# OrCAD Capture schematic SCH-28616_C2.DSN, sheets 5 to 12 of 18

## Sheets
5 M-06 Audio: size C
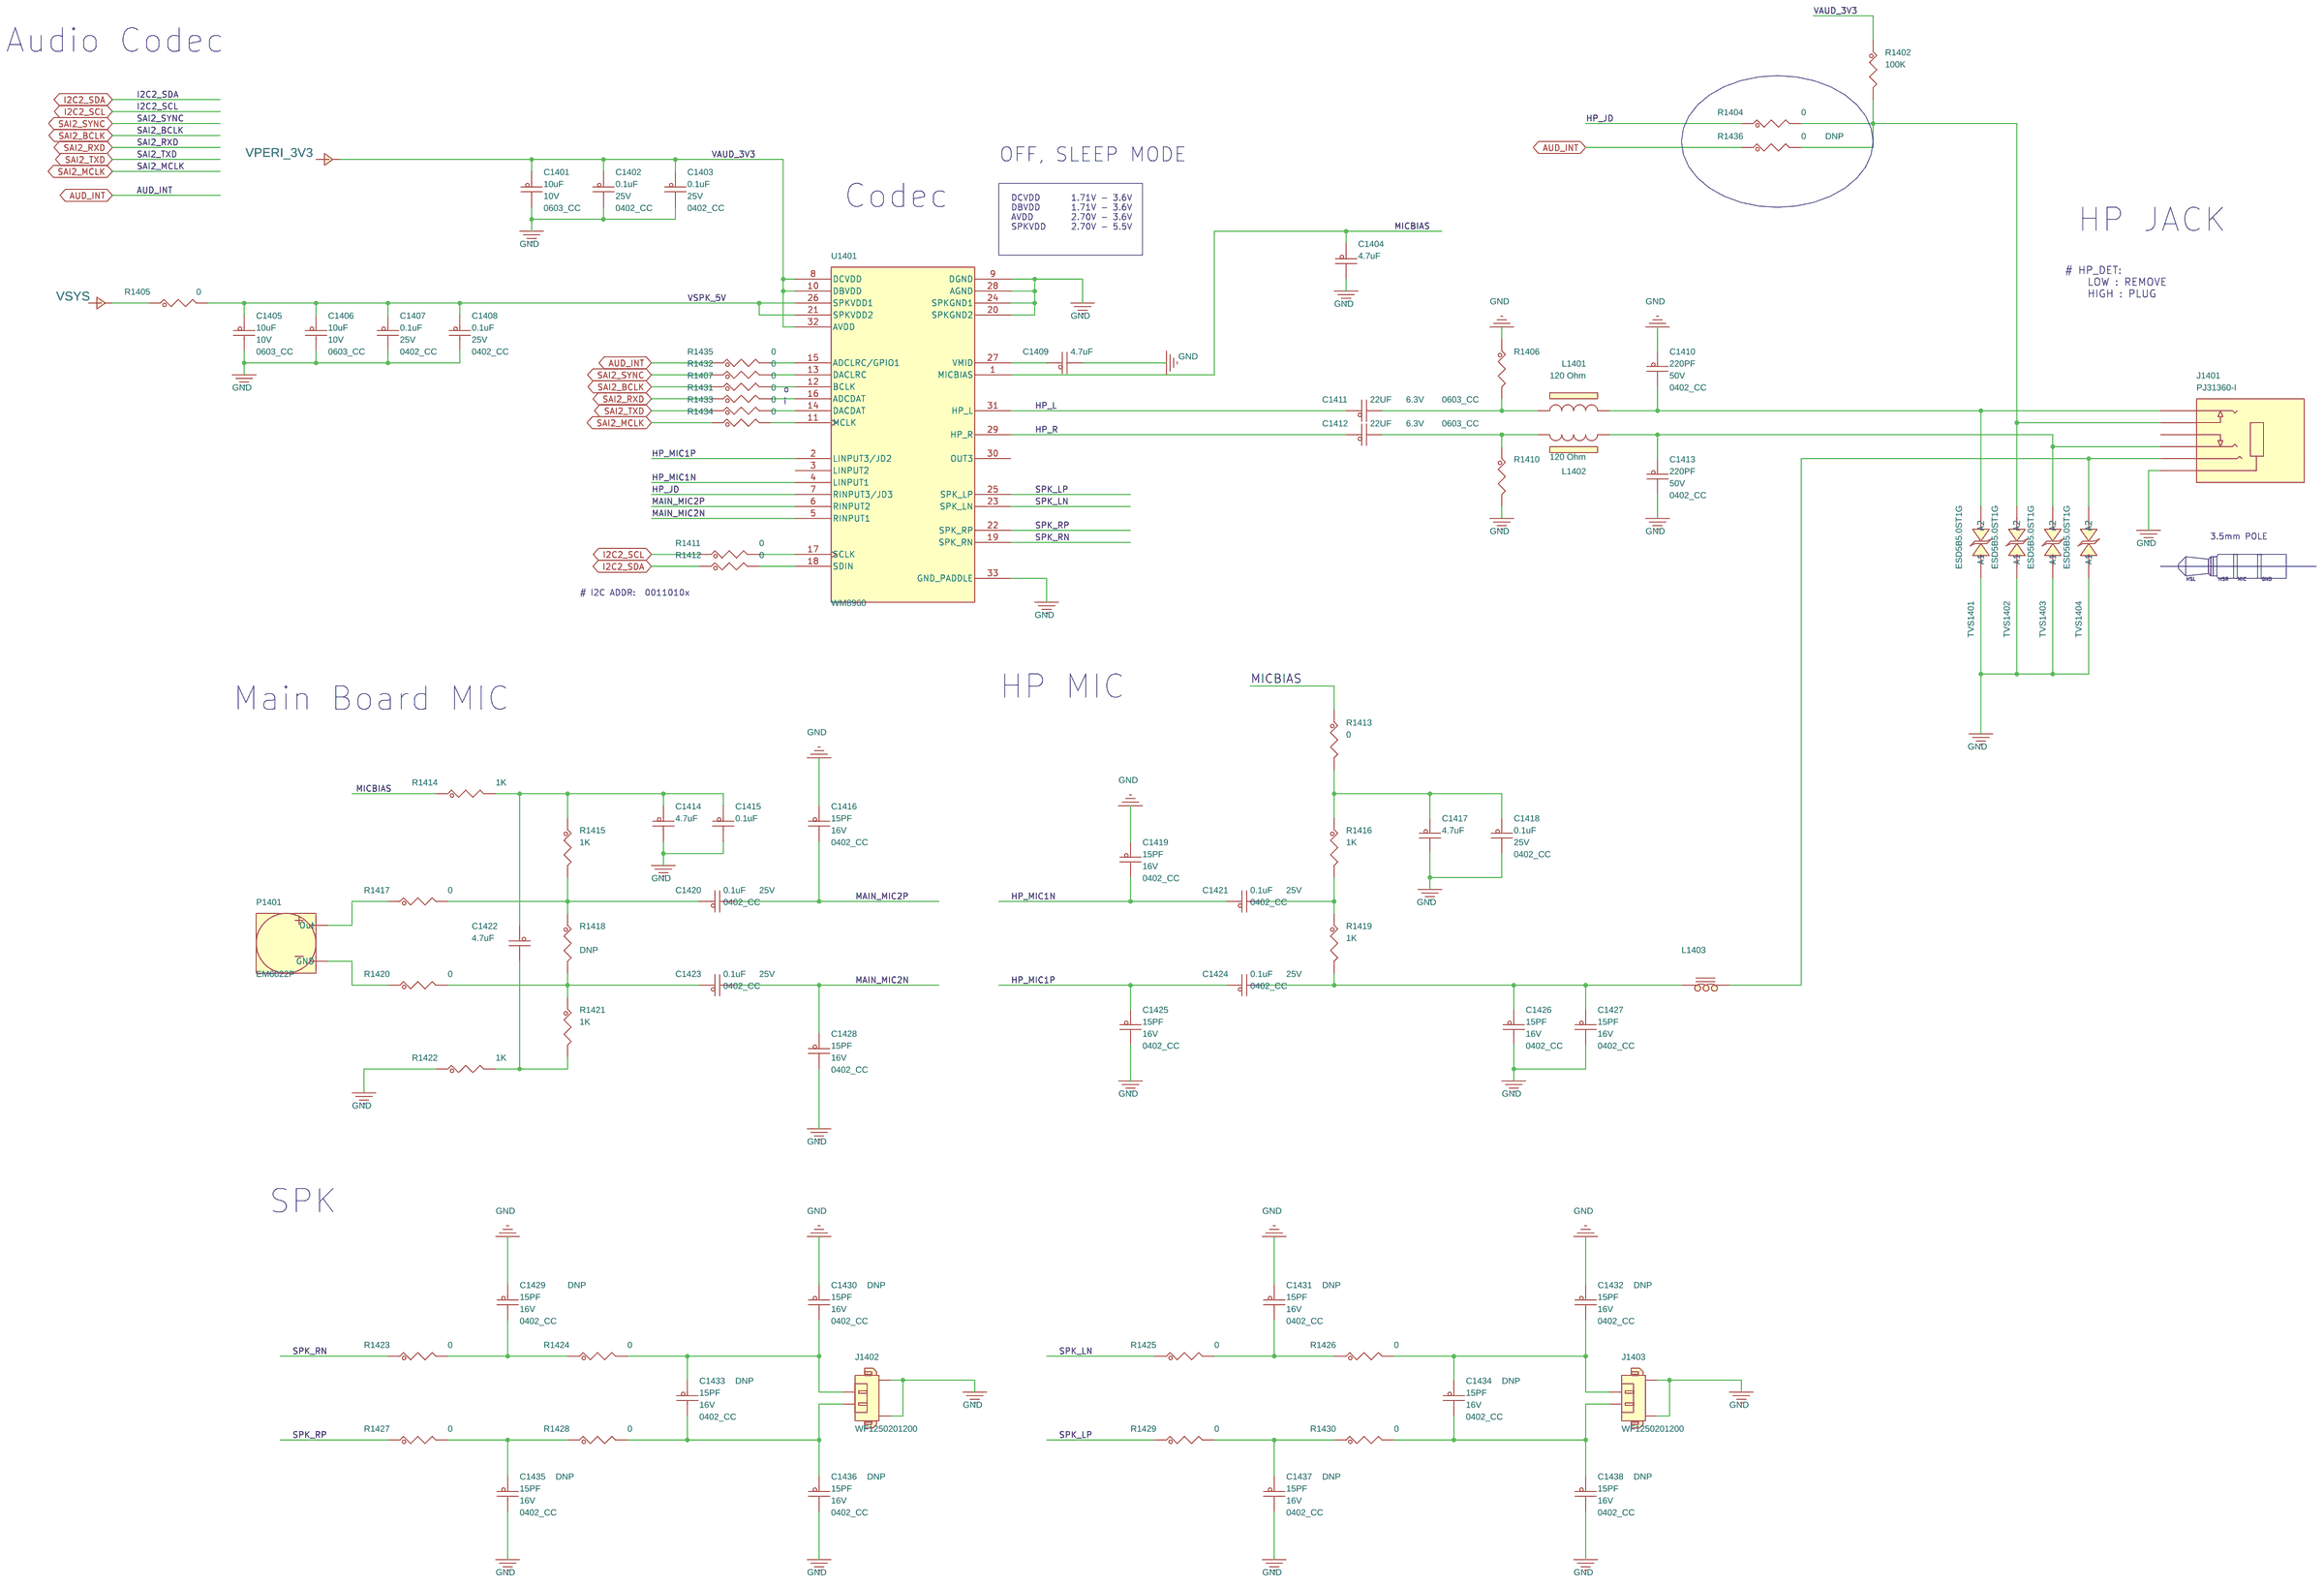
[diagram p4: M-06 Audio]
6 M-05 Sensor: size C
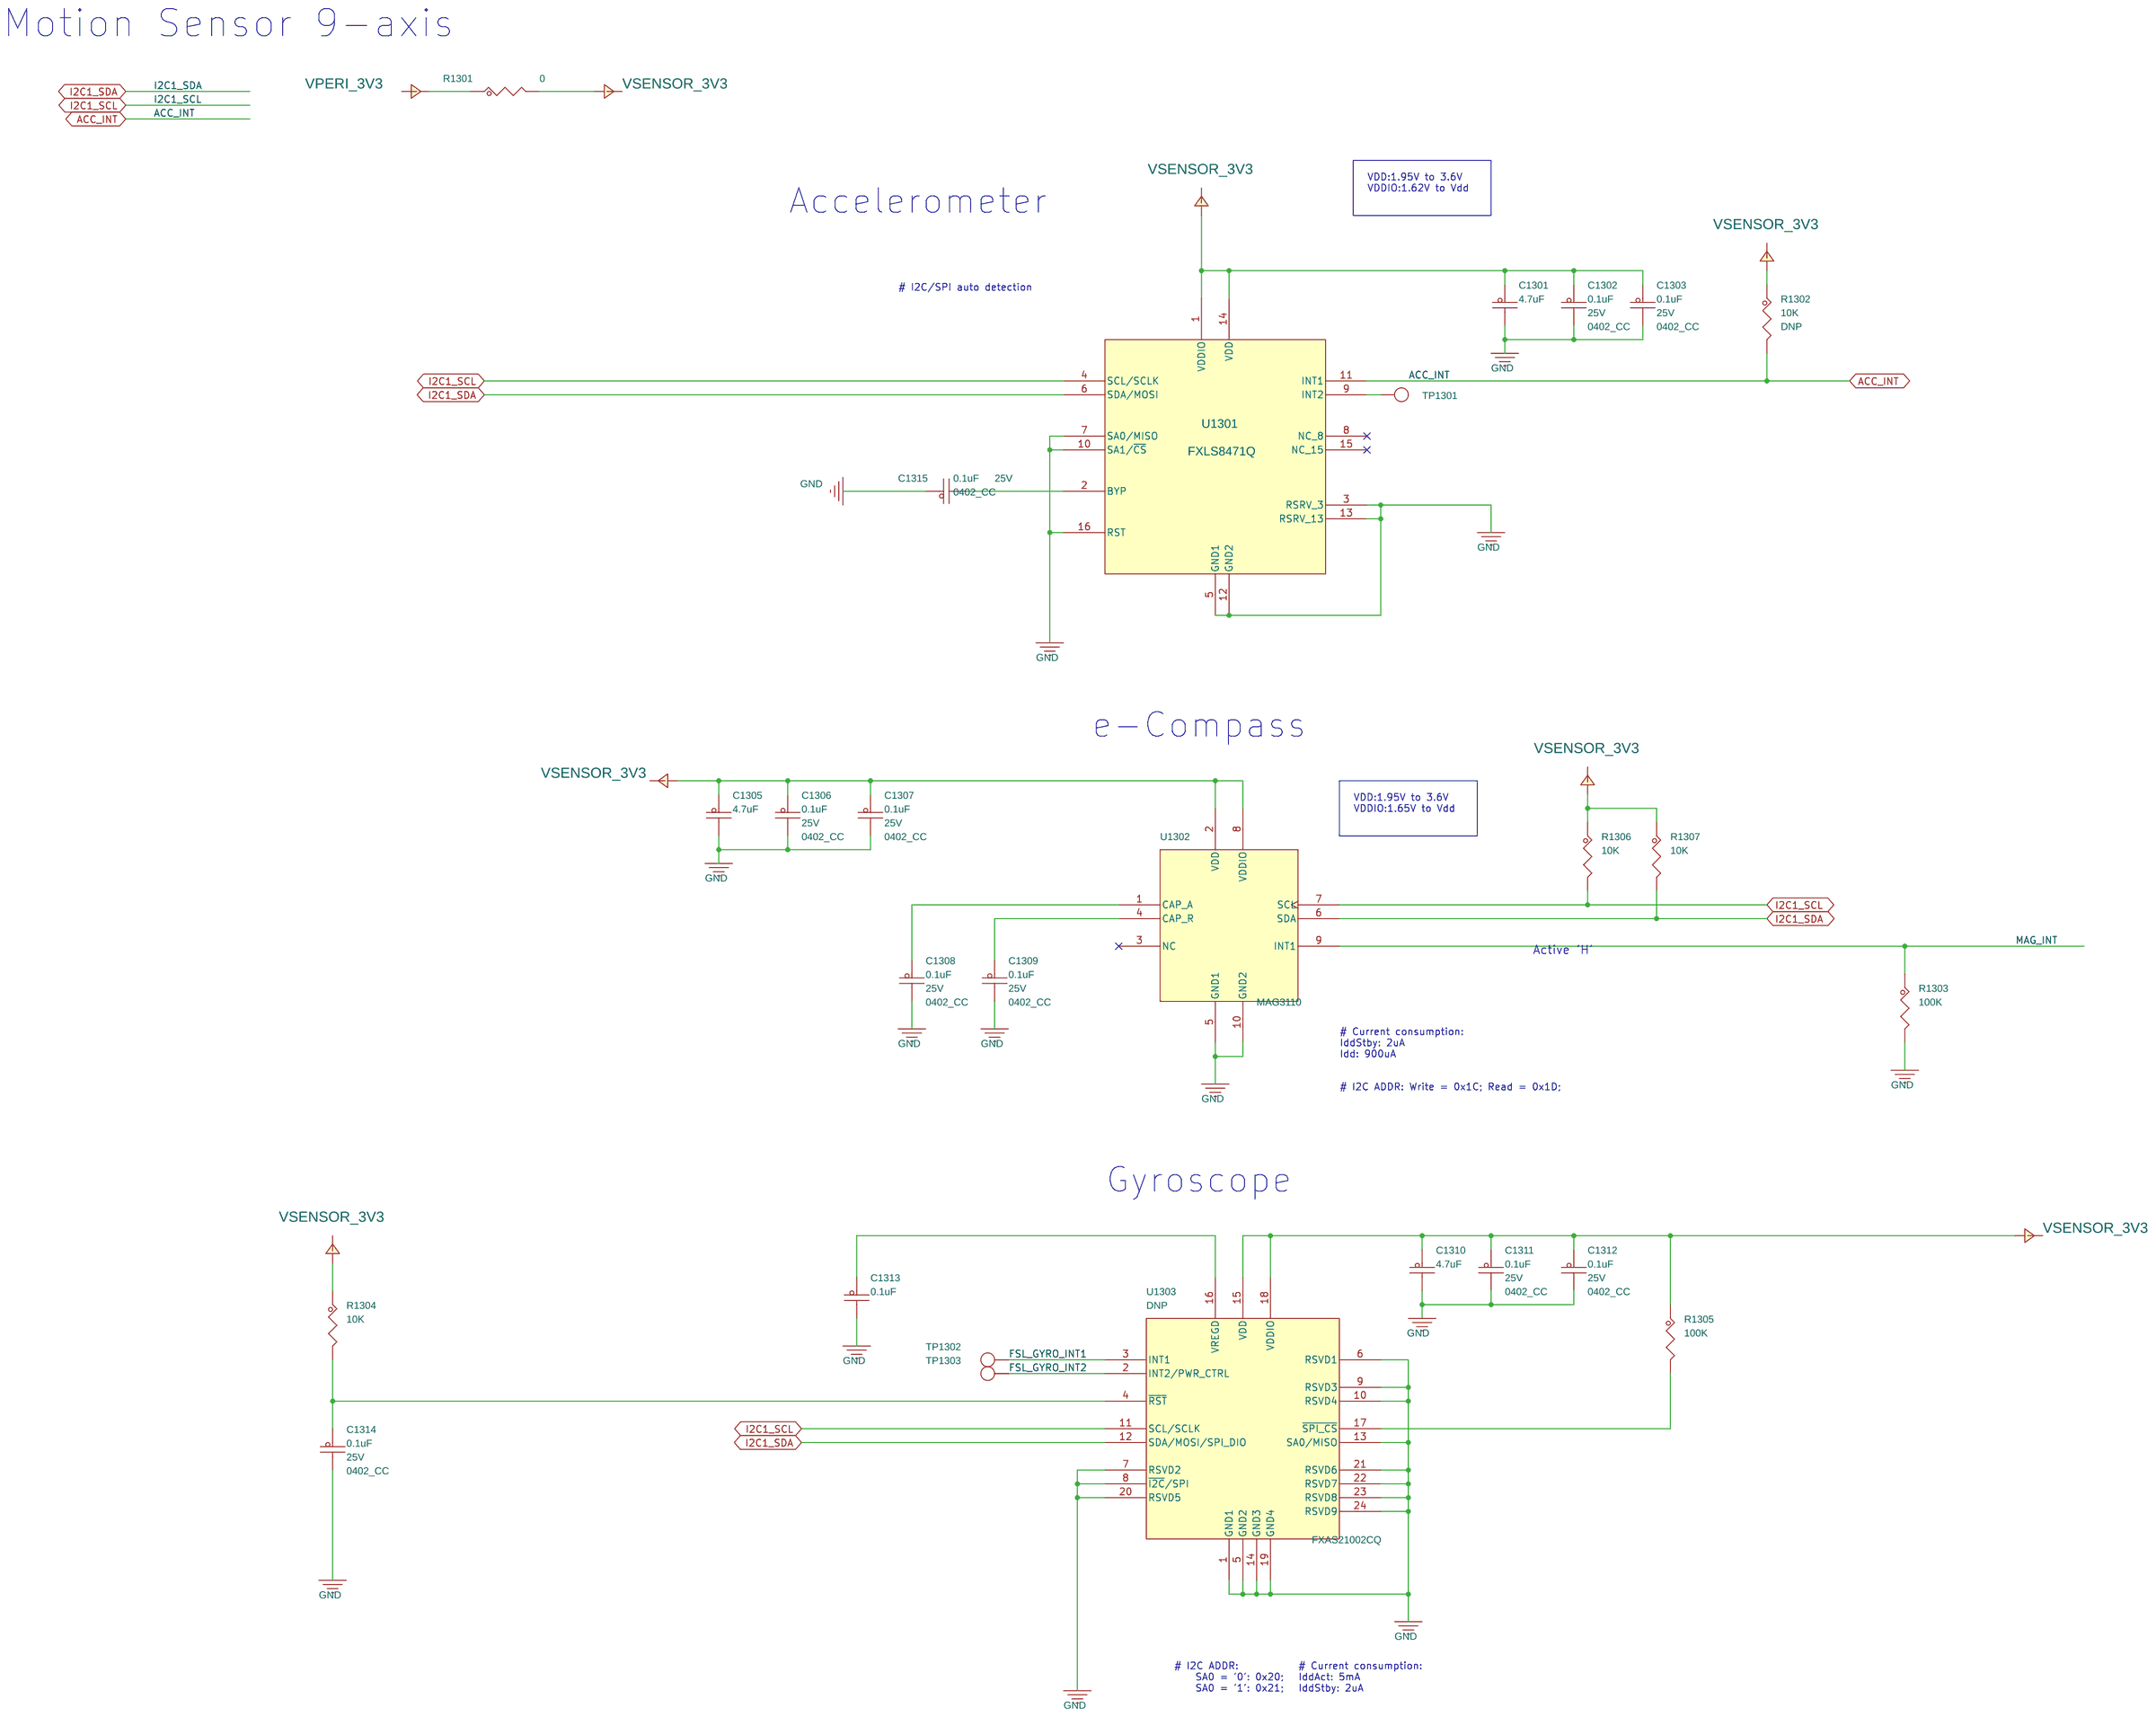
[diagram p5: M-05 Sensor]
7 M-04 CAN BUS: size C
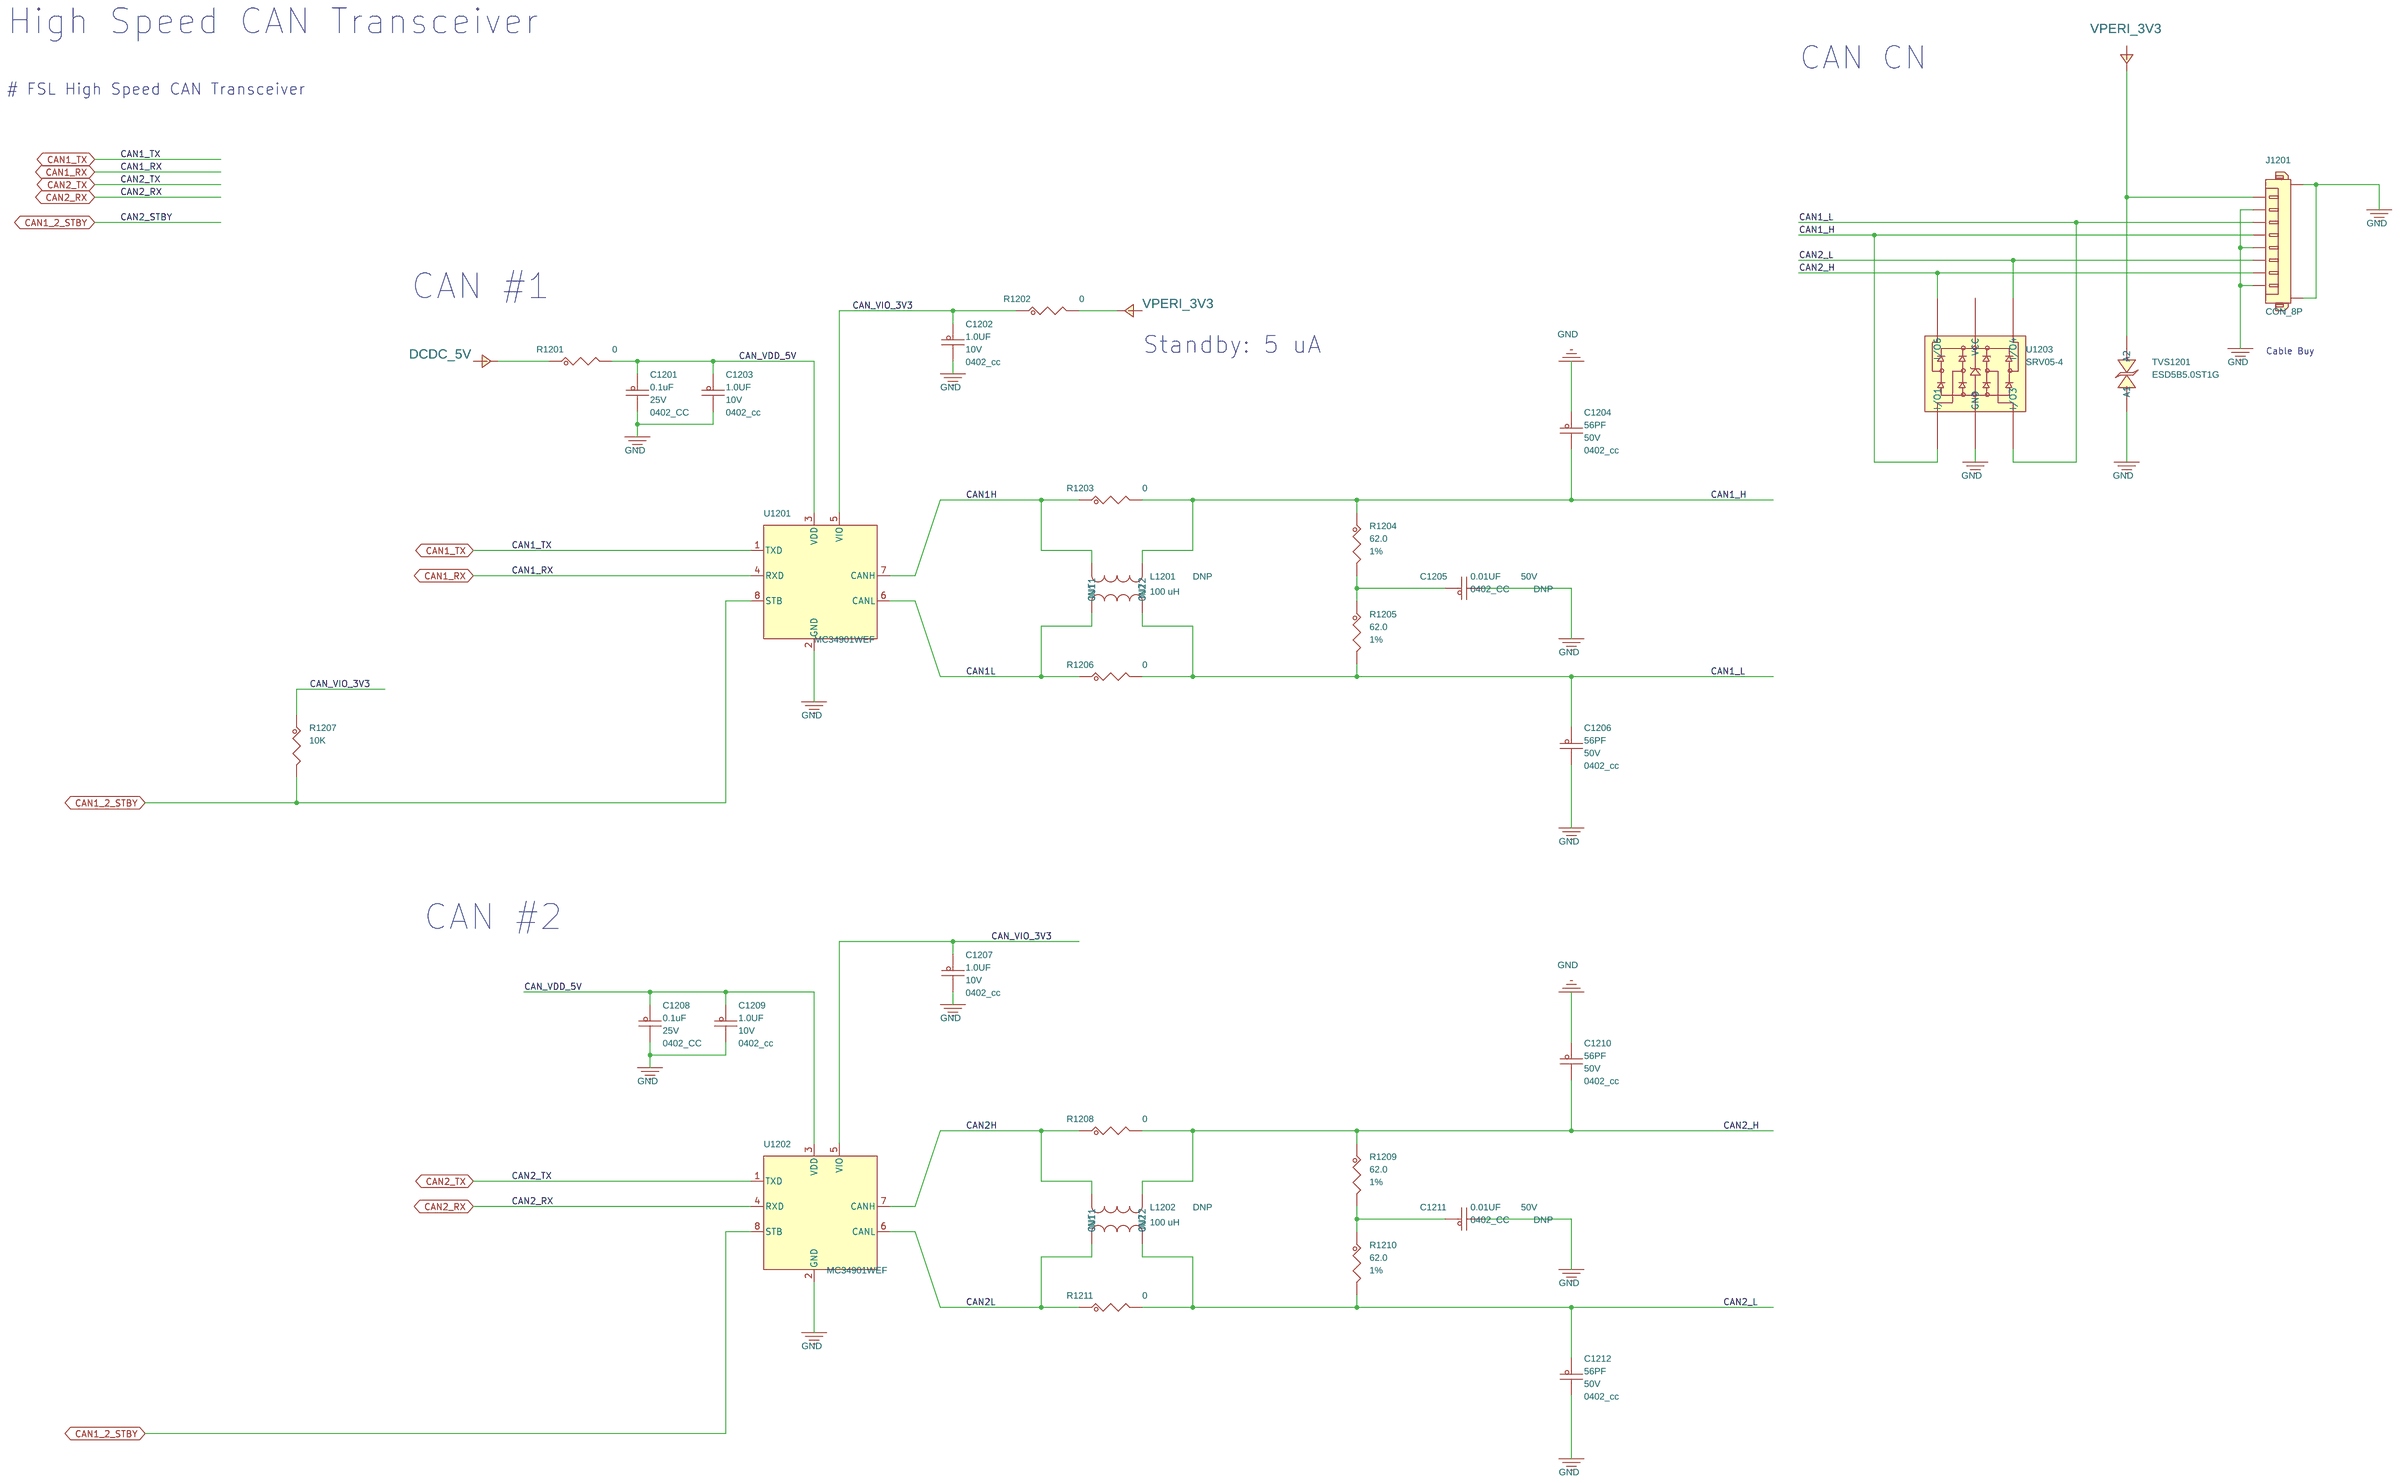
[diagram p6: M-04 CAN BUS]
8 M-01 LCD: size C
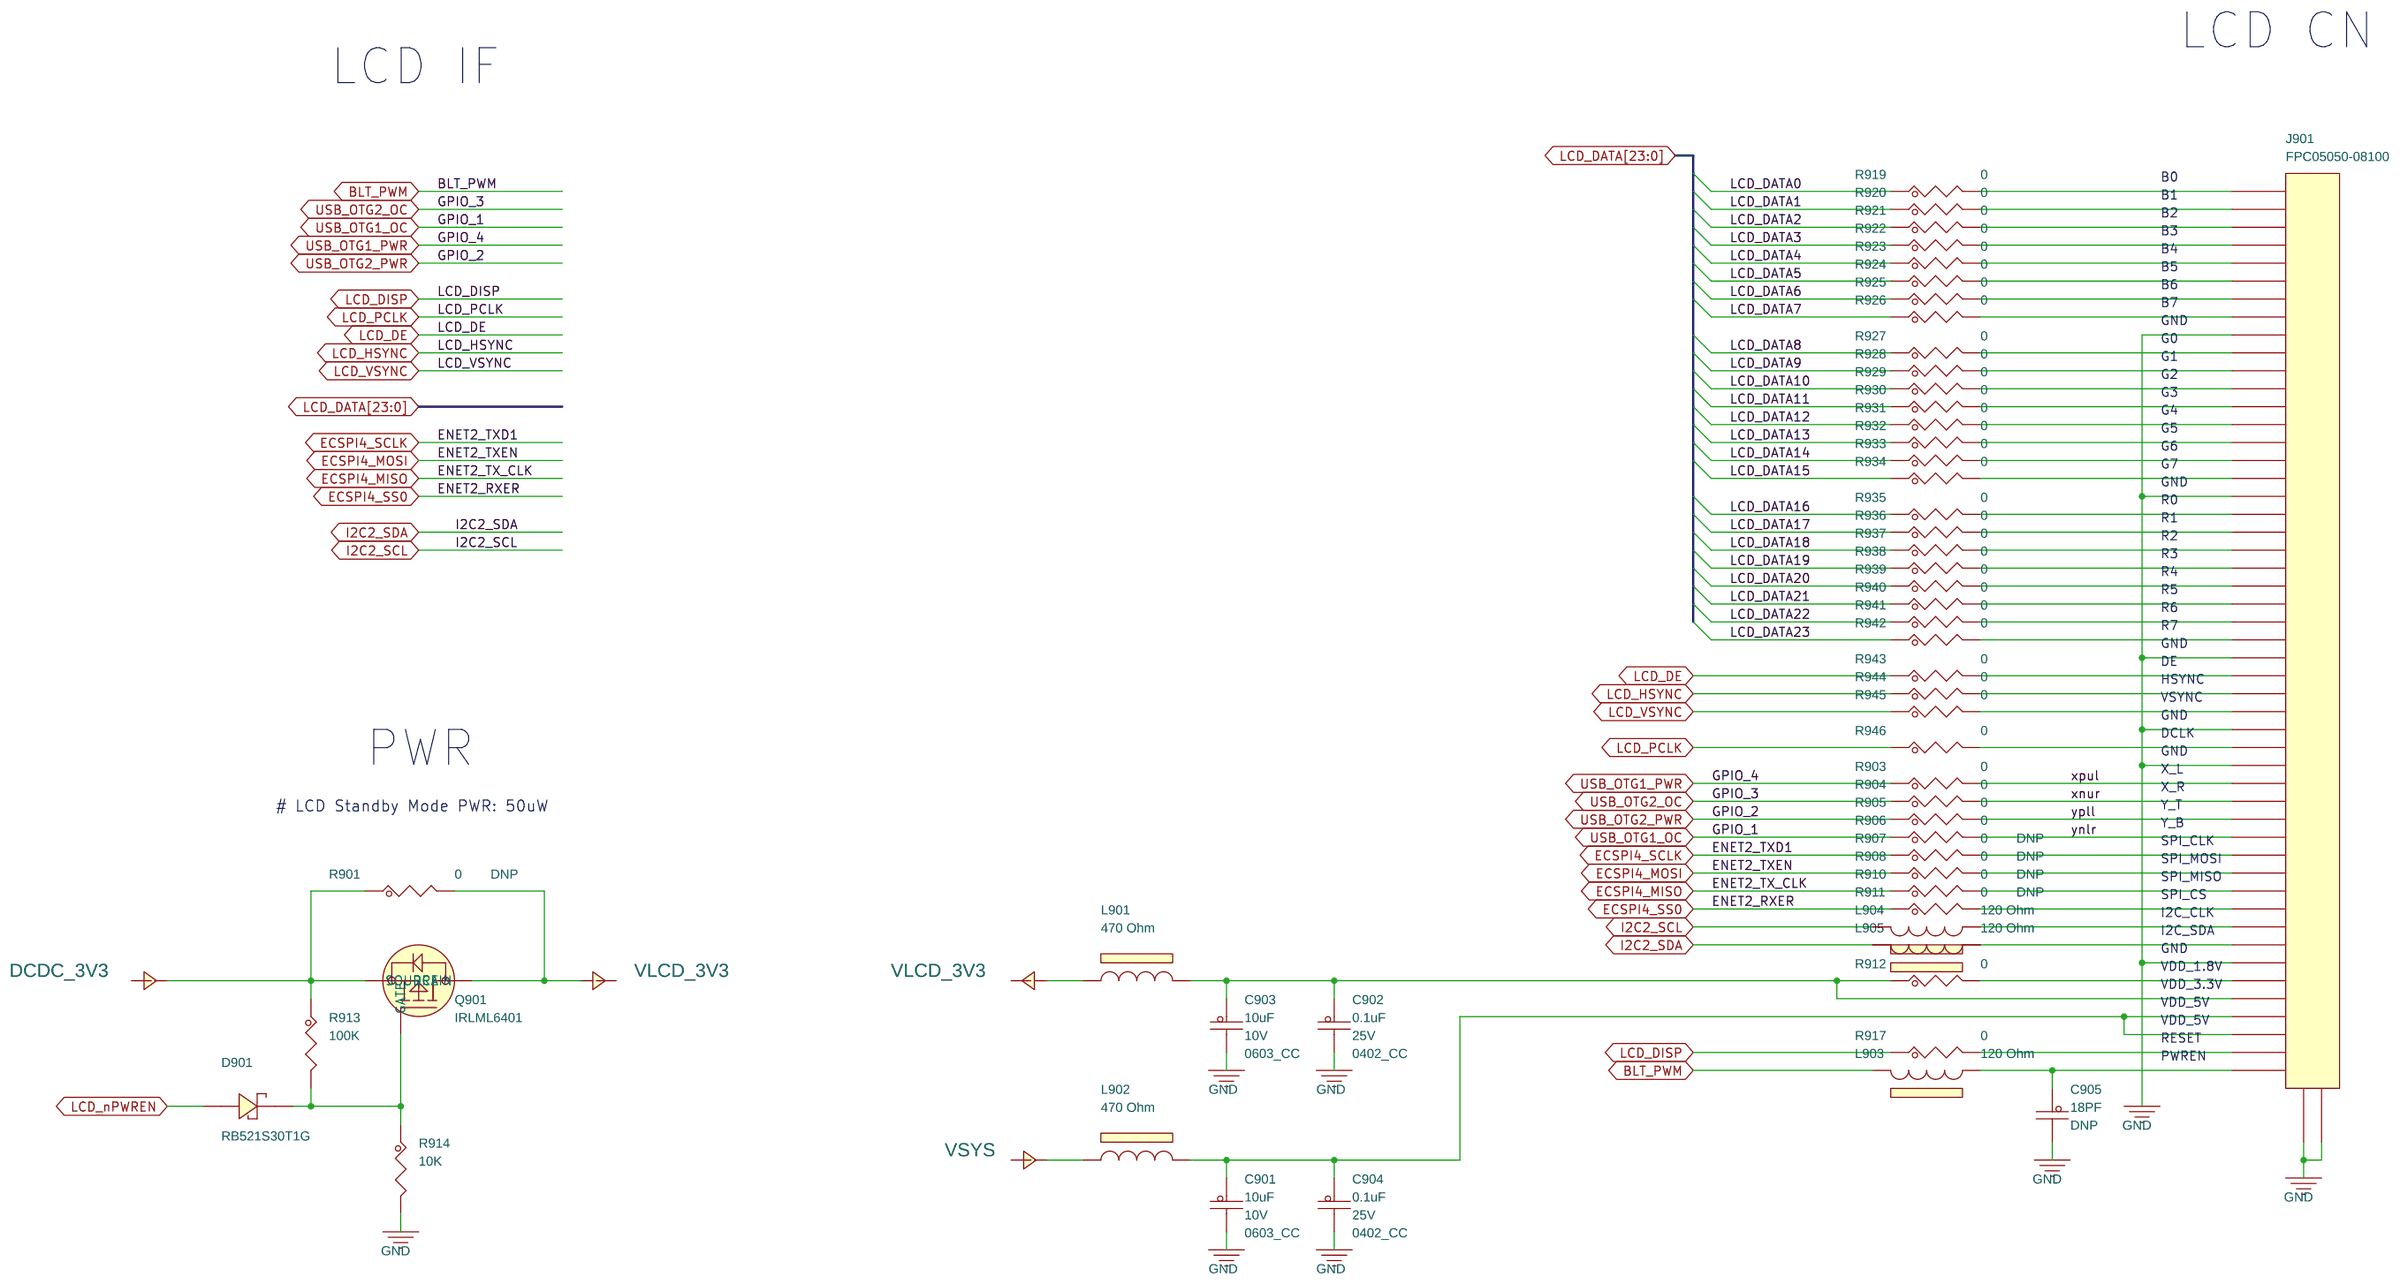
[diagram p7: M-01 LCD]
9 A-02 PWR TREE
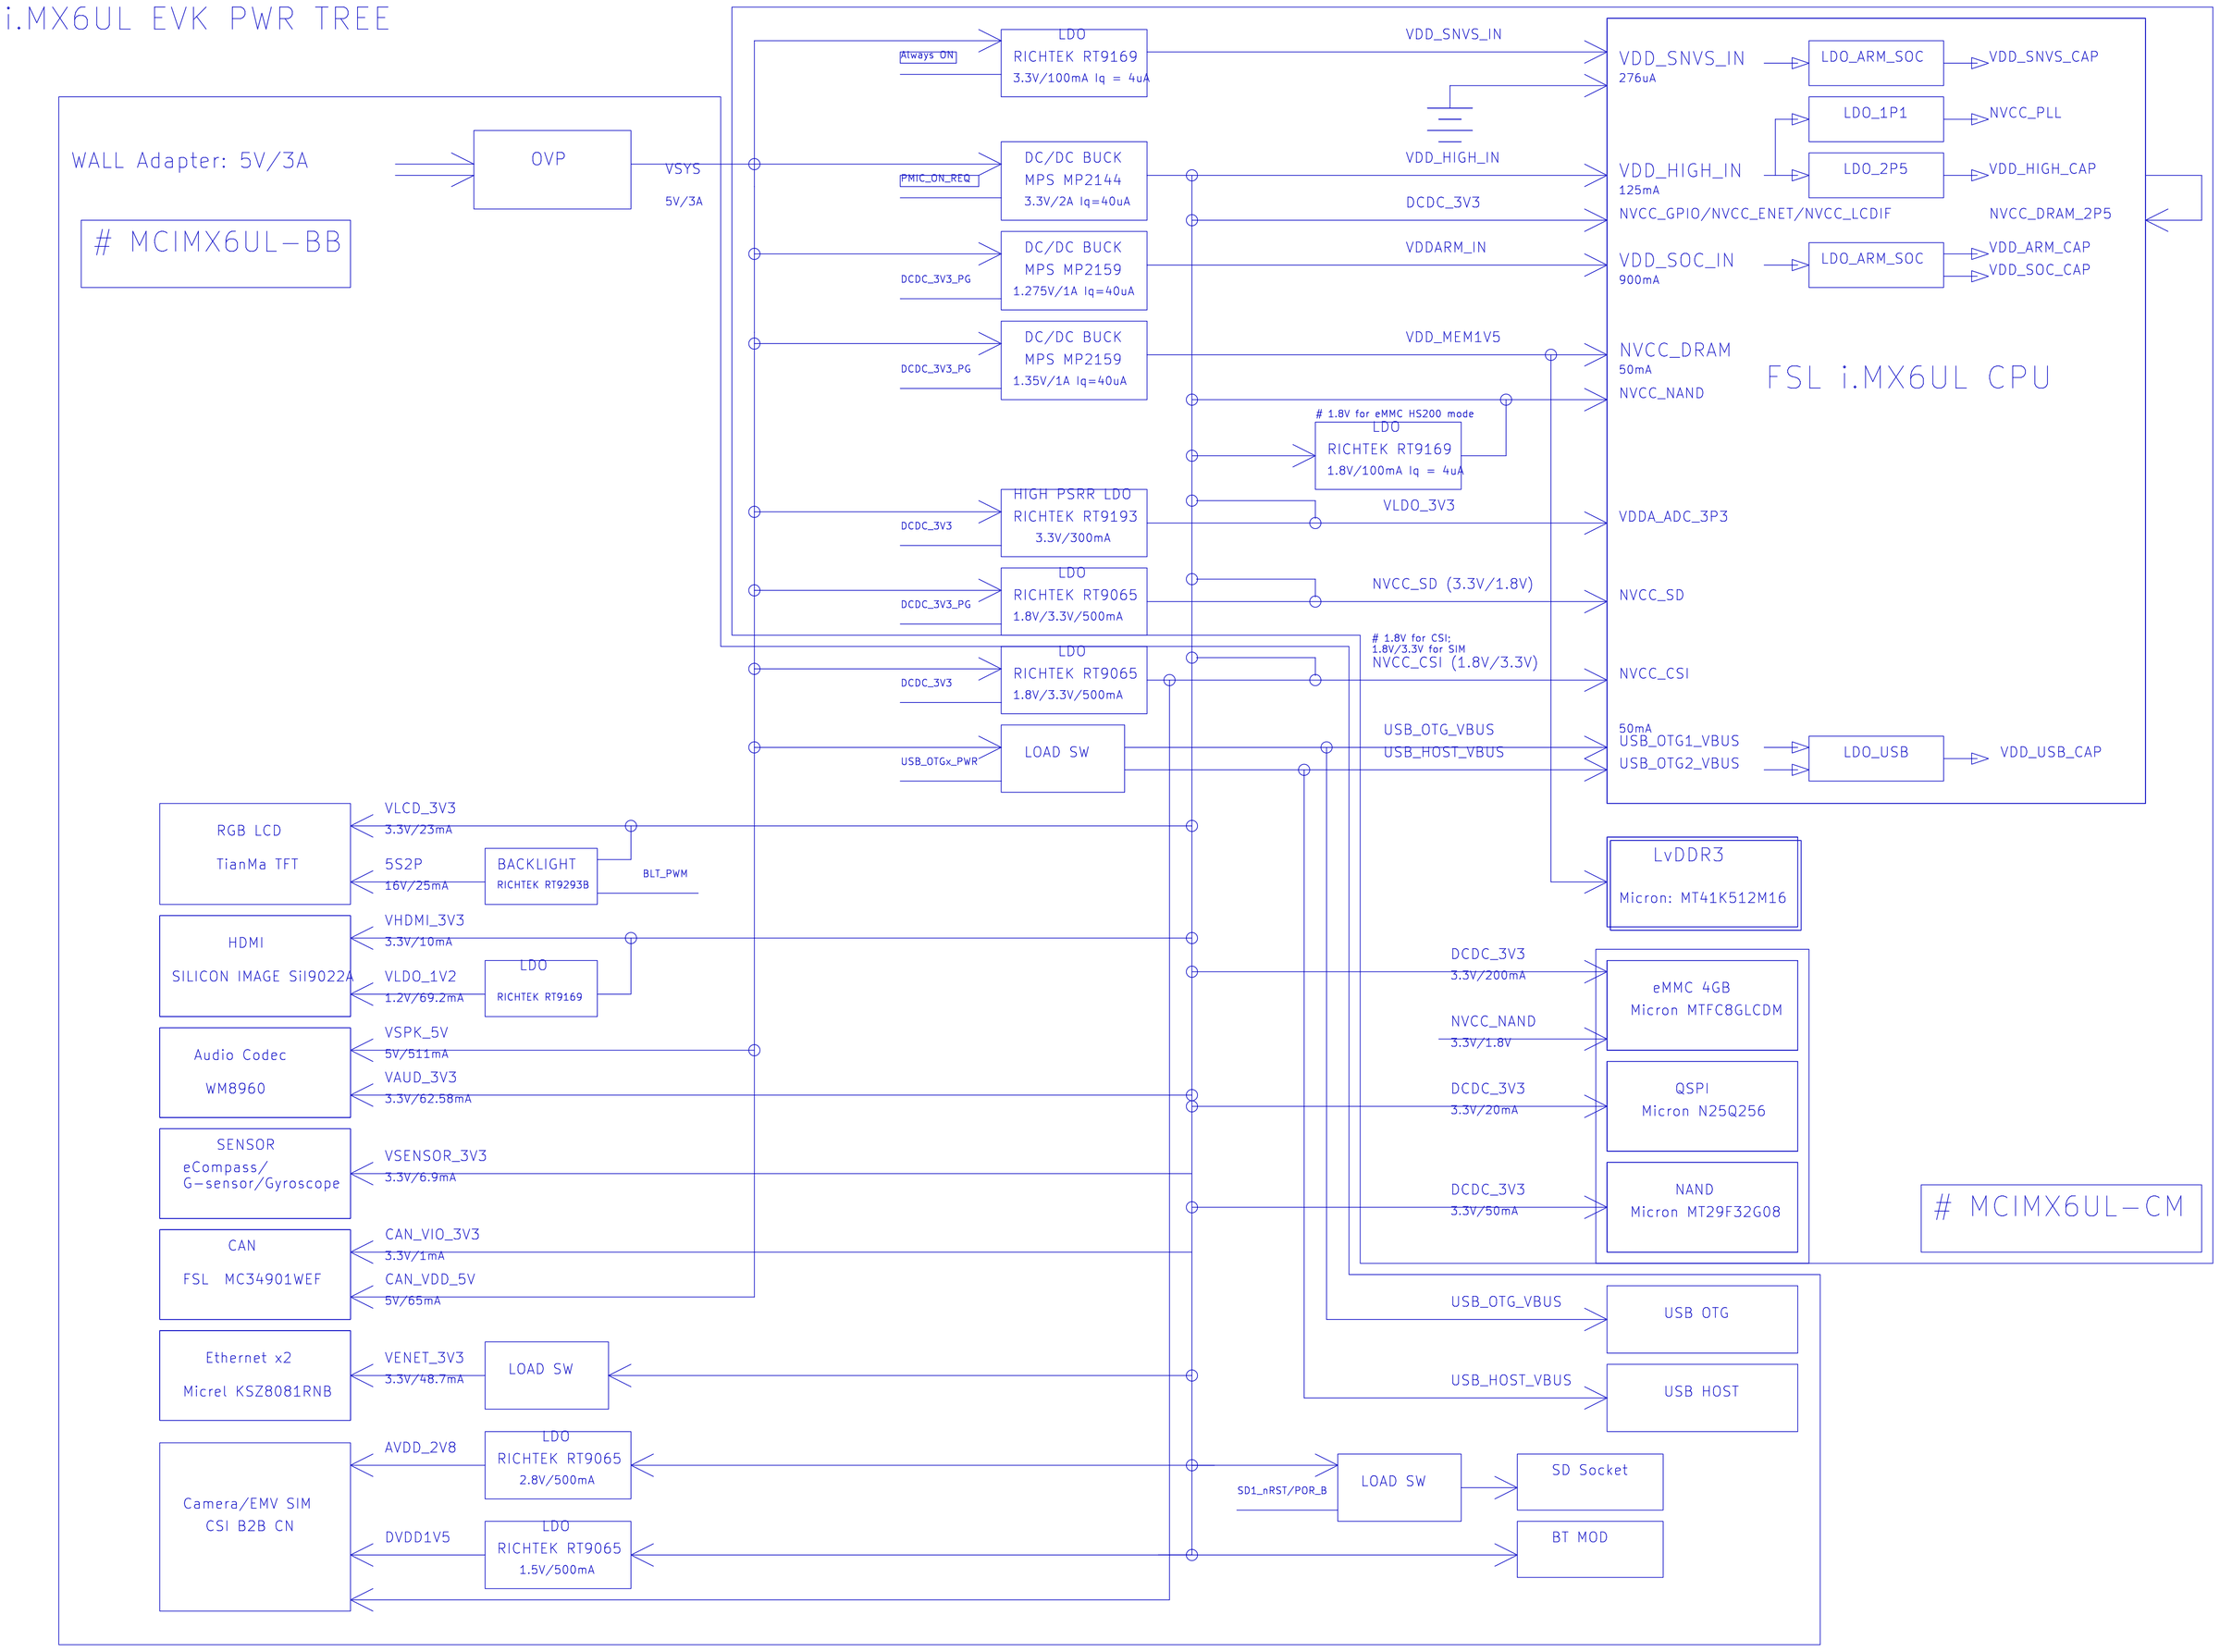
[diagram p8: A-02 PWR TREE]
10 A-01 BLOCK DIAGRAM
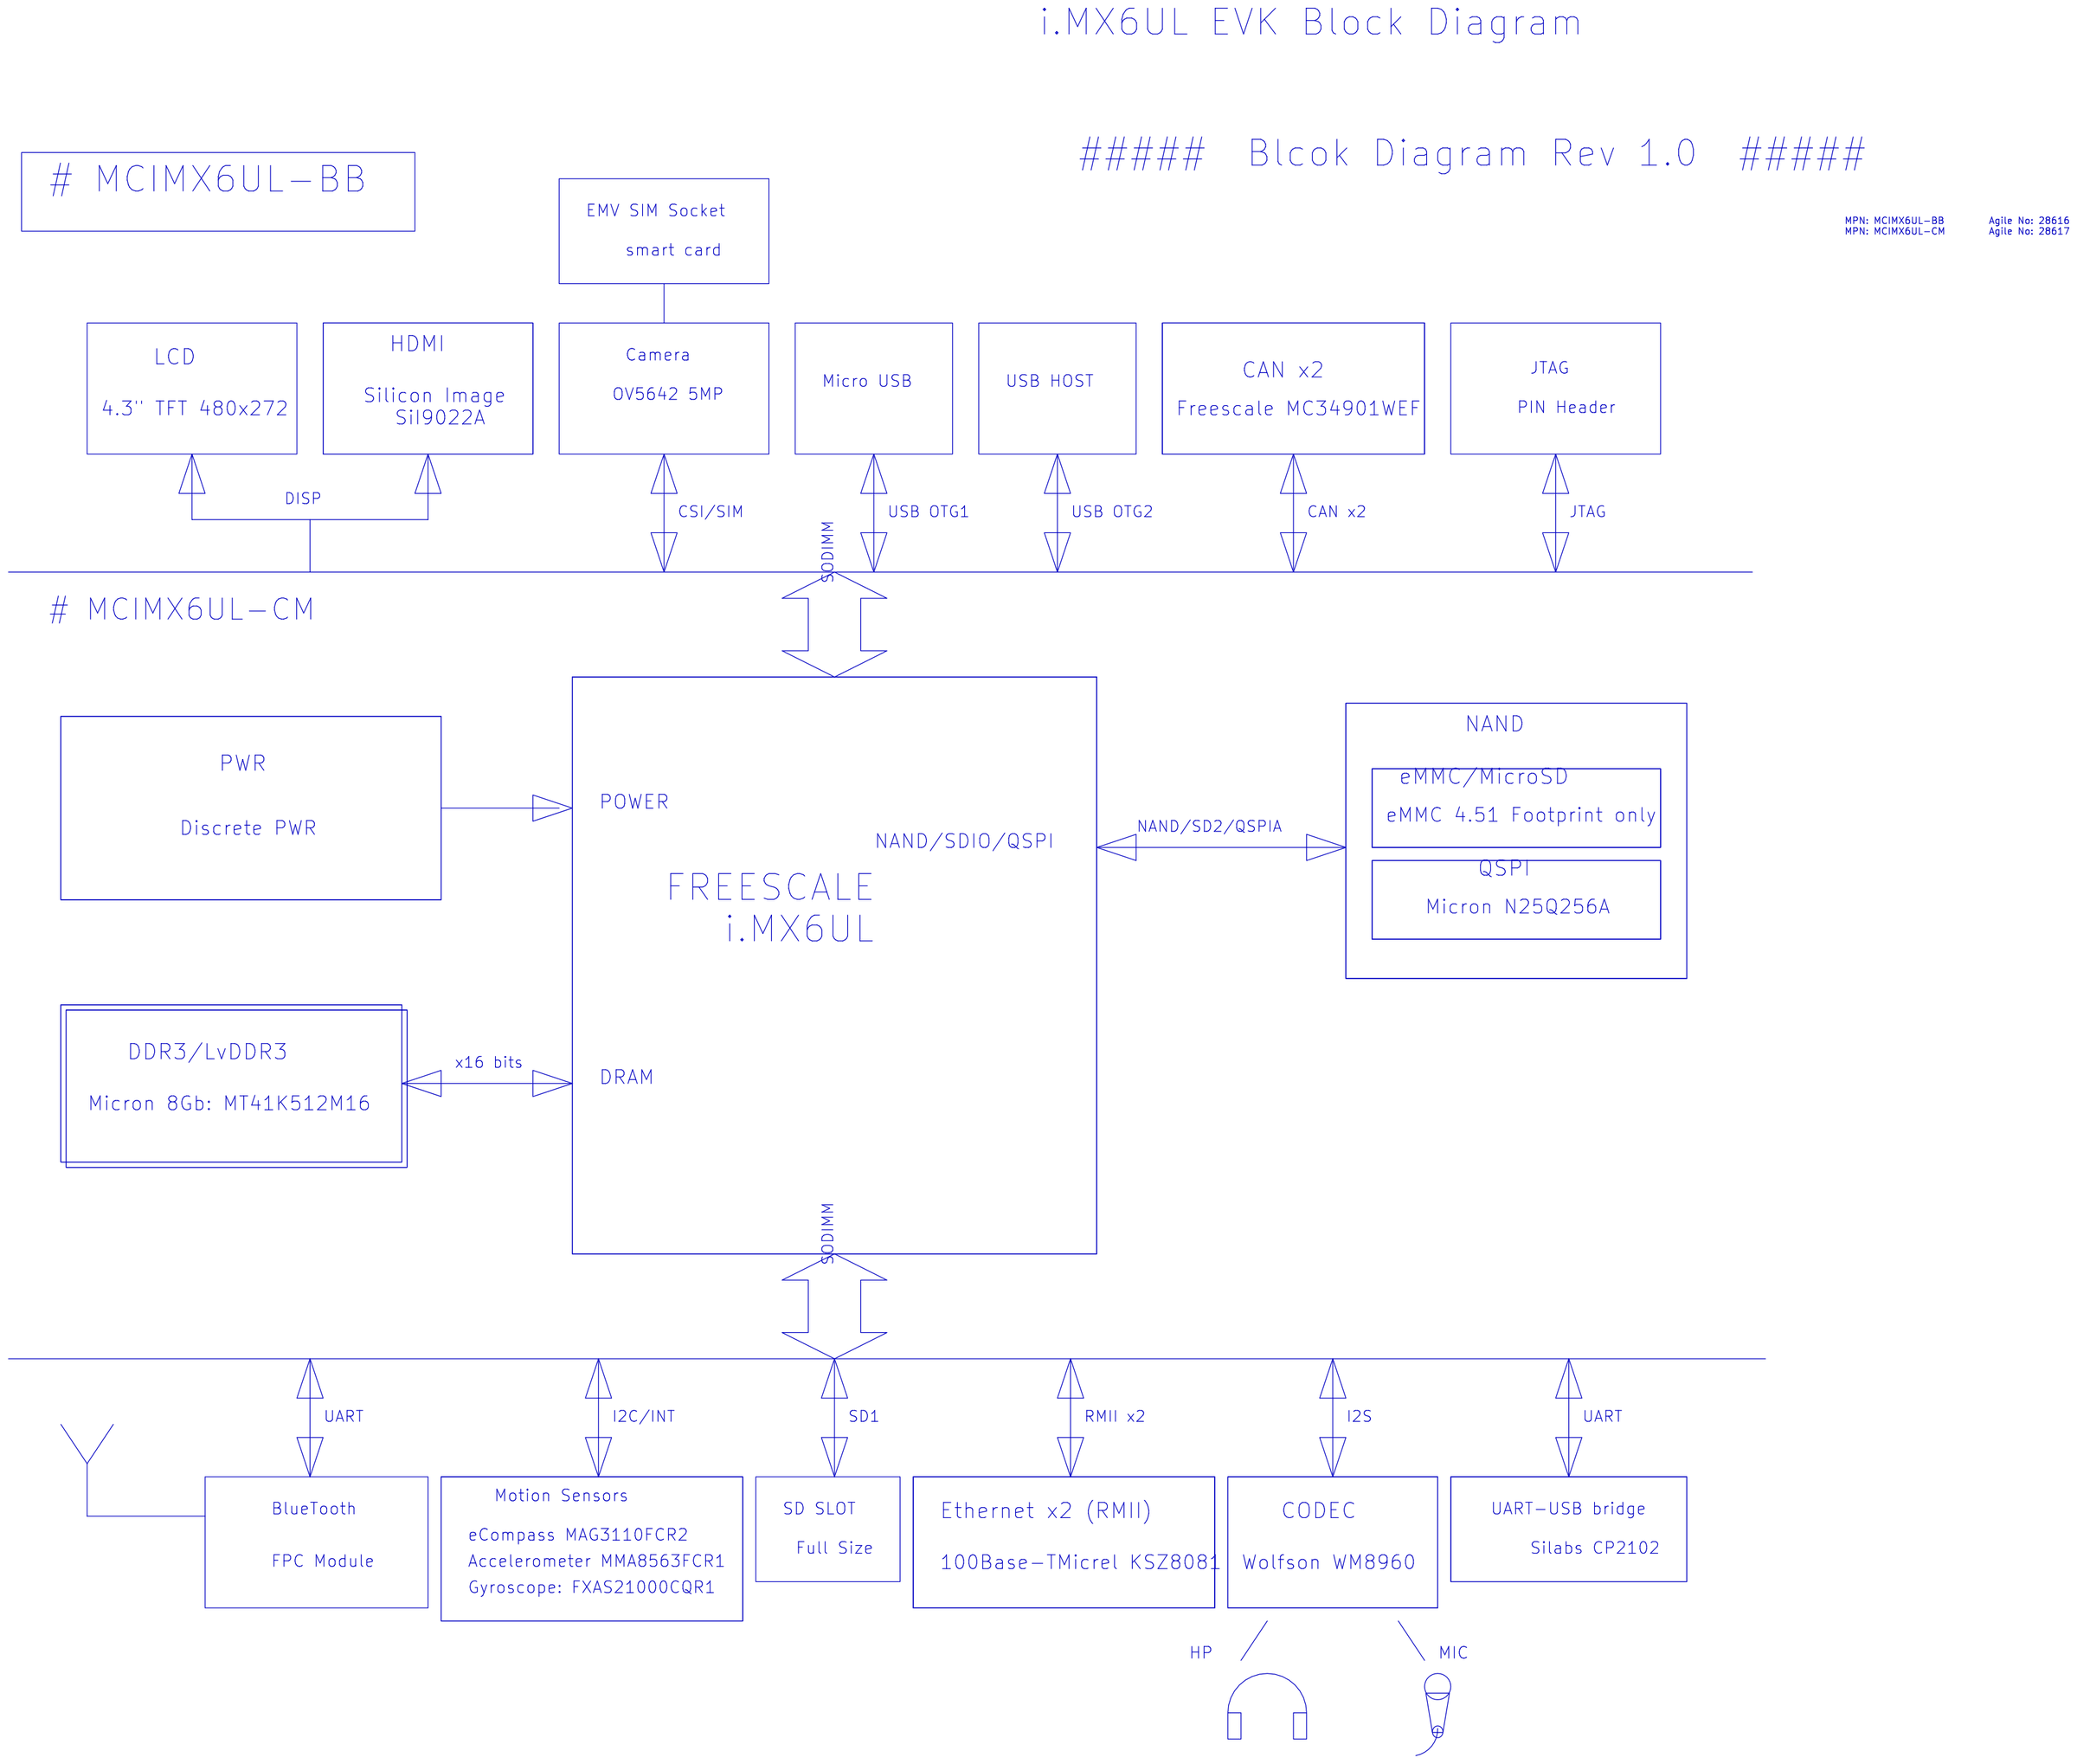
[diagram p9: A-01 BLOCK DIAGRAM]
11 A-00 COVER
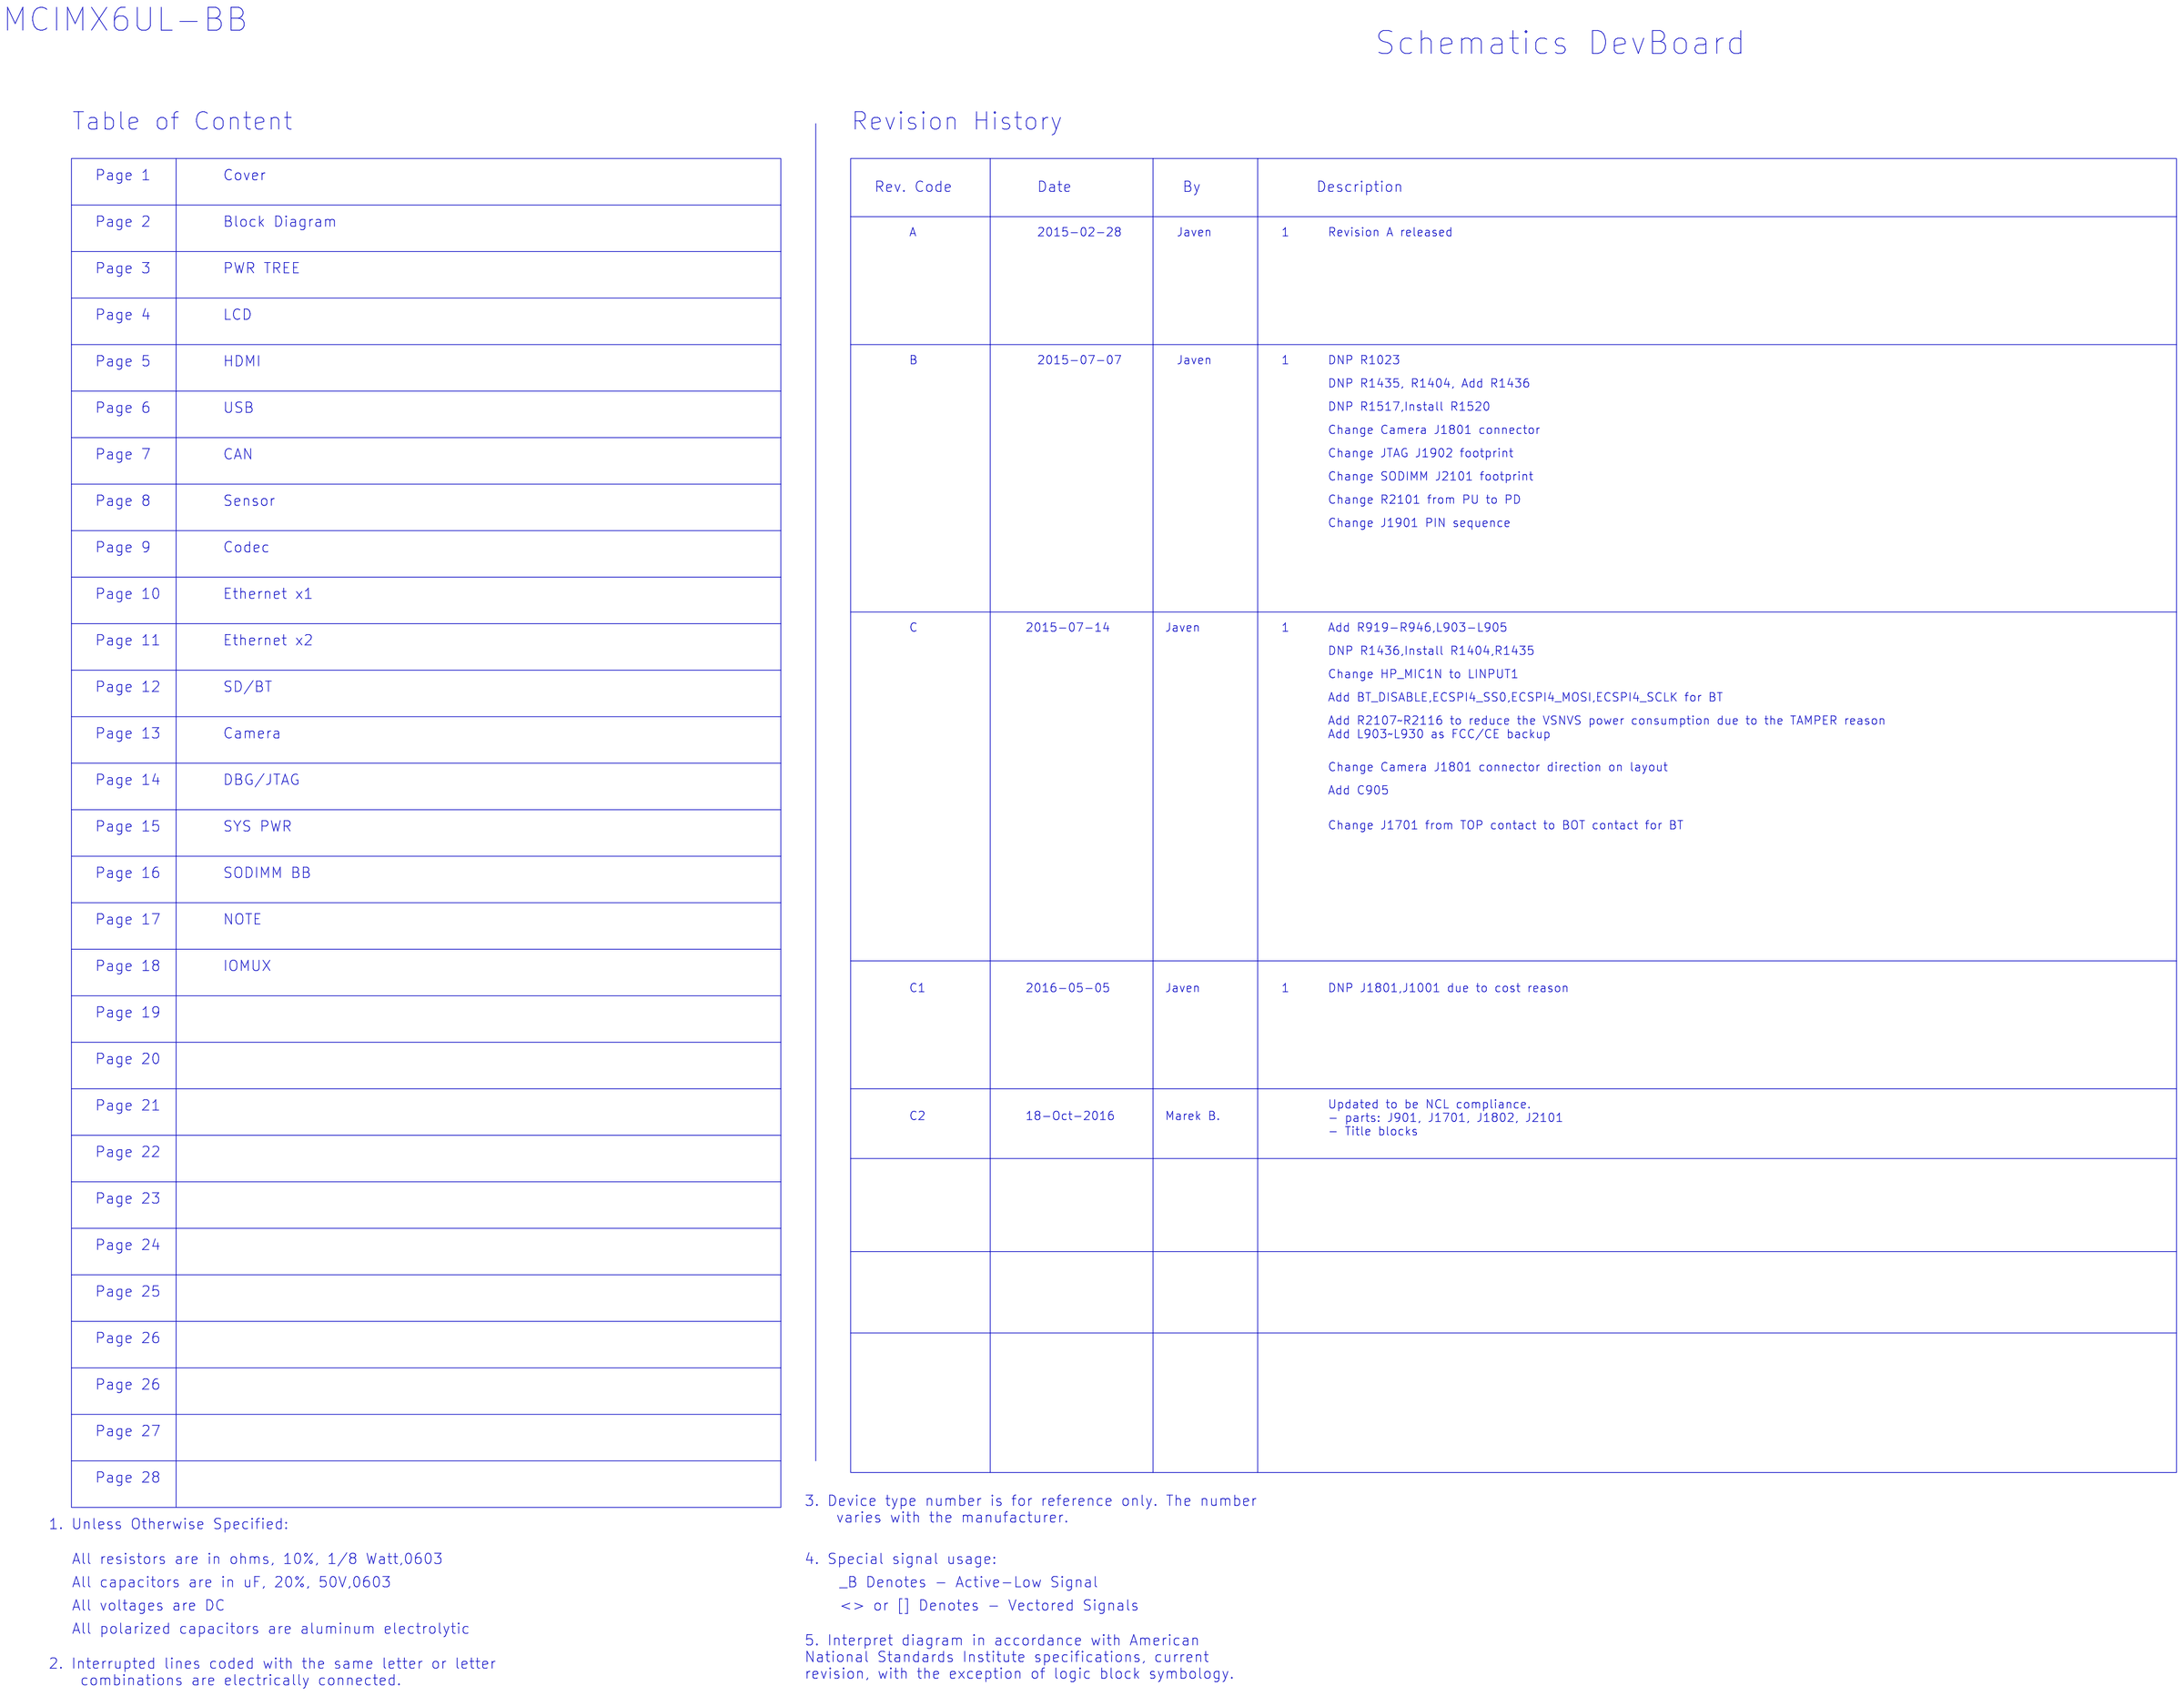
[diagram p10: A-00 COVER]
12 M-02 HDMI: size C

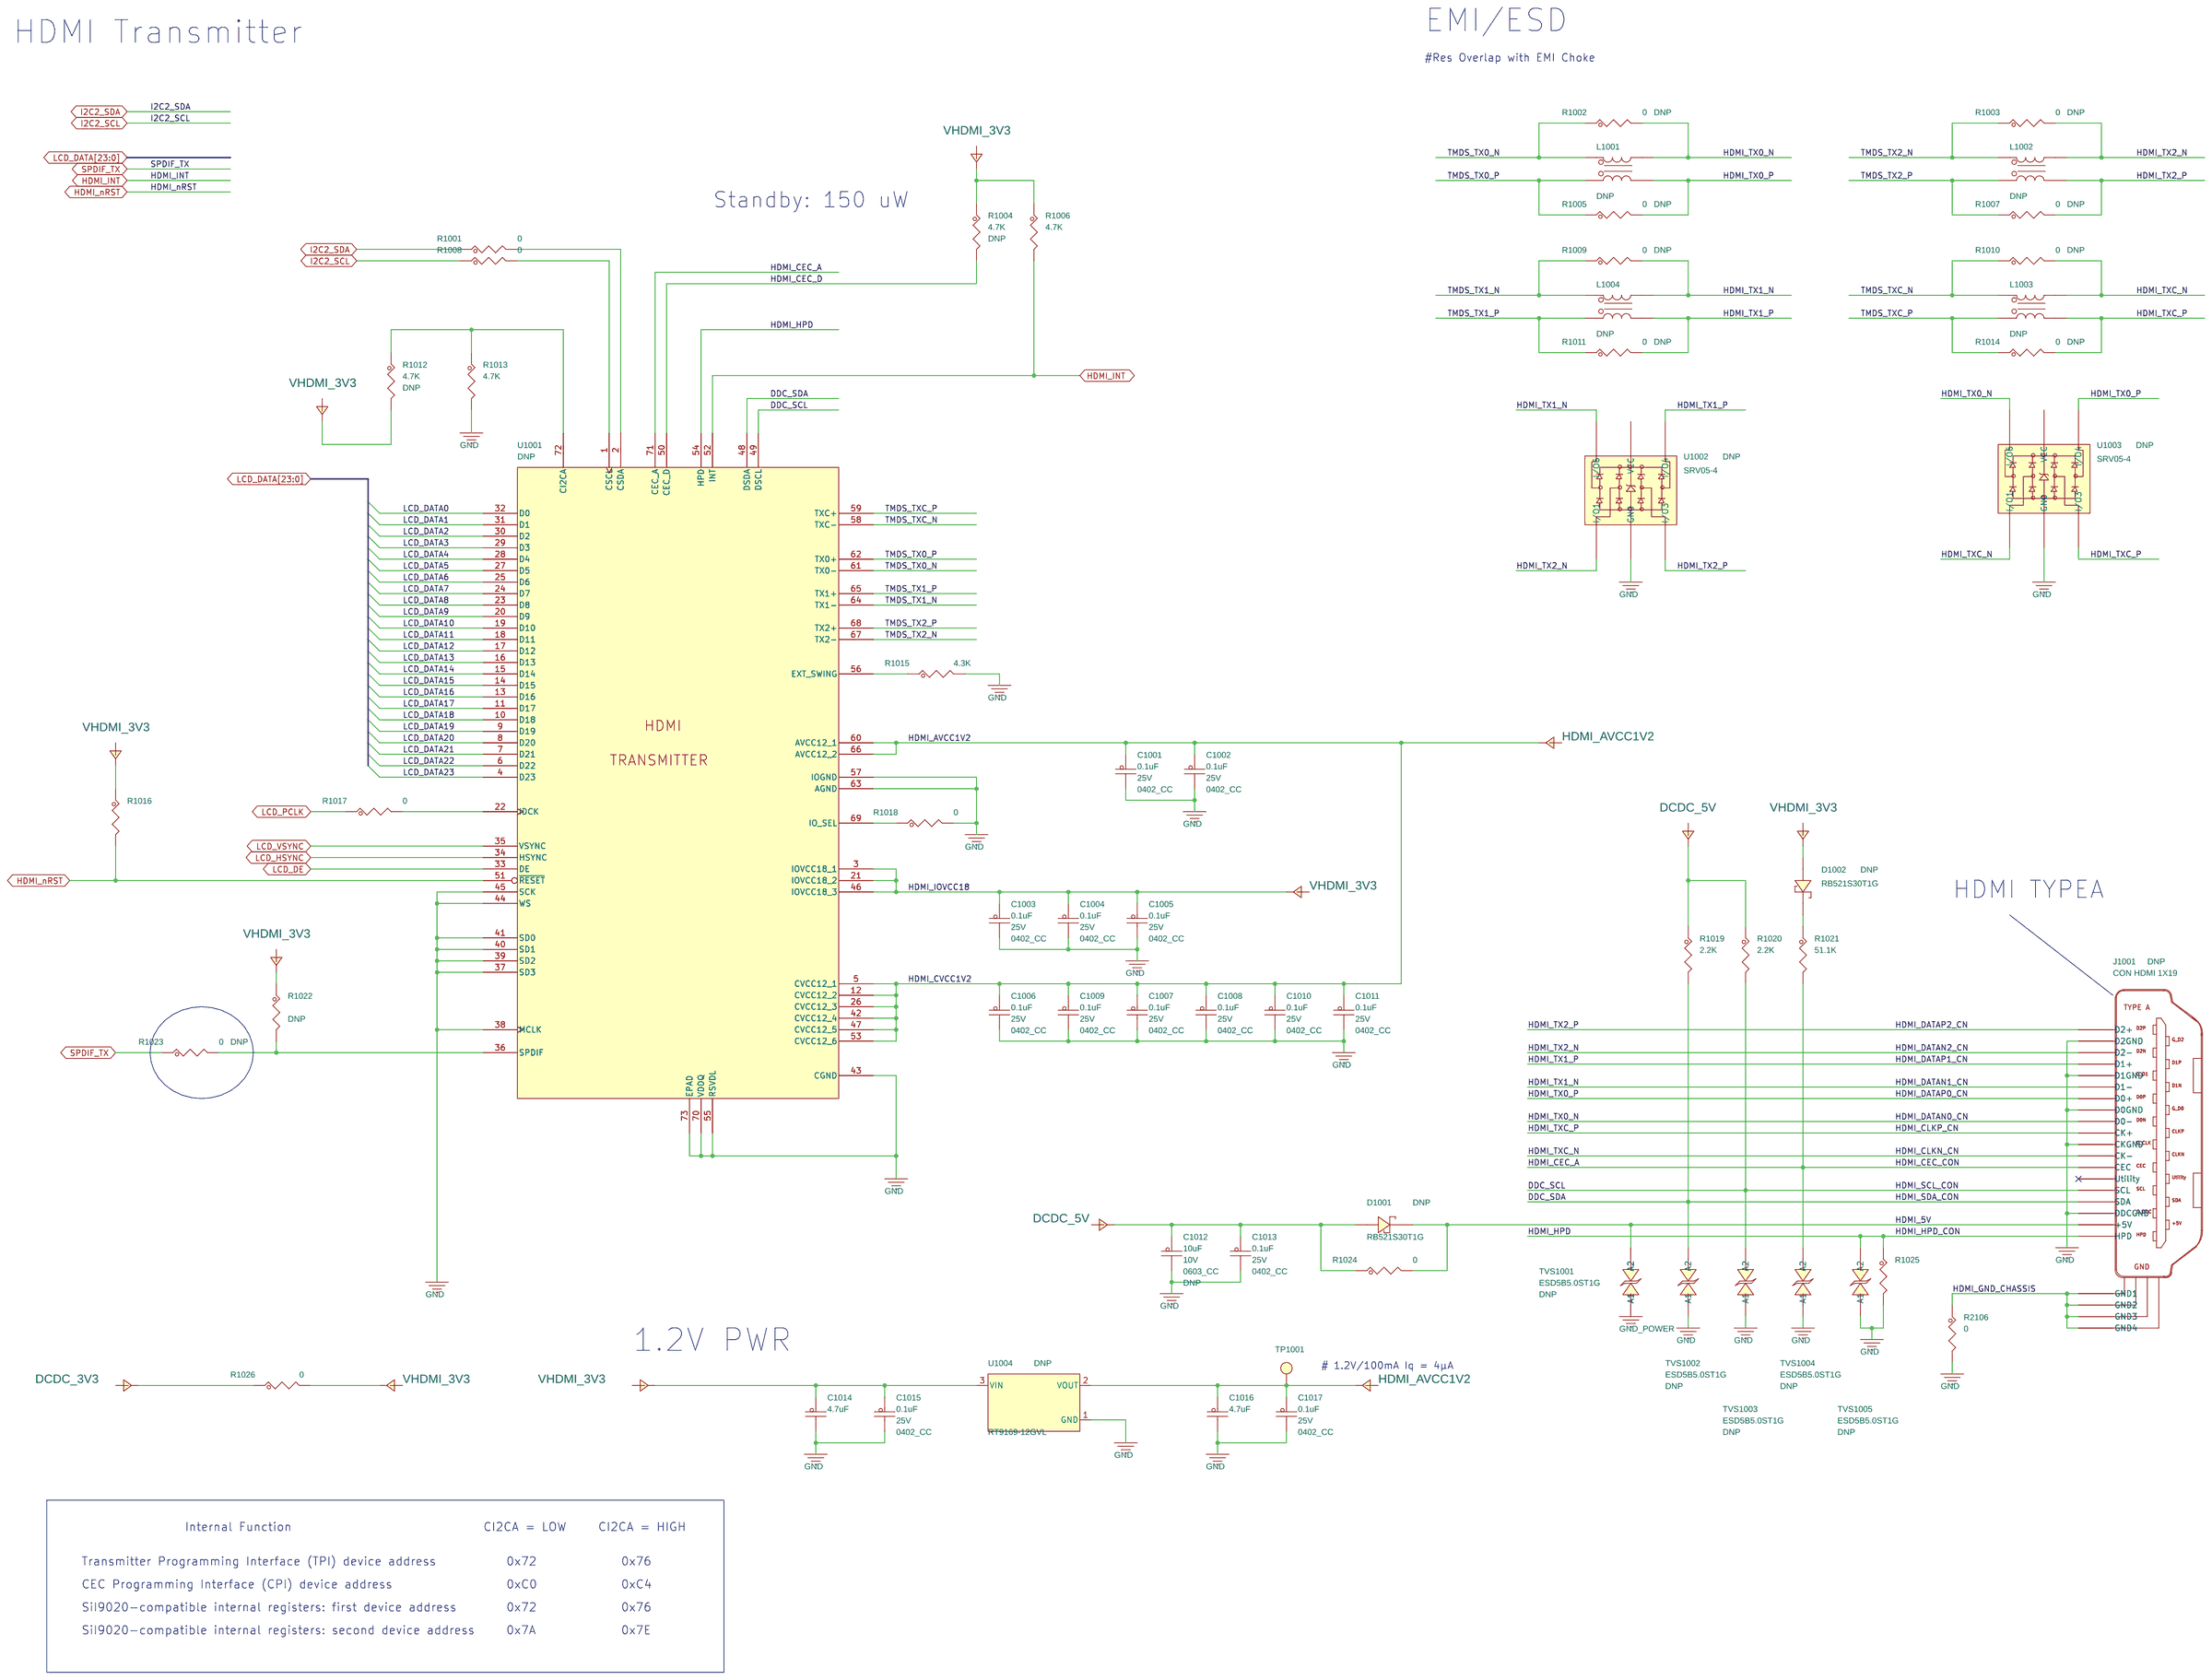
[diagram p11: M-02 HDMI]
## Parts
sheet M-01 LCD
C901  10uF  [0603_CC]
C902  0.1uF  [0402_CC]
C903  10uF  [0603_CC]
C904  0.1uF  [0402_CC]
C905  18PF  [0402_CC]
D901  RB521S30T1G  [sod_523]
J901  FPC05050-08100  [con50_fpc_0p5_ra_smt_2sh]
L901  470 Ohm  [IND0603_CC]
L902  470 Ohm  [IND0603_CC]
L903  120 Ohm  [0402_CC]
L904  120 Ohm  [0402_CC]
L905  120 Ohm  [0402_CC]
Q901  IRLML6401  [sot-23]
R901  0  [0603_CC]
R903  0  [0402_CC]
R904  0  [0402_CC]
R905  0  [0402_CC]
R906  0  [0402_CC]
R907  0  [0402_CC]
R908  0  [0402_CC]
R910  0  [0402_CC]
R911  0  [0402_CC]
R912  0  [0402_CC]
R913  100K  [0402_CC]
R914  10K  [0402_CC]
R917  0  [0402_CC]
R919  0  [0402_CC]
R920  0  [0402_CC]
R921  0  [0402_CC]
R922  0  [0402_CC]
R923  0  [0402_CC]
R924  0  [0402_CC]
R925  0  [0402_CC]
R926  0  [0402_CC]
R927  0  [0402_CC]
R928  0  [0402_CC]
R929  0  [0402_CC]
R930  0  [0402_CC]
R931  0  [0402_CC]
R932  0  [0402_CC]
R933  0  [0402_CC]
R934  0  [0402_CC]
R935  0  [0402_CC]
R936  0  [0402_CC]
R937  0  [0402_CC]
R938  0  [0402_CC]
R939  0  [0402_CC]
R940  0  [0402_CC]
R941  0  [0402_CC]
R942  0  [0402_CC]
R943  0  [0402_CC]
R944  0  [0402_CC]
R945  0  [0402_CC]
R946  0  [0402_CC]
sheet M-02 HDMI
C1001  0.1uF  [0402_CC]
C1002  0.1uF  [0402_CC]
C1003  0.1uF  [0402_CC]
C1004  0.1uF  [0402_CC]
C1005  0.1uF  [0402_CC]
C1006  0.1uF  [0402_CC]
C1007  0.1uF  [0402_CC]
C1008  0.1uF  [0402_CC]
C1009  0.1uF  [0402_CC]
C1010  0.1uF  [0402_CC]
C1011  0.1uF  [0402_CC]
C1012  10uF  [0603_CC]
C1013  0.1uF  [0402_CC]
C1014  4.7uF  [0402_CC]
C1015  0.1uF  [0402_CC]
C1016  4.7uF  [0402_CC]
C1017  0.1uF  [0402_CC]
D1001  RB521S30T1G  [sod_523]
D1002  RB521S30T1G  [sod_523]
J1001  CON HDMI 1X19  [con_ra_hdmi_19p_0p5_sm]
L1001  90OHM  [ind4_choke_0805]
L1002  90OHM  [ind4_choke_0805]
L1003  90OHM  [ind4_choke_0805]
L1004  90OHM  [ind4_choke_0805]
R1001  0  [0402_CC]
R1002  0  [0402_CC]
R1003  0  [0402_CC]
R1004  4.7K  [0402_CC]
R1005  0  [0402_CC]
R1006  4.7K  [0402_CC]
R1007  0  [0402_CC]
R1008  0  [0402_CC]
R1009  0  [0402_CC]
R1010  0  [0402_CC]
R1011  0  [0402_CC]
R1012  4.7K  [0402_CC]
R1013  4.7K  [0402_CC]
R1014  0  [0402_CC]
R1015  4.3K  [0402_CC]
R1016  10K  [0402_CC]
R1017  0  [0402_CC]
R1018  0  [0402_CC]
R1019  2.2K  [0402_CC]
R1020  2.2K  [0402_CC]
R1021  51.1K  [0402_CC]
R1022  10K  [0402_CC]
R1023  0  [0402_CC]
R1024  0  [0402_CC]
R1025  10K  [0402_CC]
R1026  0  [0603_CC]
R2106  0  [0805_CC]
TP1001  TP_35MIL  [testpoint_35mil]
TVS1001  ESD5B5.0ST1G  [diode2_sod523]
TVS1002  ESD5B5.0ST1G  [diode2_sod523]
TVS1003  ESD5B5.0ST1G  [diode2_sod523]
TVS1004  ESD5B5.0ST1G  [diode2_sod523]
TVS1005  ESD5B5.0ST1G  [diode2_sod523]
U1001  SiI9022A  [qfn72_0p5_10x10_4p85sq]
U1002  SRV05-4  [SOT23_S6]
U1003  SRV05-4  [SOT23_S6]
U1004  RT9169-12GVL  [sot23-3-1p95]
sheet M-04 CAN BUS
C1201  0.1uF  [0402_CC]
C1202  1.0UF  [0402_cc]
C1203  1.0UF  [0402_cc]
C1204  56PF  [0402_cc]
C1205  0.01UF  [0402_CC]
C1206  56PF  [0402_cc]
C1207  1.0UF  [0402_cc]
C1208  0.1uF  [0402_CC]
C1209  1.0UF  [0402_cc]
C1210  56PF  [0402_cc]
C1211  0.01UF  [0402_CC]
C1212  56PF  [0402_cc]
J1201  CON_8P  [con_w2b_8m_1p25_sm_ra]
L1201  100 uH  [ind_1812_4p]
L1202  100 uH  [ind_1812_4p]
R1201  0  [0402_CC]
R1202  0  [0402_CC]
R1203  0  [0402_CC]
R1204  62.0  [0805_CC]
R1205  62.0  [0805_CC]
R1206  0  [0402_CC]
R1207  10K  [0402_CC]
R1208  0  [0402_CC]
R1209  62.0  [0805_CC]
R1210  62.0  [0805_CC]
R1211  0  [0402_CC]
TVS1201  ESD5B5.0ST1G  [diode2_sod523]
U1201  MC34901WEF  [SO8_1P27_4X5]
U1202  MC34901WEF  [SO8_1P27_4X5]
U1203  SRV05-4  [SOT23_S6]
sheet M-05 Sensor
C1301  4.7uF  [0402_CC]
C1302  0.1uF  [0402_CC]
C1303  0.1uF  [0402_CC]
C1305  4.7uF  [0402_CC]
C1306  0.1uF  [0402_CC]
C1307  0.1uF  [0402_CC]
C1308  0.1uF  [0402_CC]
C1309  0.1uF  [0402_CC]
C1310  4.7uF  [0402_CC]
C1311  0.1uF  [0402_CC]
C1312  0.1uF  [0402_CC]
C1313  0.1uF  [0402_CC]
C1314  0.1uF  [0402_CC]
C1315  0.1uF  [0402_CC]
R1301  0  [0402_CC]
R1302  10K  [0402_CC]
R1303  100K  [0402_CC]
R1304  10K  [0402_CC]
R1305  100K  [0402_CC]
R1306  10K  [0402_CC]
R1307  10K  [0402_CC]
TP1301  TPAD_020  [tpad_020]
TP1302  TPAD_020  [tpad_020]
TP1303  TPAD_020  [tpad_020]
U1301  FXLS8471Q  [QFN5X3_0P5_3X3]
U1302  MAG3110  [DFN_10_0P4_2X2_B]
U1303  FXAS21002CQ  [QFN24_0P5_4X4_ASYM_EXP]
sheet M-06 Audio
C1401  10uF  [0603_CC]
C1402  0.1uF  [0402_CC]
C1403  0.1uF  [0402_CC]
C1404  4.7uF  [0402_CC]
C1405  10uF  [0603_CC]
C1406  10uF  [0603_CC]
C1407  0.1uF  [0402_CC]
C1408  0.1uF  [0402_CC]
C1409  4.7uF  [0402_CC]
C1410  220PF  [0402_CC]
C1411  22UF  [0603_CC]
C1412  22UF  [0603_CC]
C1413  220PF  [0402_CC]
C1414  4.7uF  [0402_CC]
C1415  0.1uF  [0402_CC]
C1416  15PF  [0402_CC]
C1417  4.7uF  [0402_CC]
C1418  0.1uF  [0402_CC]
C1419  15PF  [0402_CC]
C1420  0.1uF  [0402_CC]
C1421  0.1uF  [0402_CC]
C1422  4.7uF  [0402_CC]
C1423  0.1uF  [0402_CC]
C1424  0.1uF  [0402_CC]
C1425  15PF  [0402_CC]
C1426  15PF  [0402_CC]
C1427  15PF  [0402_CC]
C1428  15PF  [0402_CC]
C1429  15PF  [0402_CC]
C1430  15PF  [0402_CC]
C1431  15PF  [0402_CC]
C1432  15PF  [0402_CC]
C1433  15PF  [0402_CC]
C1434  15PF  [0402_CC]
C1435  15PF  [0402_CC]
C1436  15PF  [0402_CC]
C1437  15PF  [0402_CC]
C1438  15PF  [0402_CC]
J1401  PJ31360-I  [con6_audjack_ra_th]
J1402  WF1250201200  [con1x2_1p25_sm]
J1403  WF1250201200  [con1x2_1p25_sm]
L1401  120 Ohm  [0402_CC]
L1402  120 Ohm  [0402_CC]
L1403  120OHM  [0603_CC]
P1401  EM6022P  [mic_WM-63PR]
R1402  100K  [0402_CC]
R1404  0  [0402_CC]
R1405  0  [0603_CC]
R1406  10K  [0402_CC]
R1407  0  [0402_CC]
R1410  10K  [0402_CC]
R1411  0  [0402_CC]
R1412  0  [0402_CC]
R1413  0  [0402_CC]
R1414  1K  [0402_CC]
R1415  1K  [0402_CC]
R1416  1K  [0402_CC]
R1417  0  [0402_CC]
R1418  10K  [0402_CC]
R1419  1K  [0402_CC]
R1420  0  [0402_CC]
R1421  1K  [0402_CC]
R1422  1K  [0402_CC]
R1423  0  [0402_CC]
R1424  0  [0402_CC]
R1425  0  [0402_CC]
R1426  0  [0402_CC]
R1427  0  [0402_CC]
R1428  0  [0402_CC]
R1429  0  [0402_CC]
R1430  0  [0402_CC]
R1431  0  [0402_CC]
R1432  0  [0402_CC]
R1433  0  [0402_CC]
R1434  0  [0402_CC]
R1435  0  [0402_CC]
R1436  0  [0402_CC]
TVS1401  ESD5B5.0ST1G  [diode2_sod523]
TVS1402  ESD5B5.0ST1G  [diode2_sod523]
TVS1403  ESD5B5.0ST1G  [diode2_sod523]
TVS1404  ESD5B5.0ST1G  [diode2_sod523]
U1401  WM8960  [qfn32_s142ep]

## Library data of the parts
C901 C903 C1401 C1405 C1406 = CAP_NP: CAP CER 10UF 10V 20% X5R 0603; AGILE_PN: 150-78609; CAD_APPROVED: Yes; FPLIST: CC0603_OV,CC0603,0603_CC; HEIGHT: 1.016MM; MFG_NAME01: TAIYO YUDEN; MFG_PN01: LMK107BJ106MALTD; ROHS: Yes; VOLTAGE: 10V
C902 C904 C1001-C1011 C1013 C1015 C1017 C1201 C1208 C1302 C1303 C1306-C1309 C1311-C1315 C1402 C1403 C1407 C1408 C1415 C1418 C1420 C1421 C1423 C1424 = CAP_NP: CAP CER 0.1UF 25V 10% X5R 0402; AGILE_PN: 150-78633; CAD_APPROVED: Yes; FPLIST: CC0402_25,CC0402_HD,0402_CC; HEIGHT: 0.55MM; MFG_NAME01: YAGEO AMERICA; MFG_PN01: CC0402KRX5R8BB104; ROHS: Yes; Tolerance: 10%; VOLTAGE: 25V
C905 = CAP_NP: CAP CER 18PF 50V 1% C0G 0402; AGILE_PN: 150-76630; ASSY_OPT: DNP; CAD_APPROVED: Yes; FPLIST: CC0402_25,CC0402_HD,0402_CC; HEIGHT: 0.59MM; MFG_NAME01: YAGEO; MFG_PN01: CC0402FRNPO9BN180; PRIORITY_PN: 021-00248; ROHS: Yes; ROOM: ATLAS-AP; Tolerance: 1%; VOLTAGE: 50V
D901 = DIODE_SCHTKY: DIODE SCH 200MA 30V AEC-Q101 SOD-523; AGILE_PN: 480-78501; CAD_APPROVED: Yes; HEIGHT: 0.7MM; MFG_NAME01: On Semiconductor; ROHS: Yes
J901 = CONN_1X50_2SH: CON 1X50 FPC/FFC RA SKT SMT 0.5MM SP 87H SN/AU; AGILE_PN: 211-79710; CAD_APPROVED: Yes; FPLIST: con50_fpc_0p5_ra_smt,con50_fpc_0p5_ra_smt_2sh; HEIGHT: 2.2MM; MFG_NAME01: SHENZHEN ATOM TECHNOLOGY CO.,LTD; ROHS: Yes
L901 L902 = INDUCTOR_FERRITE: IND FER BEAD 470 OHM@100MHZ 1A 25% 0603; AGILE_PN: 180-77776; CAD_APPROVED: Yes; FPLIST: IND_0603,IND0603_CC; HEIGHT: 0.95MM; MFG_NAME01: murata; MFG_PN01: BLM18PG471SN1D; PART_TYPE: FERRITE\BEAD; ROHS: Yes; Tolerance: 25%
L903-L905 L1401 L1402 = INDUCTOR_FERRITE: IND FER BEAD 120 OHM@100MHZ 0.5A 25% 0402; AGILE_PN: 180-77771; CAD_APPROVED: Yes; FPLIST: IND_0402,0402_CC; HEIGHT: 0.55MM; MFG_NAME01: Murata; MFG_PN01: BLM15AG121SN1D; PART_TYPE: FERRITE\BEAD; ROHS: Yes; Tolerance: 25%
Q901 = MOSFET_P: TRAN PMOS PWR 12V 4.3A SOT23; AGILE_PN: 480-77718; CAD_APPROVED: Yes; HEIGHT: 1.12MM; MFG_NAME01: INTERNATIONAL RECTIFIER; MFG_PN01: IRLML6401TRPBF; ROHS: Yes
R901 = RES: RES MF ZERO OHM 1/10W -- 0603; AGILE_PN: 470-80866; ASSY_OPT: DNP; CAD_APPROVED: Yes; FPLIST: RC0603_OV,RC0603,R603-X2,0603_CC; HEIGHT: 0.6MM; MFG_NAME01: BOURNS; MFG_PN01: CR0603J/000ELF; ROHS: Yes
R903-R906 R912 R917 R919-R946 R1001 R1008 R1017 R1018 R1024 R1201-R1203 R1206 R1208 R1211 R1301 R1404 R1407 R1411-R1413 R1417 R1420 R1423-R1435 = RES: RES MF ZERO OHM 1/16W 5% 0402; AGILE_PN: 470-75394; CAD_APPROVED: Yes; FPLIST: RC0402_25,RC0402_HD,RC0402_X2,0402_CC; HEIGHT: 0.45 MM; MFG_NAME01: ROHM; MFG_PN01: MCR01MZPJ000; ROHS: Yes; Tolerance: 5%
R907 R908 R910 R911 R1002 R1003 R1005 R1007 R1009-R1011 R1014 R1023 R1436 = RES: RES MF ZERO OHM 1/16W 5% 0402; AGILE_PN: 470-75394; ASSY_OPT: DNP; CAD_APPROVED: Yes; FPLIST: RC0402_25,RC0402_HD,RC0402_X2,0402_CC; HEIGHT: 0.45 MM; MFG_NAME01: ROHM; MFG_PN01: MCR01MZPJ000; ROHS: Yes; Tolerance: 5%
R913 R1303 R1305 R1402 = RES: RES MF 100K 1/16W 5% 0402; AGILE_PN: 470-75597; CAD_APPROVED: Yes; FPLIST: RC0402_25,RC0402_HD,0402_CC; HEIGHT: 0.40 MM; MFG_NAME01: KOA SPEER; MFG_PN01: RK73B1ETTP104J; ROHS: Yes; Tolerance: 5%
R914 R1016 R1025 R1207 R1304 R1306 R1307 R1406 R1410 = RES: RES MF 10K 1/16W 5% 0402; AGILE_PN: 470-75557; CAD_APPROVED: Yes; FPLIST: RC0402_25,RC0402_HD,0402_CC; HEIGHT: 0.4 MM; MFG_NAME01: VISHAY INTERTECHNOLOGY; MFG_PN01: CRCW040210K0JNED; ROHS: Yes; Tolerance: 5%
C1012 = CAP_NP: CAP CER 10UF 10V 20% X5R 0603; AGILE_PN: 150-78609; ASSY_OPT: DNP; CAD_APPROVED: Yes; FPLIST: CC0603_OV,CC0603,0603_CC; HEIGHT: 1.016MM; MFG_NAME01: TAIYO YUDEN; MFG_PN01: LMK107BJ106MALTD; ROHS: Yes; VOLTAGE: 10V
C1014 C1016 C1301 C1305 C1310 C1404 C1409 C1414 C1417 C1422 = CAP_NP: CAP CER 4.7UF 6.3V 20% X5R 0402; AGILE_PN: 150-78463; CAD_APPROVED: Yes; FPLIST: CC0402_25,CC0402_HD,0402_CC; HEIGHT: 0.65MM; MFG_NAME01: TDK; MFG_PN01: C1005X5R0J475M050BC; ROHS: Yes; Tolerance: 20%; VOLTAGE: 6.3V; voltage rating: 6.3V
D1001 D1002 = DIODE_SCHTKY: DIODE SCH 200MA 30V AEC-Q101 SOD-523; AGILE_PN: 480-78501; ASSY_OPT: DNP; CAD_APPROVED: Yes; HEIGHT: 0.7MM; MFG_NAME01: On Semiconductor; ROHS: Yes
J1001 = ATOM010130010052_HDMI_19P: CON 1X19 HDMI SMT 0.5MM 249H AU --; AGILE_PN: 211-79674; ASSY_OPT: DNP; CAD_APPROVED: Yes; HEIGHT: 6.33MM; MFG_NAME01: SHENZHEN ATOM TECHNOLOGY CO.,LTD; MFG_PN01: HD119F-3A04202; ROHS: Yes
L1001-L1004 = DLW43: IND CHK 90 OHM@100MHZ 330MA 25% 0805; AGILE_PN: 180-76336; ASSY_OPT: DNP; CAD_APPROVED: Yes; HEIGHT: 1MM; MFG_NAME01: MURATA; MFG_PN01: DLW21HN900SQ2L; PART_TYPE: CHOKE; ROHS: Yes; Tolerance: 25%
R1004 R1012 = RES: RES MF 4.7K 1/16W 5% 0402; AGILE_PN: 470-75626; ASSY_OPT: DNP; CAD_APPROVED: Yes; FPLIST: RC0402_25,RC0402_HD,0402_CC; HEIGHT: 0.41mm; MFG_NAME01: KOA SPEER; MFG_PN01: RK73B1ETTP472J; ROHS: Yes; Tolerance: 5%
R1006 R1013 = RES: RES MF 4.7K 1/16W 5% 0402; AGILE_PN: 470-75626; CAD_APPROVED: Yes; FPLIST: RC0402_25,RC0402_HD,0402_CC; HEIGHT: 0.41mm; MFG_NAME01: KOA SPEER; MFG_PN01: RK73B1ETTP472J; ROHS: Yes; Tolerance: 5%
R1015 = RES: RES MF 4.3K  1/16W 1% 0402; AGILE_PN: 470-30905; CAD_APPROVED: Yes; FPLIST: RC0402_25,RC0402_HD,0402_CC; HEIGHT: 0.40 MM; MFG_NAME01: KOA SPEER; MFG_PN01: RK73H1ETTP4301F; ROHS: Yes; Tolerance: 1%
R1019 R1020 = RES: RES MF 2.2K 1/16W 5% 0402; AGILE_PN: 470-75636; CAD_APPROVED: Yes; FPLIST: RC0402_25,RC0402_HD,0402_CC; HEIGHT: 0.4 MM; MFG_NAME01: VENKEL COMPANY; MFG_PN01: CR0402-16W-222JT; ROHS: Yes; Tolerance: 5%
R1021 = RES: RES MF 51.1K  1/16W 1% 0402; AGILE_PN: 470-31028; CAD_APPROVED: Yes; FPLIST: RC0402_25,RC0402_HD,0402_CC; HEIGHT: 0.40 MM; MFG_NAME01: KOA SPEER; MFG_PN01: RK73H1ETTP5112F; ROHS: Yes; Tolerance: 1%
R1022 R1302 = RES: RES MF 10K 1/16W 5% 0402; AGILE_PN: 470-75557; ASSY_OPT: DNP; CAD_APPROVED: Yes; FPLIST: RC0402_25,RC0402_HD,0402_CC; HEIGHT: 0.4 MM; MFG_NAME01: VISHAY INTERTECHNOLOGY; MFG_PN01: CRCW040210K0JNED; ROHS: Yes; Tolerance: 5%
R1026 R1405 = RES: RES MF ZERO OHM 1/10W -- 0603; AGILE_PN: 470-80866; CAD_APPROVED: Yes; FPLIST: RC0603_OV,RC0603,R603-X2,0603_CC; HEIGHT: 0.6MM; MFG_NAME01: BOURNS; MFG_PN01: CR0603J/000ELF; ROHS: Yes
R2106 = RES: RES MF ZERO OHM 1/8W -- 0805; AGILE_PN: 470-75442; CAD_APPROVED: Yes; FPLIST: RC0805_OV,RC0805,RC0805_OV_3P,0805_CC; HEIGHT: 0.7 MM; MFG_NAME01: YAGEO AMERICA; MFG_PN01: RC0805JR-070RL; ROHS: Yes; Tolerance: 5%
TP1001 = T_POINT_R: TEST POINT PAD .035 SMT, no part to order; AGILE_PN: 510-75618; CAD_APPROVED: Yes; HEIGHT: 0.1MM; ROHS: Yes
TVS1001-TVS1005 = DIODE_TVS_BIDIR: DIODE SUPPRESSOR 16A@30NS 5V@1UA SOD-523; AGILE_PN: 480-76937; ASSY_OPT: DNP; CAD_APPROVED: Yes; HEIGHT: 0.7MM; MFG_NAME01: on semiconductor; ROHS: Yes
U1001 = SiI9022A: IC XMTR HDMI 165MHZ 1.8/3.3V QFN72; AGILE_PN: 312-79886; ASSY_OPT: DNP; CAD_APPROVED: Yes; HEIGHT: 0.9MM; MFG_NAME01: SILICON IMAGE; MFG_PN01: SiI9022ACNU; ROHS: Yes
U1002 U1003 = SRV05-4: DIODE TVS ARRAY 12A 5V 300W SOT23_S6; AGILE_PN: 480-75205; ASSY_OPT: DNP; CAD_APPROVED: Yes; HEIGHT: 1.45mm; MFG_NAME01: SEMTECH CORP; MFG_PN01: SRV05-4.TCT; ROHS: Yes
U1004 = RT9169_3P: IC VREG LDO 1.2V 100mA 2-6V SOT23-3; AGILE_PN: 315-80512; ASSY_OPT: DNP; CAD_APPROVED: Yes; HEIGHT: 1.295 MM; MFG_NAME01: Richtek; ROHS: Yes
C1202 C1203 C1207 C1209 = CAP_NP: CAP CER 1.0UF 10V 10% X5R 0402; AGILE_PN: 150-75772; CAD_APPROVED: Yes; FPLIST: CC0402_25,CC0402_HD,0402_CC; HEIGHT: 0.6MM; MFG_NAME01: YAGEO AMERICA; MFG_PN01: CC0402KRX5R6BB105; ROHS: Yes; VOLTAGE: 10V
C1204 C1206 C1210 C1212 = CAP_NP: CAP CER 56PF 50V 5% C0G 0402; AGILE_PN: 150-30269; CAD_APPROVED: Yes; FPLIST: CC0402_25,CC0402_HD,0402_CC; HEIGHT: 0.55 MM; MFG_NAME01: VENKEL COMPANY; MFG_PN01: C0402C0G500-560JNE; ROHS: Yes; Tolerance: 5%; VOLTAGE: 50V
C1205 C1211 = CAP_NP: CAP CER 0.01UF 50V 10% X7R 0402; AGILE_PN: 150-30114; ASSY_OPT: DNP; CAD_APPROVED: Yes; FPLIST: CC0402_25,CC0402_HD,0402_CC; HEIGHT: 0.74 MM; MFG_NAME01: WALSIN TECHNOLOGY CORP.; MFG_PN01: 0402B103K500CT; ROHS: Yes; Tolerance: 10%; VOLTAGE: 50V
J1201 = CON_W2B_8P: CON 8 PLUG RA SHRD SMT 1.25MM SP 142H AU; AGILE_PN: 211-79668; CAD_APPROVED: Yes; HEIGHT: 3.45MM; MFG_NAME01: SHENZHEN ATOM TECHNOLOGY CO.,LTD; MFG_PN01: WF1250801200; ROHS: Yes
L1201 L1202 = DATA_CHOKE: IND CHK 100uH 150mA -30/+50% AEC-Q200 1812; AGILE_PN: 180-78098; ASSY_OPT: DNP; CAD_APPROVED: Yes; HEIGHT: 3MM; MFG_NAME01: Epcos; MFG_PN01: B82789C0104N002; PART_TYPE: CHOKE; ROHS: Yes; Tolerance: -30/+50%
R1204 R1205 R1209 R1210 = RES: RES MF 62.0 OHM 1/8W 1% 0805; AGILE_PN: 470-78674; CAD_APPROVED: Yes; FPLIST: RC0805_OV,RC0805,0805_CC; HEIGHT: 0.6 MM; MFG_NAME01: KOA SPEER; MFG_PN01: RK73H2ATTD62R0F; ROHS: Yes; Tolerance: 1%
TVS1201 TVS1401-TVS1404 = DIODE_TVS_BIDIR: DIODE SUPPRESSOR 16A@30NS 5V@1UA SOD-523; AGILE_PN: 480-76937; CAD_APPROVED: Yes; HEIGHT: 0.7MM; MFG_NAME01: on semiconductor; ROHS: Yes
U1201 U1202 = MC33901WEF-8P: IC XCVR CAN HS 60KB/S-1MB/S WKUP 4.5-5.5V SOIC8; AGILE_PN: 312-80948; CAD_APPROVED: Yes; HEIGHT: 1.75MM; MFG_NAME01: FREESCALE SEMICONDUCTOR; ROHS: Yes
U1203 = SRV05-4: DIODE TVS ARRAY 12A 5V 300W SOT23_S6; AGILE_PN: 480-75205; CAD_APPROVED: Yes; HEIGHT: 1.45mm; MFG_NAME01: SEMTECH CORP; MFG_PN01: SRV05-4.TCT; ROHS: Yes
TP1301-TP1303 = TestLoop: TEST POINT PAD 0.5MM DIA SMT, NO PART TO ORDER; AGILE_PN: 211-77484; CAD_APPROVED: Yes; HEIGHT: 0.1MM; ROHS: Yes
U1301 = FXLS8471Q_16P: IC 3-AXIS LIN ACCELEROMETER 14BIT 1.95-3.6V QFN16; AGILE_PN: 315-79718; CAD_APPROVED: Yes; HEIGHT: 1 MM; MFG_NAME01: FREESCALE SEMICONDUCTOR; MFG_PN01: FXLS8471QR1; ROHS: Yes
U1302 = MAG3112_DFN_10P: IC 3-AXIS DIGITAL MAGNETOMETER 1.95-3.6V DFN10; AGILE_PN: 312-79970; CAD_APPROVED: Yes; FPLIST: DFN_10_0P4_2X2_B,DFN_10_0P4_2X2_A,dfn_10_0p4_2x2_a_nsp; HEIGHT: 0.9MM; MFG_NAME01: FREESCALE SEMICONDUCTOR; MFG_PN01: MAG3110FC; ROHS: Yes
U1303 = FXAS21002CQ_QFN_24P: IC XTRINSIC 3-AXIS DIGITAL GYROSCOPE 1.95-3.6V QFN24; AGILE_PN: 312-81029; ASSY_OPT: DNP; CAD_APPROVED: Yes; HEIGHT: 1.1 MM; MFG_NAME01: FREESCALE SEMICONDUCTOR; ROHS: Yes
C1410 C1413 = CAP_NP: CAP CER 220PF 50V 5% C0G 0402; AGILE_PN: 150-30297; CAD_APPROVED: Yes; FPLIST: CC0402_25,CC0402_HD,0402_CC; HEIGHT: 0.55MM; MFG_NAME01: KEMET; MFG_PN01: C0402C221J5GAC; ROHS: Yes; Tolerance: 5%; VOLTAGE: 50V
C1411 C1412 = CAP_NP: CAP CER 22UF 6.3V 20% X5R 0603; AGILE_PN: 150-78467; CAD_APPROVED: Yes; FPLIST: CC0603_OV,CC0603,0603_CC; HEIGHT: 1MM; MFG_NAME01: Samsung; MFG_PN01: CL10A226MQ8NRNE; ROHS: Yes; Tolerance: 20%; VOLTAGE: 6.3V; voltage rating: 6.3V
C1416 C1419 C1425-C1428 = CAP_NP: CAP CER 15PF 16V 5% C0G 0402; AGILE_PN: 150-75720; CAD_APPROVED: Yes; FPLIST: CC0402_25,CC0402_HD,0402_CC; HEIGHT: 0.55MM; MFG_NAME01: KEMET; MFG_PN01: C0402C150J4GAC; ROHS: Yes; Tolerance: 5%; VOLTAGE: 16V
C1429-C1438 = CAP_NP: CAP CER 15PF 16V 5% C0G 0402; AGILE_PN: 150-75720; ASSY_OPT: DNP; CAD_APPROVED: Yes; FPLIST: CC0402_25,CC0402_HD,0402_CC; HEIGHT: 0.55MM; MFG_NAME01: KEMET; MFG_PN01: C0402C150J4GAC; ROHS: Yes; Tolerance: 5%; VOLTAGE: 16V
J1401 = CONN_AUDIOJACK_6P: CON 6 AUD JACK RA SMT -- 191H AU; AGILE_PN: 211-79704; CAD_APPROVED: Yes; HEIGHT: 4.85 MM; MFG_NAME01: SHENZHEN ATOM TECHNOLOGY CO.,LTD; ROHS: Yes
J1402 J1403 = CON1X2_TAB: CON 2 PLUG RA SHRD SMT 1.25MM SP 142H --; AGILE_PN: 211-79678; CAD_APPROVED: Yes; HEIGHT: 3.6MM; MFG_NAME01: SHENZHEN ATOM TECHNOLOGY CO.,LTD; ROHS: Yes
L1403 = BEAD_0: IND FER BEAD 120OHM@100MHZ 2A 25% 0603; AGILE_PN: 180-30008; CAD_APPROVED: Yes; FPLIST: IND_0603,0603_CC; HEIGHT: 0.95MM; MFG_NAME01: MURATA; MFG_PN01: BLM18PG121SH1; PART_TYPE: FERRITE; ROHS: Yes; Tolerance: 25%
P1401 = MIC_POM: AUDIO DEVICE MIC 0.5MA 2V 38-48+/-3dB 2.2KOHM 6MM TH; AGILE_PN: 510-77987; CAD_APPROVED: Yes; HEIGHT: 2.4MM; MFG_NAME01: Soberton Inc; ROHS: Yes
R1414-R1416 R1419 R1421 R1422 = RES: RES MF 1.0K 1/16W 5% 0402; AGILE_PN: 470-75555; CAD_APPROVED: Yes; FPLIST: RC0402_25,RC0402_HD,RC0402_X2,0402_CC; HEIGHT: 0.41mm; MFG_NAME01: VISHAY INTERTECHNOLOGY; MFG_PN01: CRCW04021K00JNED; ROHS: Yes; Tolerance: 5%
R1418 = RES: RES MF 10K 1/16W 5% 0402; AGILE_PN: 470-75557; ASSY_OPT: DNP; CAD_APPROVED: Yes; FPLIST: RC0402_25,RC0402_HD,0402_CC; HEIGHT: 0.4 MM; MFG_NAME01: VISHAY INTERTECHNOLOGY; MFG_PN01: CRCW040210K0JNED; ROHS: Yes; TOL: 5%; Tolerance: 5%
U1401 = WM8960_QFN_33P: IC CODEC STEREO WITH CLASS D SPEAKER DRIVER 1.71-3.6V QFN32; AGILE_PN: 315-79450; CAD_APPROVED: Yes; HEIGHT: 1MM; MFG_NAME01: WOLFSON MICROELECTRONICS; MFG_PN01: WM8960CGEFL/RV; ROHS: Yes

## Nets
GND: C901.2 C902.2 C903.2 C904.2 C905.2 C1001.2 C1002.2 C1003.2 C1004.2 C1005.2 C1006.2 C1007.2 C1008.2 C1009.2 C1010.2 C1011.2 C1012.2 C1013.2 C1014.2 C1015.2 C1016.2 C1017.2 C1201.2 C1202.2 C1203.2 C1204.1 C1205.2 C1206.2 C1207.2 C1208.2 C1209.2 C1210.1 C1211.2 C1212.2 C1301.2 C1302.2 C1303.2 C1305.2 C1306.2 C1307.2 C1308.2 C1309.2 C1310.2 C1311.2 C1312.2 C1313.2 C1314.2 C1315.1 C1401.2 C1402.2 C1403.2 C1404.2 C1405.2 C1406.2 C1407.2 C1408.2 C1409.2 C1410.1 C1413.2 C1414.2 C1415.2 C1416.1 C1417.2 C1418.2 C1419.1 C1425.2 C1426.2 C1427.2 C1428.2 C1429.1 C1430.1 C1431.1 C1432.1 C1435.2 C1436.2 C1437.2 C1438.2 J901.9 J901.18 J901.27 J901.31 J901.33 J901.44 J901.S1 J901.S2 J1001.2(D2GND) J1001.5(D1GND) J1001.8(D0GND) J1001.11(CKGND) J1001.17(DDCGND) J1201.2 J1201.5 J1201.8 J1201.9 J1201.10 J1401.1 J1402.3 J1402.4 J1403.3 J1403.4 R914.2 R1013.2 R1015.2 R1018.2 R1025.2 R1303.2 R1406.1 R1410.2 R1422.1 R2106.2 TVS1001.1(A1) TVS1002.1(A1) TVS1003.1(A1) TVS1004.1(A1) TVS1005.1(A1) TVS1201.1(A1) TVS1401.1(A1) TVS1402.1(A1) TVS1403.1(A1) TVS1404.1(A1) U1001.37(SD3) U1001.38(MCLK) U1001.39(SD2) U1001.40(SD1) U1001.41(SD0) U1001.43(CGND) U1001.44(WS) U1001.45(SCK) U1001.55(RSVDL) U1001.57(IOGND) U1001.63(AGND) U1001.70(VDDQ) U1001.73(EPAD) U1002.2(GND) U1003.2(GND) U1004.1(GND) U1201.2(GND) U1202.2(GND) U1203.2(GND) U1301.3(RSRV) U1301.5(GND1) U1301.7(SA0/MISO) U1301.10(SA1/~{CS}) U1301.12(GND2) U1301.13(RSRV) U1301.16(RST) U1302.5(GND1) U1302.10(GND2) U1303.1(GND1) U1303.5(GND2) U1303.6(RSVD1) U1303.7(RSVD2) U1303.8(~{I2C}/SPI) U1303.9(RSVD3) U1303.10(RSVD4) U1303.13(SA0/MISO) U1303.14(GND3) U1303.19(GND4) U1303.20(RSVD5) U1303.21(RSVD6) U1303.22(RSVD7) U1303.23(RSVD8) U1303.24(RSVD9) U1401.9(DGND) U1401.20(SPKGND2) U1401.24(SPKGND1) U1401.28(AGND) U1401.33(GND_PADDLE) ; also on sheet 3 4 13 14 15 16 17 18
ACC_INT: R1302.2 U1301.11(INT1) ; also on sheet 3
AUD_INT: R1435.1 R1436.1 ; also on sheet 3
BLT_PWM: L903.1 ; also on sheet 3
CAN1_2_STBY: R1207.2 U1201.8(STB) U1202.8(STB) ; also on sheet 3
CAN1_H: C1204.2 J1201.4 L1201.4(OUT2) R1203.2 R1204.1 U1203.1(I/O1)
CAN1_L: C1206.1 J1201.3 L1201.2(IN2) R1205.2 R1206.2 U1203.3(I/O3)
CAN1_RX: U1201.4(RXD) ; also on sheet 3
CAN1_TX: U1201.1(TXD) ; also on sheet 3
CAN1H: L1201.3(OUT1) R1203.1 U1201.7(CANH)
CAN1L: L1201.1(IN1) R1206.1 U1201.6(CANL)
CAN2_H: C1210.2 J1201.7 L1202.4(OUT2) R1208.2 R1209.1 U1203.6(I/O6)
CAN2_L: C1212.1 J1201.6 L1202.2(IN2) R1210.2 R1211.2 U1203.4(I/O4)
CAN2_RX: U1202.4(RXD) ; also on sheet 3
CAN2_TX: U1202.1(TXD) ; also on sheet 3
CAN2H: L1202.3(OUT1) R1208.1 U1202.7(CANH)
CAN2L: L1202.1(IN1) R1211.1 U1202.6(CANL)
CAN_VDD_5V: C1201.1 C1203.1 C1208.1 C1209.1 R1201.2 U1201.3(VDD) U1202.3(VDD)
CAN_VIO_3V3: C1202.1 C1207.1 R1202.1 R1207.1 U1201.5(VIO) U1202.5(VIO)
DCDC_3V3: Q901.2(SOURCE) R901.1 R913.1 R1026.1 ; also on sheet 3 4 16 17 18
DCDC_5V: C1012.1 C1013.1 D1001.A R1019.1 R1020.1 R1024.1 R1201.1 ; also on sheet 15 17 18
DDC_SCL: J1001.15(SCL) R1020.2 TVS1003.2(A2) U1001.49(DSCL)
DDC_SDA: J1001.16(SDA) R1019.2 TVS1002.2(A2) U1001.48(DSDA)
ECSPI4_MISO: R910.1 ; also on sheet 3 14 18
ECSPI4_MOSI: R908.1 ; also on sheet 3 14 18
ECSPI4_SCLK: R907.1 ; also on sheet 3 14 18
ECSPI4_SS0: R911.1 ; also on sheet 3 14 18
FSL_GYRO_INT1: TP1302.1(Pin1) U1303.3(INT1)
FSL_GYRO_INT2: TP1303.1(Pin1) U1303.2(INT2/PWR_CTRL)
HDMI_5V: D1001.C J1001.18(+5V) R1024.2 TVS1001.2(A2)
HDMI_CEC_A: J1001.13(CEC) R1021.2 TVS1004.2(A2) U1001.71(CEC_A)
HDMI_CEC_D: R1004.2 U1001.50(CEC_D)
HDMI_CLKN_CN: J1001.12(CK-) L1003.2 R1010.2 U1003.1(I/O1)
HDMI_CLKP_CN: J1001.10(CK+) L1003.3 R1014.2 U1003.3(I/O3)
HDMI_DATAN0_CN: J1001.9(D0-) L1001.2 R1002.2 U1003.6(I/O6)
HDMI_DATAN1_CN: J1001.6(D1-) L1004.2 R1009.2 U1002.6(I/O6)
HDMI_DATAN2_CN: J1001.3(D2-) L1002.2 R1003.2 U1002.1(I/O1)
HDMI_DATAP0_CN: J1001.7(D0+) L1001.3 R1005.2 U1003.4(I/O4)
HDMI_DATAP1_CN: J1001.4(D1+) L1004.3 R1011.2 U1002.4(I/O4)
HDMI_DATAP2_CN: J1001.1(D2+) L1002.3 R1007.2 U1002.3(I/O3)
HDMI_GND_CHASSIS: J1001.G1(GND1) J1001.G2(GND2) J1001.G3(GND3) J1001.G4(GND4) R2106.1
HDMI_HPD: J1001.19(HPD) R1025.1 TVS1005.2(A2) U1001.54(HPD)
HDMI_INT: R1006.2 U1001.52(INT) ; also on sheet 3
HDMI_nRST: R1016.2 U1001.51(~{RESET}) ; also on sheet 3
HP_JD: R1404.1 U1401.7(RINPUT3/JD3)
HP_L: C1411.1 U1401.31(HP_L)
HP_MIC1N: C1419.2 C1421.1 U1401.4(LINPUT1)
HP_MIC1P: C1424.1 C1425.1 U1401.2(LINPUT3/JD2)
HP_R: C1412.1 U1401.29(HP_R)
I2C1_SCL: R1306.2 U1301.4(SCL/SCLK) U1302.7(SCL) U1303.11(SCL/SCLK) ; also on sheet 3
I2C1_SDA: R1307.2 U1301.6(SDA/MOSI) U1302.6(SDA) U1303.12(SDA/MOSI/SPI_DIO) ; also on sheet 3
I2C2_SCL: L904.1 R1008.1 R1411.1 ; also on sheet 3 4 18
I2C2_SDA: L905.1 R1001.1 R1412.1 ; also on sheet 3 4 18
JTAG_nTRST: R1433.1 ; also on sheet 3 16
JTAG_TCK: R1431.1 ; also on sheet 3 16
JTAG_TDI: R1407.1 ; also on sheet 3 16
JTAG_TDO: R1432.1 ; also on sheet 3 16
JTAG_TMS: R1434.1 ; also on sheet 3 16
LCD_DATA0: R919.1 U1001.32(D0) ; also on sheet 3
LCD_DATA1: R920.1 U1001.31(D1) ; also on sheet 3
LCD_DATA2: R921.1 U1001.30(D2) ; also on sheet 3
LCD_DATA3: R922.1 U1001.29(D3) ; also on sheet 3
LCD_DATA4: R923.1 U1001.28(D4) ; also on sheet 3
LCD_DATA5: R924.1 U1001.27(D5) ; also on sheet 3
LCD_DATA6: R925.1 U1001.25(D6) ; also on sheet 3
LCD_DATA7: R926.1 U1001.24(D7) ; also on sheet 3
LCD_DATA8: R927.1 U1001.23(D8) ; also on sheet 3
LCD_DATA9: R928.1 U1001.20(D9) ; also on sheet 3
LCD_DATA10: R929.1 U1001.19(D10) ; also on sheet 3
LCD_DATA11: R930.1 U1001.18(D11) ; also on sheet 3
LCD_DATA12: R931.1 U1001.17(D12) ; also on sheet 3
LCD_DATA13: R932.1 U1001.16(D13) ; also on sheet 3
LCD_DATA14: R933.1 U1001.15(D14) ; also on sheet 3
LCD_DATA15: R934.1 U1001.14(D15) ; also on sheet 3
LCD_DATA16: R935.1 U1001.13(D16) ; also on sheet 3
LCD_DATA17: R936.1 U1001.11(D17) ; also on sheet 3
LCD_DATA18: R937.1 U1001.10(D18) ; also on sheet 3
LCD_DATA19: R938.1 U1001.9(D19) ; also on sheet 3
LCD_DATA20: R939.1 U1001.8(D20) ; also on sheet 3
LCD_DATA21: R940.1 U1001.7(D21) ; also on sheet 3
LCD_DATA22: R941.1 U1001.6(D22) ; also on sheet 3
LCD_DATA23: R942.1 U1001.4(D23) ; also on sheet 3
LCD_DE: R943.1 U1001.33(DE) ; also on sheet 3
LCD_DISP: R917.1 ; also on sheet 3
LCD_HSYNC: R944.1 U1001.34(HSYNC) ; also on sheet 3
LCD_nPWREN: D901.A ; also on sheet 3
LCD_PCLK: R946.1 R1017.1 ; also on sheet 3
LCD_VSYNC: R945.1 U1001.35(VSYNC) ; also on sheet 3
MAG_INT: R1303.1 U1302.9(INT1)
MAIN_MIC2N: C1423.2 C1428.1 U1401.5(RINPUT1)
MAIN_MIC2P: C1416.2 C1420.2 U1401.6(RINPUT2)
MICBIAS: C1404.1 R1413.1 R1414.1 U1401.1(MICBIAS)
SPDIF_TX: R1023.1 ; also on sheet 3
SPK_LN: R1425.1 U1401.23(SPK_LN)
SPK_LP: R1429.1 U1401.25(SPK_LP)
SPK_RN: R1423.1 U1401.19(SPK_RN)
SPK_RP: R1427.1 U1401.22(SPK_RP)
TMDS_TX0_N: L1001.1 R1002.1 U1001.61(TX0-)
TMDS_TX0_P: L1001.4 R1005.1 U1001.62(TX0+)
TMDS_TX1_N: L1004.1 R1009.1 U1001.64(TX1-)
TMDS_TX1_P: L1004.4 R1011.1 U1001.65(TX1+)
TMDS_TX2_N: L1002.1 R1003.1 U1001.67(TX2-)
TMDS_TX2_P: L1002.4 R1007.1 U1001.68(TX2+)
TMDS_TXC_N: L1003.1 R1010.1 U1001.58(TXC-)
TMDS_TXC_P: L1003.4 R1014.1 U1001.59(TXC+)
USB_OTG1_OC: R906.1 ; also on sheet 3 17 18
USB_OTG1_PWR: R903.1 ; also on sheet 3 15 17 18
USB_OTG2_OC: R904.1 ; also on sheet 3 17 18
USB_OTG2_PWR: R905.1 ; also on sheet 3 17 18
VENET_3V3: C1401.1 C1402.1 C1403.1 J1201.1 R1202.2 R1301.1 R1402.1 TVS1201.2(A2) U1401.8(DCVDD) U1401.10(DBVDD) U1401.32(AVDD) ; also on sheet 3 4 13 14 18
VHDMI_3V3: C1003.1 C1004.1 C1005.1 C1014.1 C1015.1 D1002.A R1004.1 R1006.1 R1012.2 R1016.1 R1022.1 R1026.2 U1001.3(IOVCC18_1) U1001.21(IOVCC18_2) U1001.46(IOVCC18_3) U1004.3(VIN)
VLCD_3V3: L901.1 Q901.3(DRAIN) R901.2
VLDO_1V2: C1001.1 C1002.1 C1006.1 C1007.1 C1008.1 C1009.1 C1010.1 C1011.1 C1016.1 C1017.1 TP1001.1(TP) U1001.5(CVCC12_1) U1001.12(CVCC12_2) U1001.26(CVCC12_3) U1001.42(CVCC12_4) U1001.47(CVCC12_5) U1001.53(CVCC12_6) U1001.60(AVCC12_1) U1001.66(AVCC12_2) U1004.2(VOUT)
VSENSOR_3V3: C1301.1 C1302.1 C1303.1 C1305.1 C1306.1 C1307.1 C1310.1 C1311.1 C1312.1 R1301.2 R1302.1 R1304.1 R1305.1 R1306.1 R1307.1 U1301.1(VDDIO) U1301.14(VDD) U1302.2(VDD) U1302.8(VDDIO) U1303.15(VDD) U1303.18(VDDIO)
VSPK_5V: C1405.1 C1406.1 C1407.1 C1408.1 R1405.2 U1401.21(SPKVDD2) U1401.26(SPKVDD1)
VSYS: L902.1 R1405.1 ; also on sheet 3 4 15
xnur: J901.35 R904.2
xpul: J901.34 R903.2
ynlr: J901.37 R906.2
ypll: J901.36 R905.2
N97015722: J1401.4 L1403.2 TVS1404.2(A2)
N97015748: J1401.5 R1402.2 R1404.2 R1436.2 TVS1402.2(A2)
N97015788: C1410.2 J1401.2 L1401.2 TVS1401.2(A2)
N97015810: C1413.1 J1401.3 L1402.2 TVS1403.2(A2)
N97015879: C1411.2 L1401.1 R1406.2
N97015895: C1422.2 R1421.2 R1422.2
N97016058: C1409.1 U1401.27(VMID)
N97016158: C1423.1 R1418.2 R1420.2 R1421.1
N97016160: C1420.1 R1415.2 R1417.2 R1418.1
N97016178: C1414.1 C1415.1 C1422.1 R1414.2 R1415.1
N97016453: C1412.2 L1402.1 R1410.1
N97016636: C1421.2 R1416.2 R1419.1
N97016638: C1424.2 C1426.1 C1427.1 L1403.1 R1419.2
N97016683: C1417.1 C1418.1 R1413.2 R1416.1
N97026671: R1015.1 U1001.56(EXT_SWING)
N97026935: R1008.2 U1001.1(CSCL)
N97026974: R1001.2 U1001.2(CSDA)
N97027063: R1012.1 R1013.1 U1001.72(CI2CA)
N97033876: C1313.1 U1303.16(VREGD)
N97034198: C1314.1 R1304.2 U1303.4(~{RST})
N97034207: R1305.2 U1303.17(~{SPI_CS})
N97034229: C1309.1 U1302.4(CAP_R)
N97034320: C1308.1 U1302.1(CAP_A)
N97122742: C1205.1 R1204.2 R1205.1
N97124588: C1211.1 R1209.2 R1210.1
N97149824: R1022.2 R1023.2 U1001.36(SPDIF)
N97157415: R1018.1 U1001.69(IO_SEL)
N97419423: R1407.2 U1401.12(BCLK)
N97419698: R1412.2 U1401.18(SDIN)
N97419704: R1411.2 U1401.17(SCLK)
N97614525: C1429.2 R1423.2 R1424.1
N97614556: C1435.1 R1427.2 R1428.1
N97614560: C1430.2 C1433.1 J1402.1 R1424.2
N97614565: C1433.2 C1436.1 J1402.2 R1428.2
N97617364: P1401.1(Out) R1417.1
N97617373: P1401.2(GND) R1420.1
N97656955: R1017.2 U1001.22(IDCK)
N97662147: D1002.C R1021.1
N97687801: C1431.2 R1425.2 R1426.1
N97687808: C1437.1 R1429.2 R1430.1
N97687812: C1432.2 C1434.1 J1403.1 R1426.2
N97687814: C1434.2 C1438.1 J1403.2 R1430.2
N98672077: R1431.2 U1401.16(ADCDAT)
N98806492: C901.1 C904.1 J901.47 J901.48 L902.2
N98806494: C902.1 C903.1 J901.46 L901.2 R912.1
N98806512: J901.40 R910.2
N98806513: J901.41 R911.2
N98806514: J901.45 R912.2
N98806535: J901.38 R907.2
N98806536: J901.39 R908.2
N98966209: TP1301.1(Pin1) U1301.9(INT2)
N98988302: C1315.2 U1301.2(BYP)
N98998296: D901.C Q901.1(GATE) R913.2 R914.1
N99177484: R1432.2 U1401.13(DACLRC)
N99177512: R1433.2 U1401.14(DACDAT)
N99177533: R1434.2 U1401.11(MCLK)
N99195829: R1435.2 U1401.15(ADCLRC/GPIO1)
N99261871: J901.4 R922.2
N99261874: J901.3 R921.2
N99261877: J901.1 R919.2
N99261880: J901.2 R920.2
N99261883: J901.5 R923.2
N99261886: J901.6 R924.2
N99261889: J901.7 R925.2
N99261892: J901.8 R926.2
N99262106: J901.16 R933.2
N99262109: J901.10 R927.2
N99262112: J901.17 R934.2
N99262115: J901.15 R932.2
N99262118: J901.14 R931.2
N99262121: J901.13 R930.2
N99262124: J901.12 R929.2
N99262127: J901.11 R928.2
N99262341: J901.20 R936.2
N99262344: J901.21 R937.2
N99262347: J901.22 R938.2
N99262350: J901.26 R942.2
N99262353: J901.19 R935.2
N99262356: J901.23 R939.2
N99262359: J901.24 R940.2
N99262362: J901.25 R941.2
N99265725: J901.28 R943.2
N99265746: J901.29 R944.2
N99265767: J901.30 R945.2
N99265792: J901.32 R946.2
N99336104: J901.49 R917.2
N99363439: C905.1 J901.50 L903.2
N99370076: J901.43 L905.2
N99370078: J901.42 L904.2

Not connected (* = marked no-connect by the designer): J1001 14(Utility)*; J1401 6; U1002 5(VCC); U1003 5(VCC); U1203 5(VCC); U1301 8(NC)* 15(NC)*; U1302 3(NC)*; U1401 3(LINPUT2) 30(OUT3)

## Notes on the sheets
sheet 5
- Audio Codec
- OFF, SLEEP MODE
- Codec
- DCVDD
  DBVDD
  AVDD
  SPKVDD
- 1.71V - 3.6V
  1.71V - 3.6V
  2.70V - 3.6V
  2.70V - 5.5V
- HP JACK
- # HP_DET:
      LOW : REMOVE
      HIGH : PLUG
- o
- i
- 3.5mm POLE
- HSL
- HSR
- MIC
- GND
- # I2C ADDR:  0011010x
- Main Board MIC
- HP MIC
- SPK
sheet 6
- Motion Sensor 9-axis
- VDD:1.95V to 3.6V
  VDDIO:1.62V to Vdd
- Accelerometer
- # I2C/SPI auto detection
- e-Compass
- VDD:1.95V to 3.6V
  VDDIO:1.65V to Vdd
- Active 'H'
- # Current consumption:
  IddStby: 2uA
  Idd: 900uA
- # I2C ADDR: Write = 0x1C; Read = 0x1D;
- Gyroscope
- # I2C ADDR:
      SA0 = '0': 0x20;
      SA0 = '1': 0x21;
- # Current consumption:
  IddAct: 5mA
  IddStby: 2uA
sheet 7
- High Speed CAN Transceiver
- CAN CN
- # FSL High Speed CAN Transceiver
- CAN #1
- Standby: 5 uA
- Cable Buy
- CAN #2
sheet 8
- LCD CN
- LCD IF
- B0
- B1
- B2
- B3
- B4
- B5
- B6
- B7
- GND
- G0
- G1
- G2
- G3
- G4
- G5
- G6
- G7
- GND
- R0
- R1
- R2
- R3
- R4
- R5
- R6
- R7
- GND
- DE
- HSYNC
- GND
- VSYNC
- PWR
- DCLK
- GND
- X_L
- X_R
- # LCD Standby Mode PWR: 50uW
- Y_B
- Y_T
- SPI_CLK
- SPI_MOSI
- SPI_MISO
- SPI_CS
- I2C_CLK
- GND
- I2C_SDA
- VDD_1.8V
- VDD_3.3V
- VDD_5V
- VDD_5V
- PWREN
- RESET
sheet 9
- i.MX6UL EVK PWR TREE
- LDO
- VDD_SNVS_IN
- Always ON
- RICHTEK RT9169
- VDD_SNVS_IN
- LDO_ARM_SOC
- VDD_SNVS_CAP
- 3.3V/100mA Iq = 4uA
- 276uA
- LDO_1P1
- NVCC_PLL
- WALL Adapter: 5V/3A
- OVP
- DC/DC BUCK
- VDD_HIGH_IN
- VSYS
- VDD_HIGH_IN
- LDO_2P5
- VDD_HIGH_CAP
- PMIC_ON_REQ
- MPS MP2144
- 5V/3A
- 3.3V/2A Iq=40uA
- DCDC_3V3
- 125mA
- NVCC_GPIO/NVCC_ENET/NVCC_LCDIF
- NVCC_DRAM_2P5
- # MCIMX6UL-BB
- DC/DC BUCK
- VDDARM_IN
- VDD_ARM_CAP
- VDD_SOC_IN
- LDO_ARM_SOC
- DCDC_3V3_PG
- MPS MP2159
- 900mA
- VDD_SOC_CAP
- 1.275V/1A Iq=40uA
- DC/DC BUCK
- VDD_MEM1V5
- NVCC_DRAM
- MPS MP2159
- DCDC_3V3_PG
- 50mA
- FSL i.MX6UL CPU
- 1.35V/1A Iq=40uA
- NVCC_NAND
- # 1.8V for eMMC HS200 mode
- LDO
- RICHTEK RT9169
- 1.8V/100mA Iq = 4uA
- HIGH PSRR LDO
- VLDO_3V3
- RICHTEK RT9193
- VDDA_ADC_3P3
- DCDC_3V3
- 3.3V/300mA
- LDO
- NVCC_SD (3.3V/1.8V)
- RICHTEK RT9065
- NVCC_SD
- DCDC_3V3_PG
- 1.8V/3.3V/500mA
- # 1.8V for CSI;
  1.8V/3.3V for SIM
- LDO
- NVCC_CSI (1.8V/3.3V)
- RICHTEK RT9065
- NVCC_CSI
- DCDC_3V3
- 1.8V/3.3V/500mA
- USB_OTG_VBUS
- 50mA
- USB_OTG1_VBUS
- LOAD SW
- USB_HOST_VBUS
- LDO_USB
- VDD_USB_CAP
- USB_OTGx_PWR
- USB_OTG2_VBUS
- VLCD_3V3
- RGB LCD
- 3.3V/23mA
- TianMa TFT
- 5S2P
- BACKLIGHT
- LvDDR3
- BLT_PWM
- 16V/25mA
- RICHTEK RT9293B
- Micron: MT41K512M16
- VHDMI_3V3
- HDMI
- 3.3V/10mA
- DCDC_3V3
- LDO
- SILICON IMAGE SiI9022A
- VLDO_1V2
- 3.3V/200mA
- eMMC 4GB
- 1.2V/69.2mA
- RICHTEK RT9169
- Micron MTFC8GLCDM
- NVCC_NAND
- VSPK_5V
- 3.3V/1.8V
- Audio Codec
- 5V/511mA
- WM8960
- VAUD_3V3
- DCDC_3V3
- QSPI
- 3.3V/62.58mA
- 3.3V/20mA
- Micron N25Q256
- SENSOR
- VSENSOR_3V3
- eCompass/
  G-sensor/Gyroscope
- 3.3V/6.9mA
- DCDC_3V3
- NAND
- # MCIMX6UL-CM
- 3.3V/50mA
- Micron MT29F32G08
- CAN_VIO_3V3
- CAN
- 3.3V/1mA
- FSL  MC34901WEF
- CAN_VDD_5V
- 5V/65mA
- USB_OTG_VBUS
- USB OTG
- Ethernet x2
- VENET_3V3
- 3.3V/48.7mA
- LOAD SW
- USB_HOST_VBUS
- Micrel KSZ8081RNB
- USB HOST
- AVDD_2V8
- LDO
- RICHTEK RT9065
- SD Socket
- 2.8V/500mA
- LOAD SW
- SD1_nRST/POR_B
- Camera/EMV SIM
- CSI B2B CN
- LDO
- DVDD1V5
- BT MOD
- RICHTEK RT9065
- 1.5V/500mA
sheet 10
- i.MX6UL EVK Block Diagram
- #####  Blcok Diagram Rev 1.0  #####
- # MCIMX6UL-BB
- EMV SIM Socket
- MPN: MCIMX6UL-BB
  MPN: MCIMX6UL-CM
- Agile No: 28616
  Agile No: 28617
- smart card
- HDMI
- LCD
- Camera
- CAN x2
- JTAG
- Micro USB
- USB HOST
- 4.3" TFT 480x272
- Silicon Image
     SiI9022A
- OV5642 5MP
- Freescale MC34901WEF
- PIN Header
- DISP
- CSI/SIM
- USB OTG1
- USB OTG2
- CAN x2
- JTAG
- SODIMM
- # MCIMX6UL-CM
- NAND
- PWR
- eMMC/MicroSD
- POWER
- eMMC 4.51 Footprint only
- Discrete PWR
- NAND/SDIO/QSPI
- NAND/SD2/QSPIA
- QSPI
- FREESCALE
     i.MX6UL
- Micron N25Q256A
- DDR3/LvDDR3
- x16 bits
- DRAM
- Micron 8Gb: MT41K512M16
- SODIMM
- UART
- I2C/INT
- SD1
- RMII x2
- I2S
- UART
- Motion Sensors
- BlueTooth
- SD SLOT
- Ethernet x2 (RMII)
- CODEC
- UART-USB bridge
- eCompass MAG3110FCR2
- Full Size
- Silabs CP2102
- FPC Module
- Accelerometer MMA8563FCR1
- 100Base-TMicrel KSZ8081
- Wolfson WM8960
- Gyroscope: FXAS21000CQR1
- HP
- MIC
sheet 11
- MCIMX6UL-BB
- Schematics DevBoard
- Table of Content
- Revision History
- Page 1
- Cover
- Rev. Code
- Date
- By
- Description
- Page 2
- Block Diagram
- A
- 2015-02-28
- Javen
- 1
- Revision A released
- Page 3
- PWR TREE
- Page 4
- LCD
- Page 5
- HDMI
- B
- 2015-07-07
- Javen
- 1
- DNP R1023
- DNP R1435, R1404, Add R1436
- Page 6
- USB
- DNP R1517,Install R1520
- Change Camera J1801 connector
- Page 7
- CAN
- Change JTAG J1902 footprint
- Change SODIMM J2101 footprint
- Page 8
- Sensor
- Change R2101 from PU to PD
- Change J1901 PIN sequence
- Page 9
- Codec
- Page 10
- Ethernet x1
- C
- 2015-07-14
- Javen
- 1
- Add R919-R946,L903-L905
- Page 11
- Ethernet x2
- DNP R1436,Install R1404,R1435
- Change HP_MIC1N to LINPUT1
- Page 12
- SD/BT
- Add BT_DISABLE,ECSPI4_SS0,ECSPI4_MOSI,ECSPI4_SCLK for BT
- Add R2107~R2116 to reduce the VSNVS power consumption due to the TAMPER reason
  Add L903~L930 as FCC/CE backup
- Page 13
- Camera
- Change Camera J1801 connector direction on layout
- Page 14
- DBG/JTAG
- Add C905
- Page 15
- SYS PWR
- Change J1701 from TOP contact to BOT contact for BT
- Page 16
- SODIMM BB
- Page 17
- NOTE
- Page 18
- IOMUX
- C1
- 2016-05-05
- Javen
- 1
- DNP J1801,J1001 due to cost reason
- Page 19
- Page 20
- Page 21
- Updated to be NCL compliance.
  - parts: J901, J1701, J1802, J2101
  - Title blocks
- C2
- 18-Oct-2016
- Marek B.
- Page 22
- Page 23
- Page 24
- Page 25
- Page 26
- Page 26
- Page 27
- Page 28
- 3. Device type number is for reference only. The number
      varies with the manufacturer.
- 1. Unless Otherwise Specified:
- All resistors are in ohms, 10%, 1/8 Watt,0603
- 4. Special signal usage:
- All capacitors are in uF, 20%, 50V,0603
- _B Denotes - Active-Low Signal
- All voltages are DC
- <> or [] Denotes - Vectored Signals
- All polarized capacitors are aluminum electrolytic
- 5. Interpret diagram in accordance with American
  National Standards Institute specifications, current
  revision, with the exception of logic block symbology.
- 2. Interrupted lines coded with the same letter or letter
      combinations are electrically connected.
sheet 12
- HDMI Transmitter
- EMI/ESD
- #Res Overlap with EMI Choke
- Standby: 150 uW
- HDMI TYPEA
- 1.2V PWR
- # 1.2V/100mA Iq = 4μA
- Internal Function
- CI2CA = LOW
- CI2CA = HIGH
- Transmitter Programming Interface (TPI) device address
- 0x72
- 0x76
- CEC Programming Interface (CPI) device address
- 0xC0
- 0xC4
- SiI9020-compatible internal registers: first device address
- 0x72
- 0x76
- SiI9020-compatible internal registers: second device address
- 0x7A
- 0x7E
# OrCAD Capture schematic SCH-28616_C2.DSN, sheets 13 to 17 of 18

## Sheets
13 M-07 Ethernet RMII x1: size C
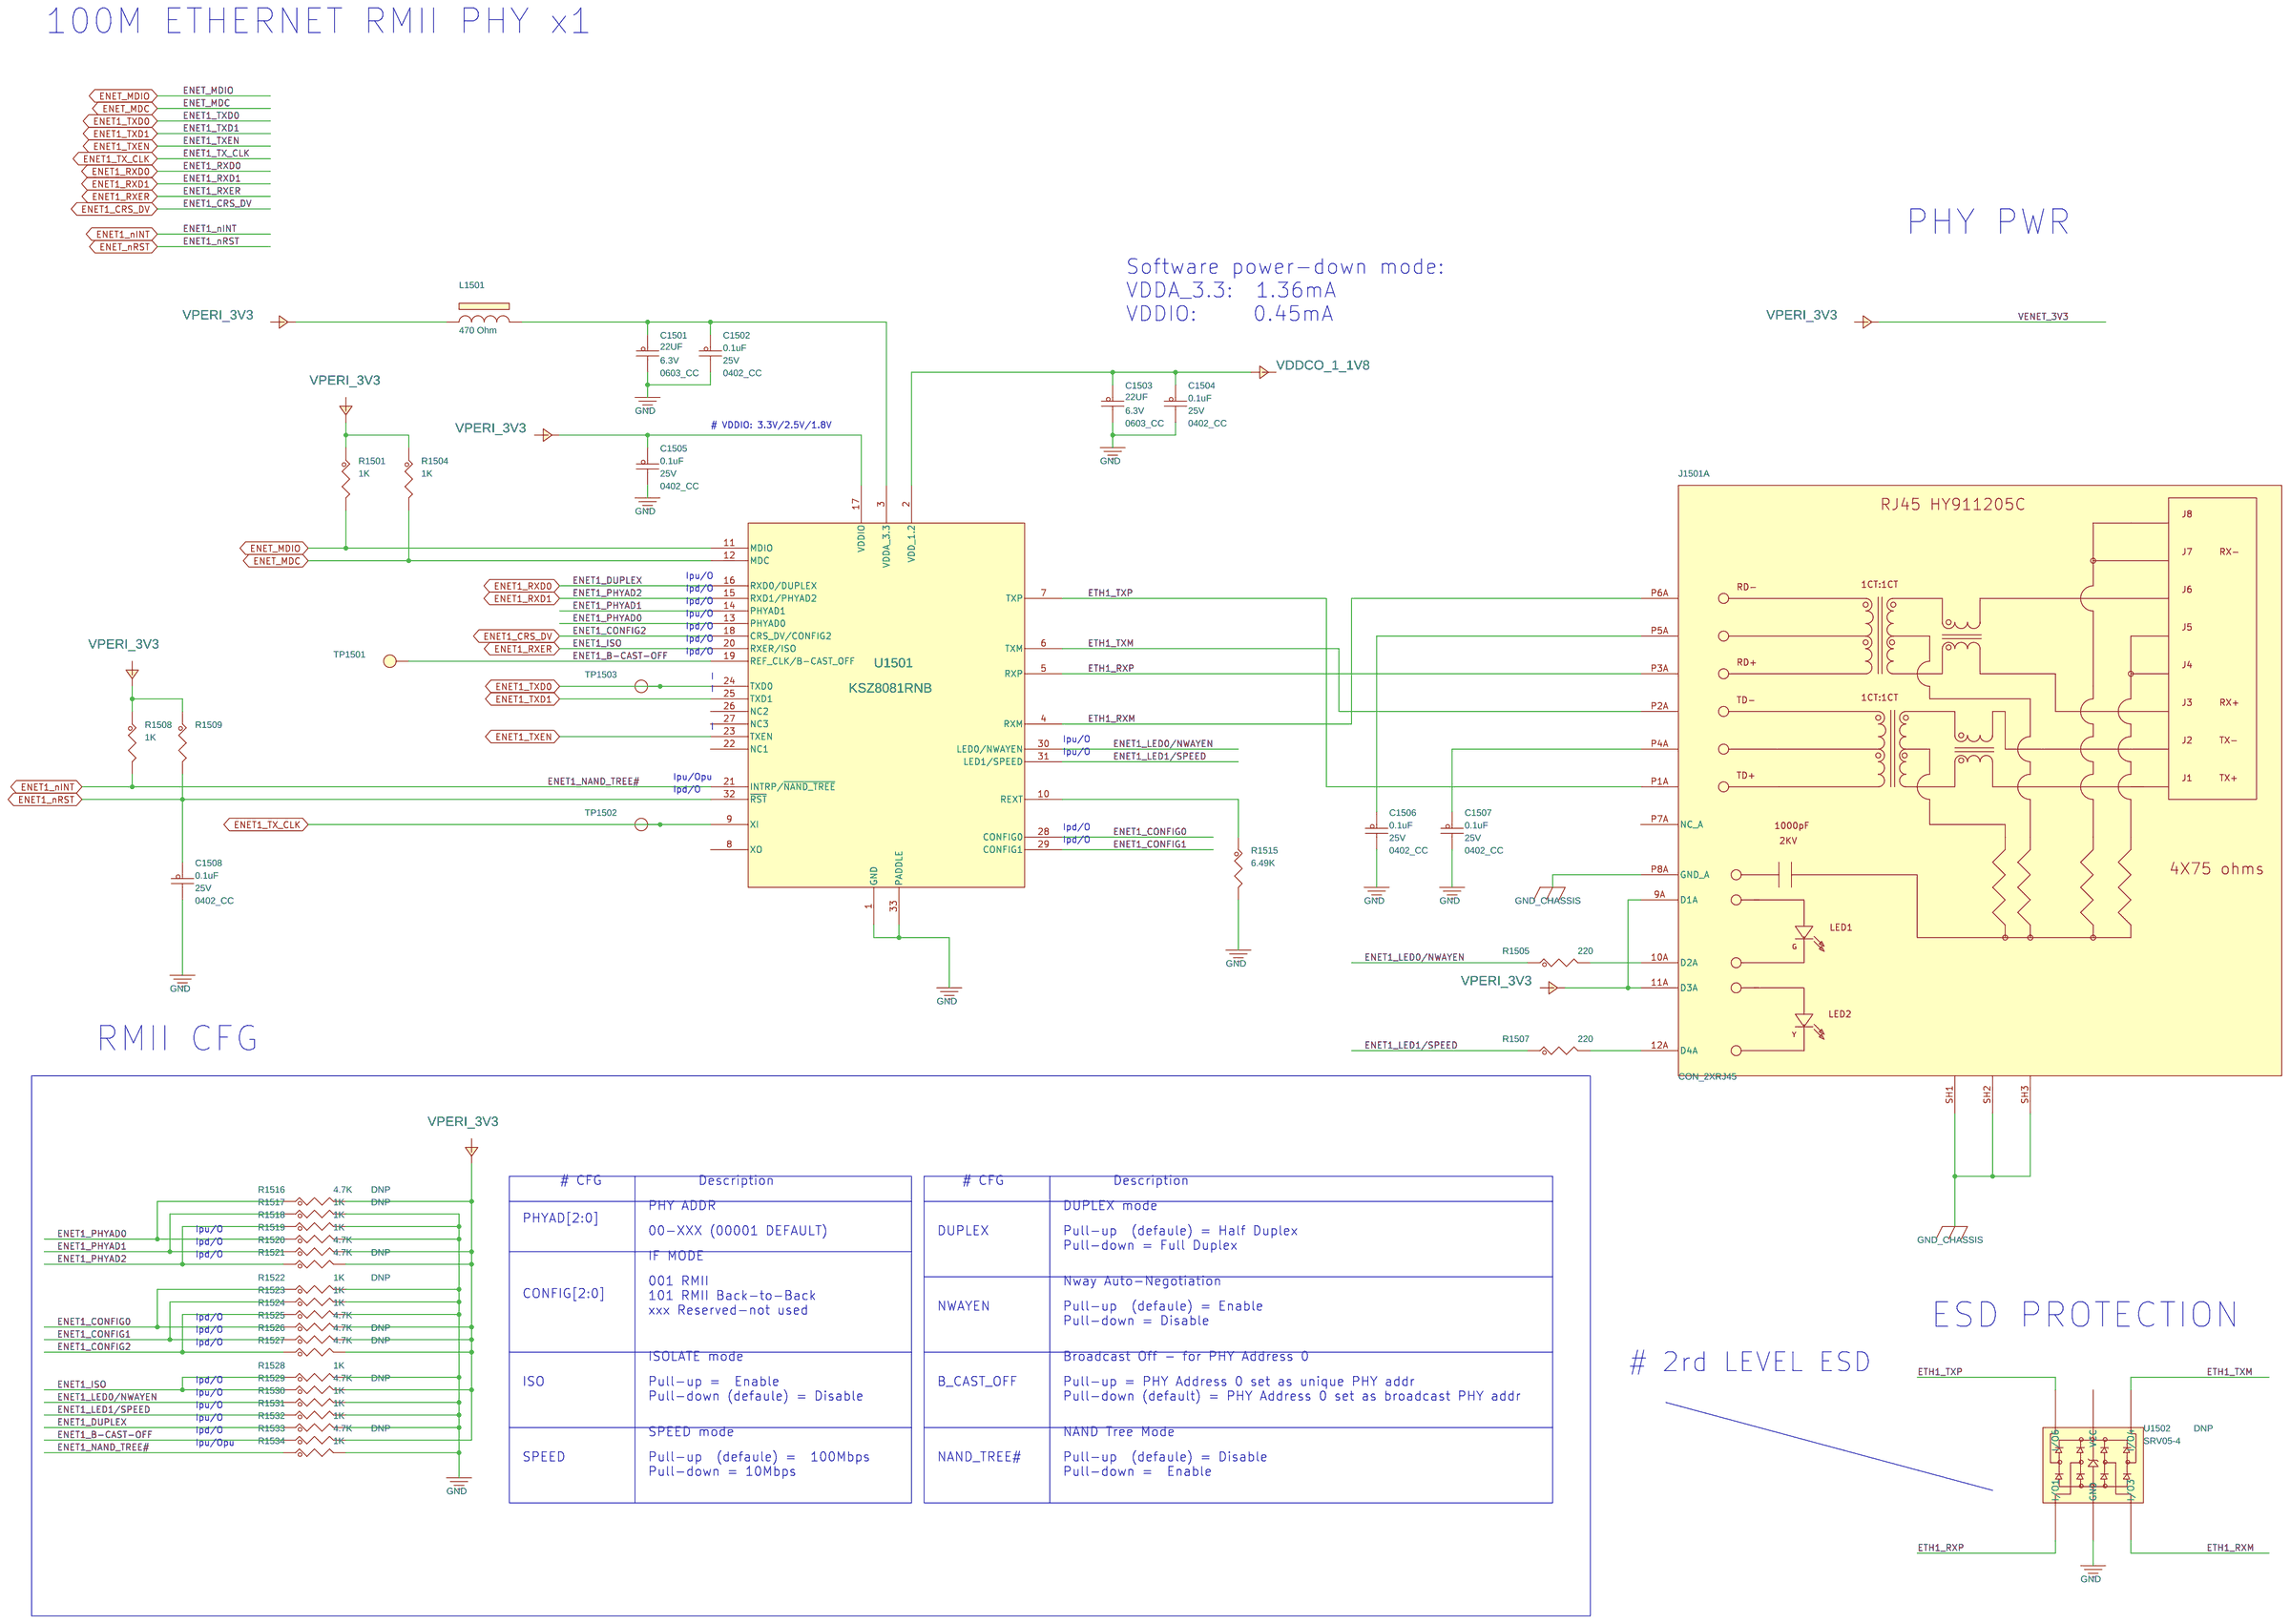
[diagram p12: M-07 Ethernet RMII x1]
14 M-08 Ethernet RMII x2: size C
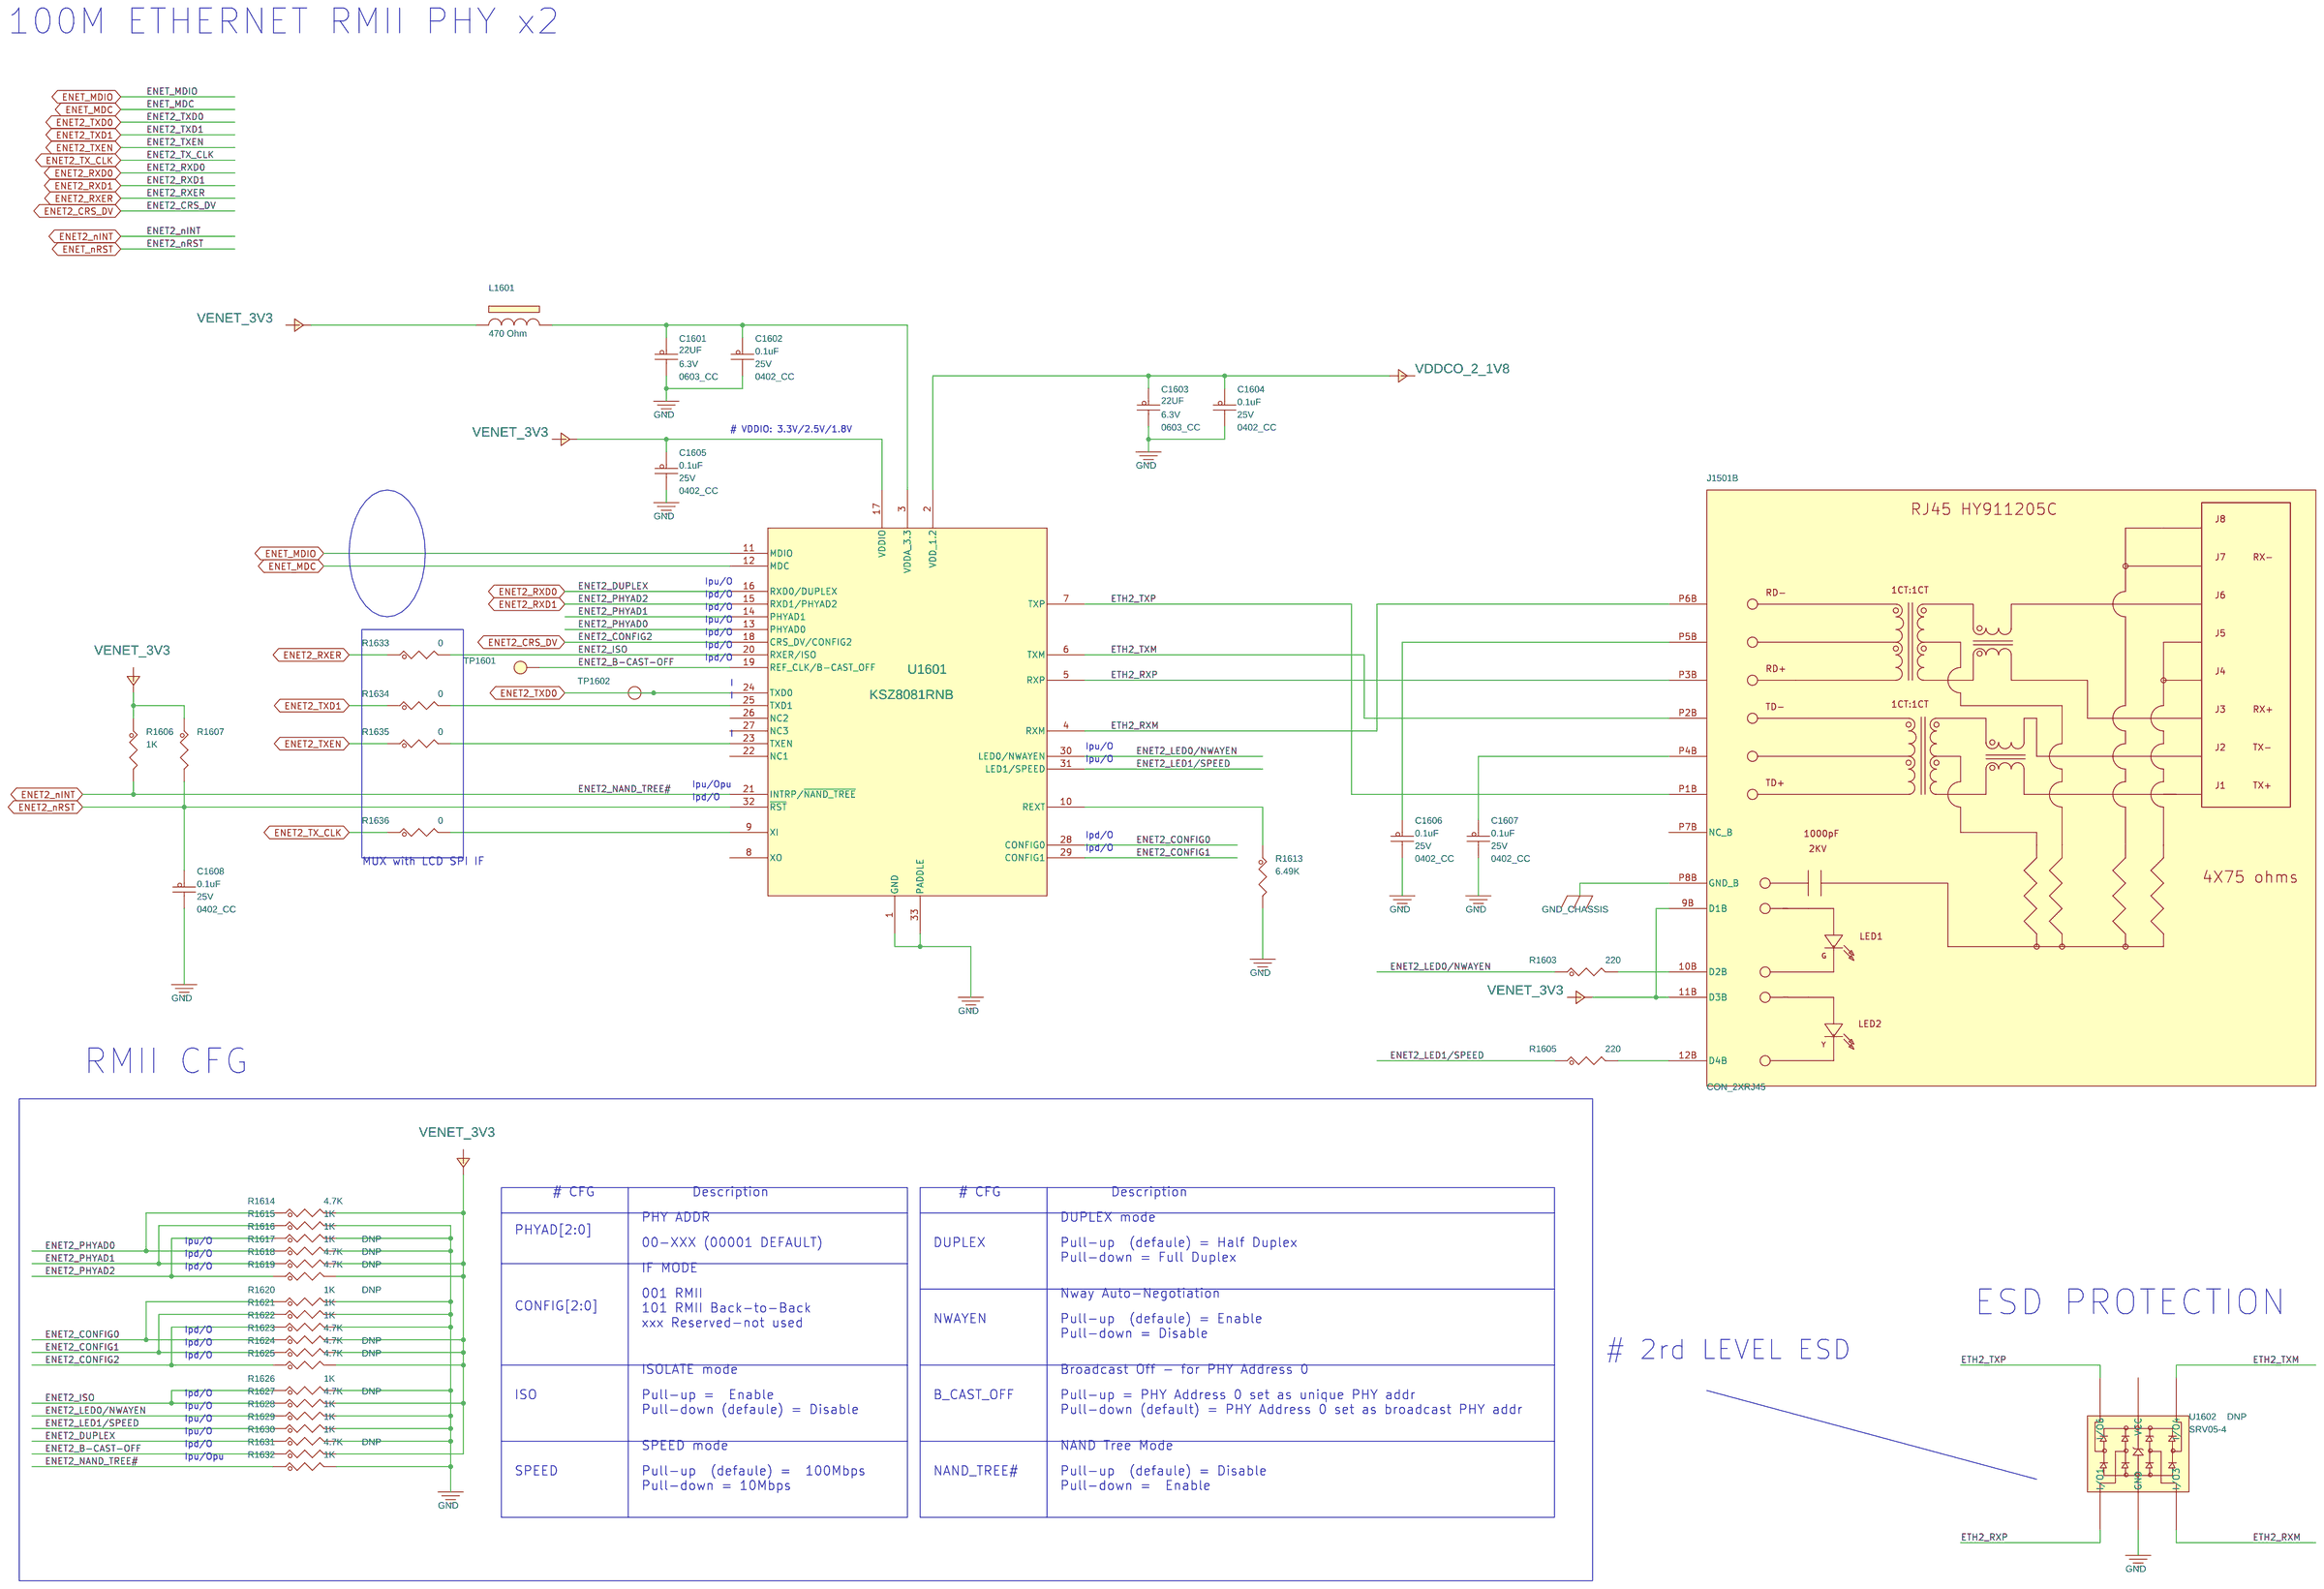
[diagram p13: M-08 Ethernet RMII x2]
15 M-13 SYS POWER: size C
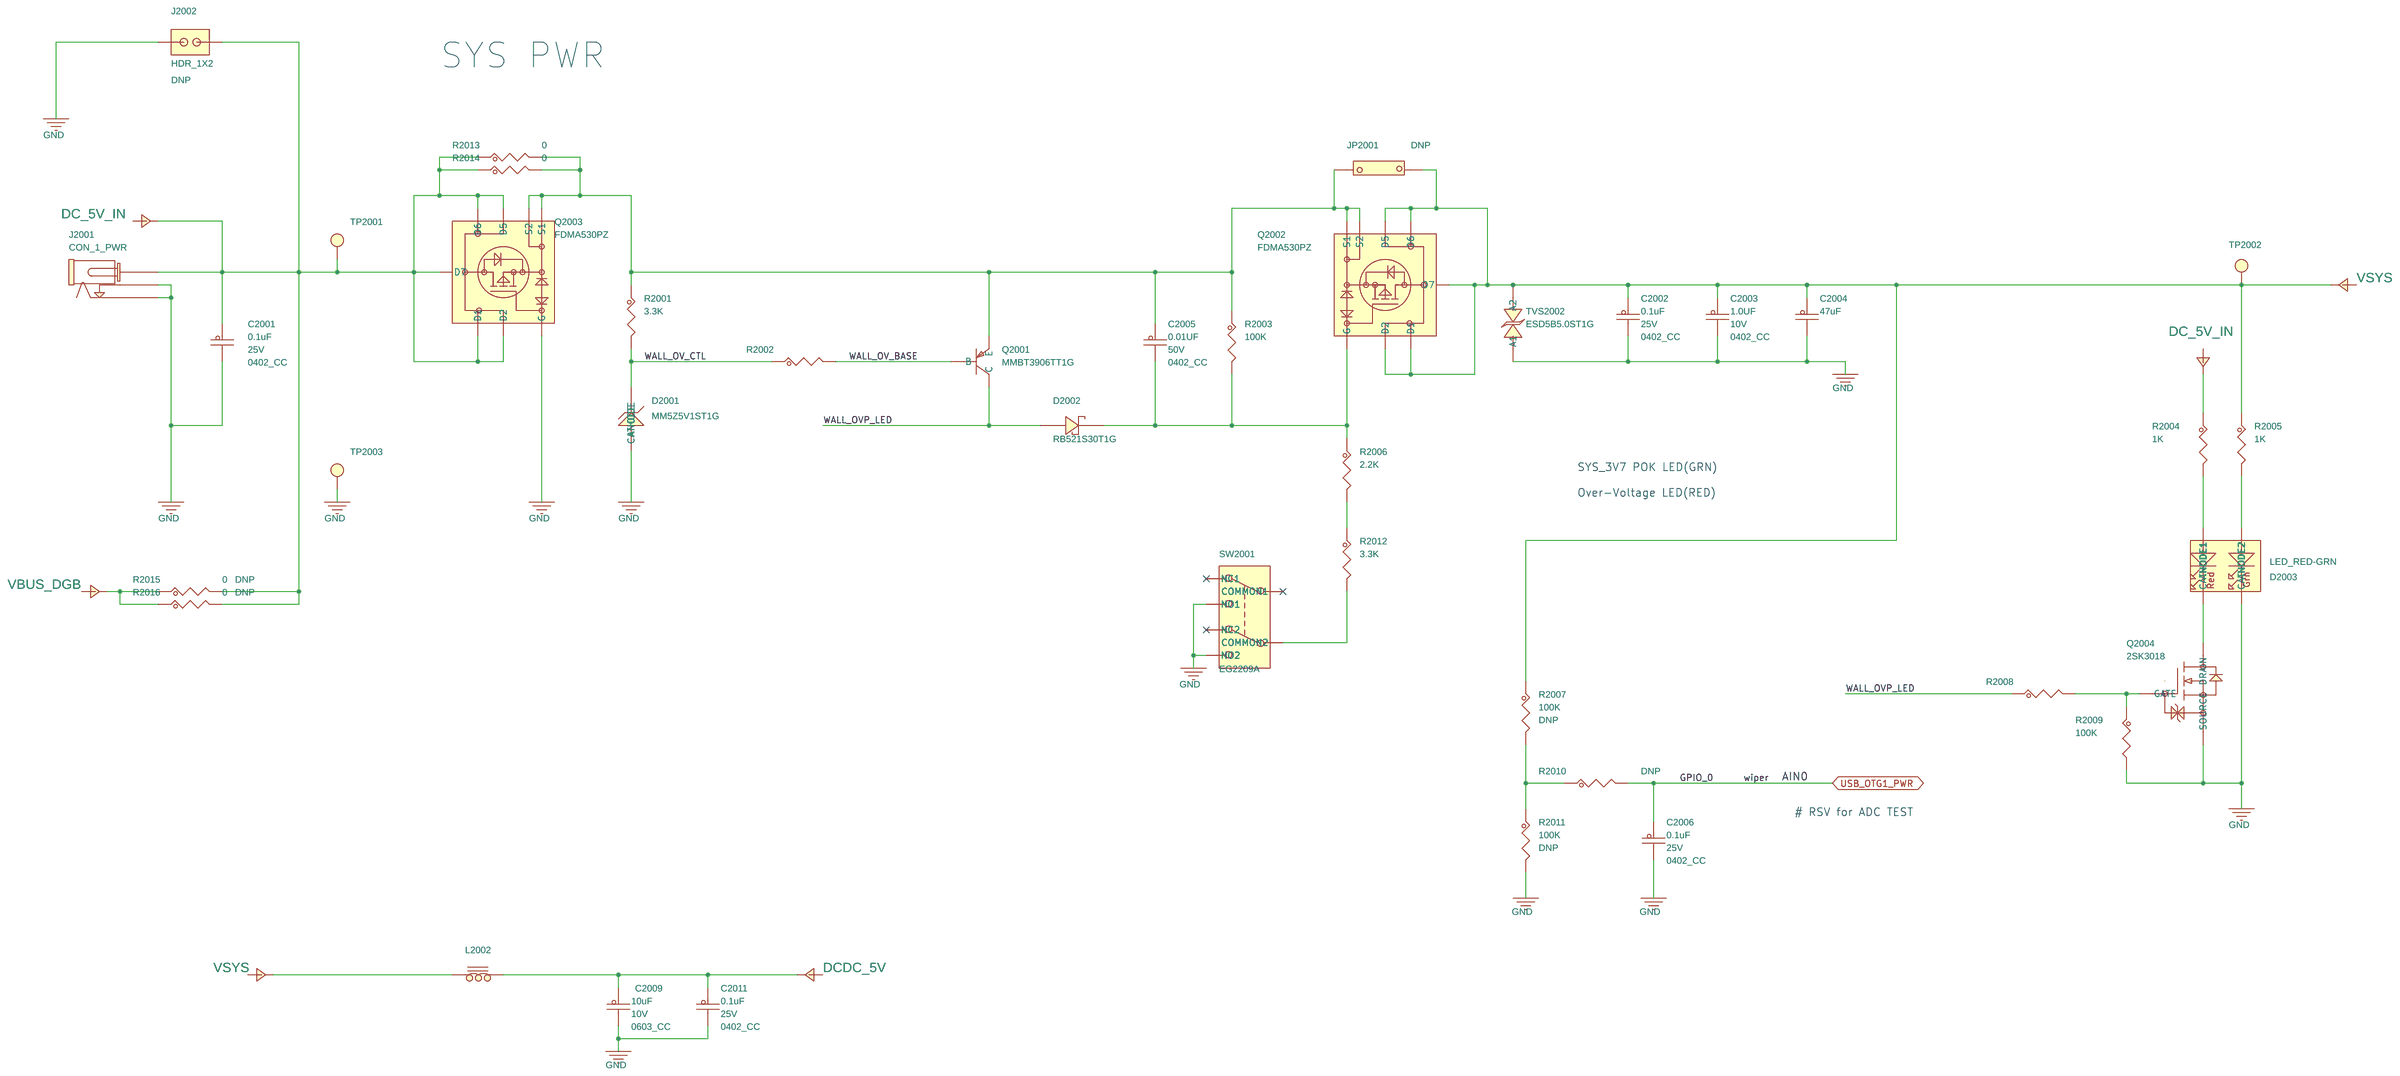
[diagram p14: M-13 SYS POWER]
16 M-12 Debug/JTAG: size C
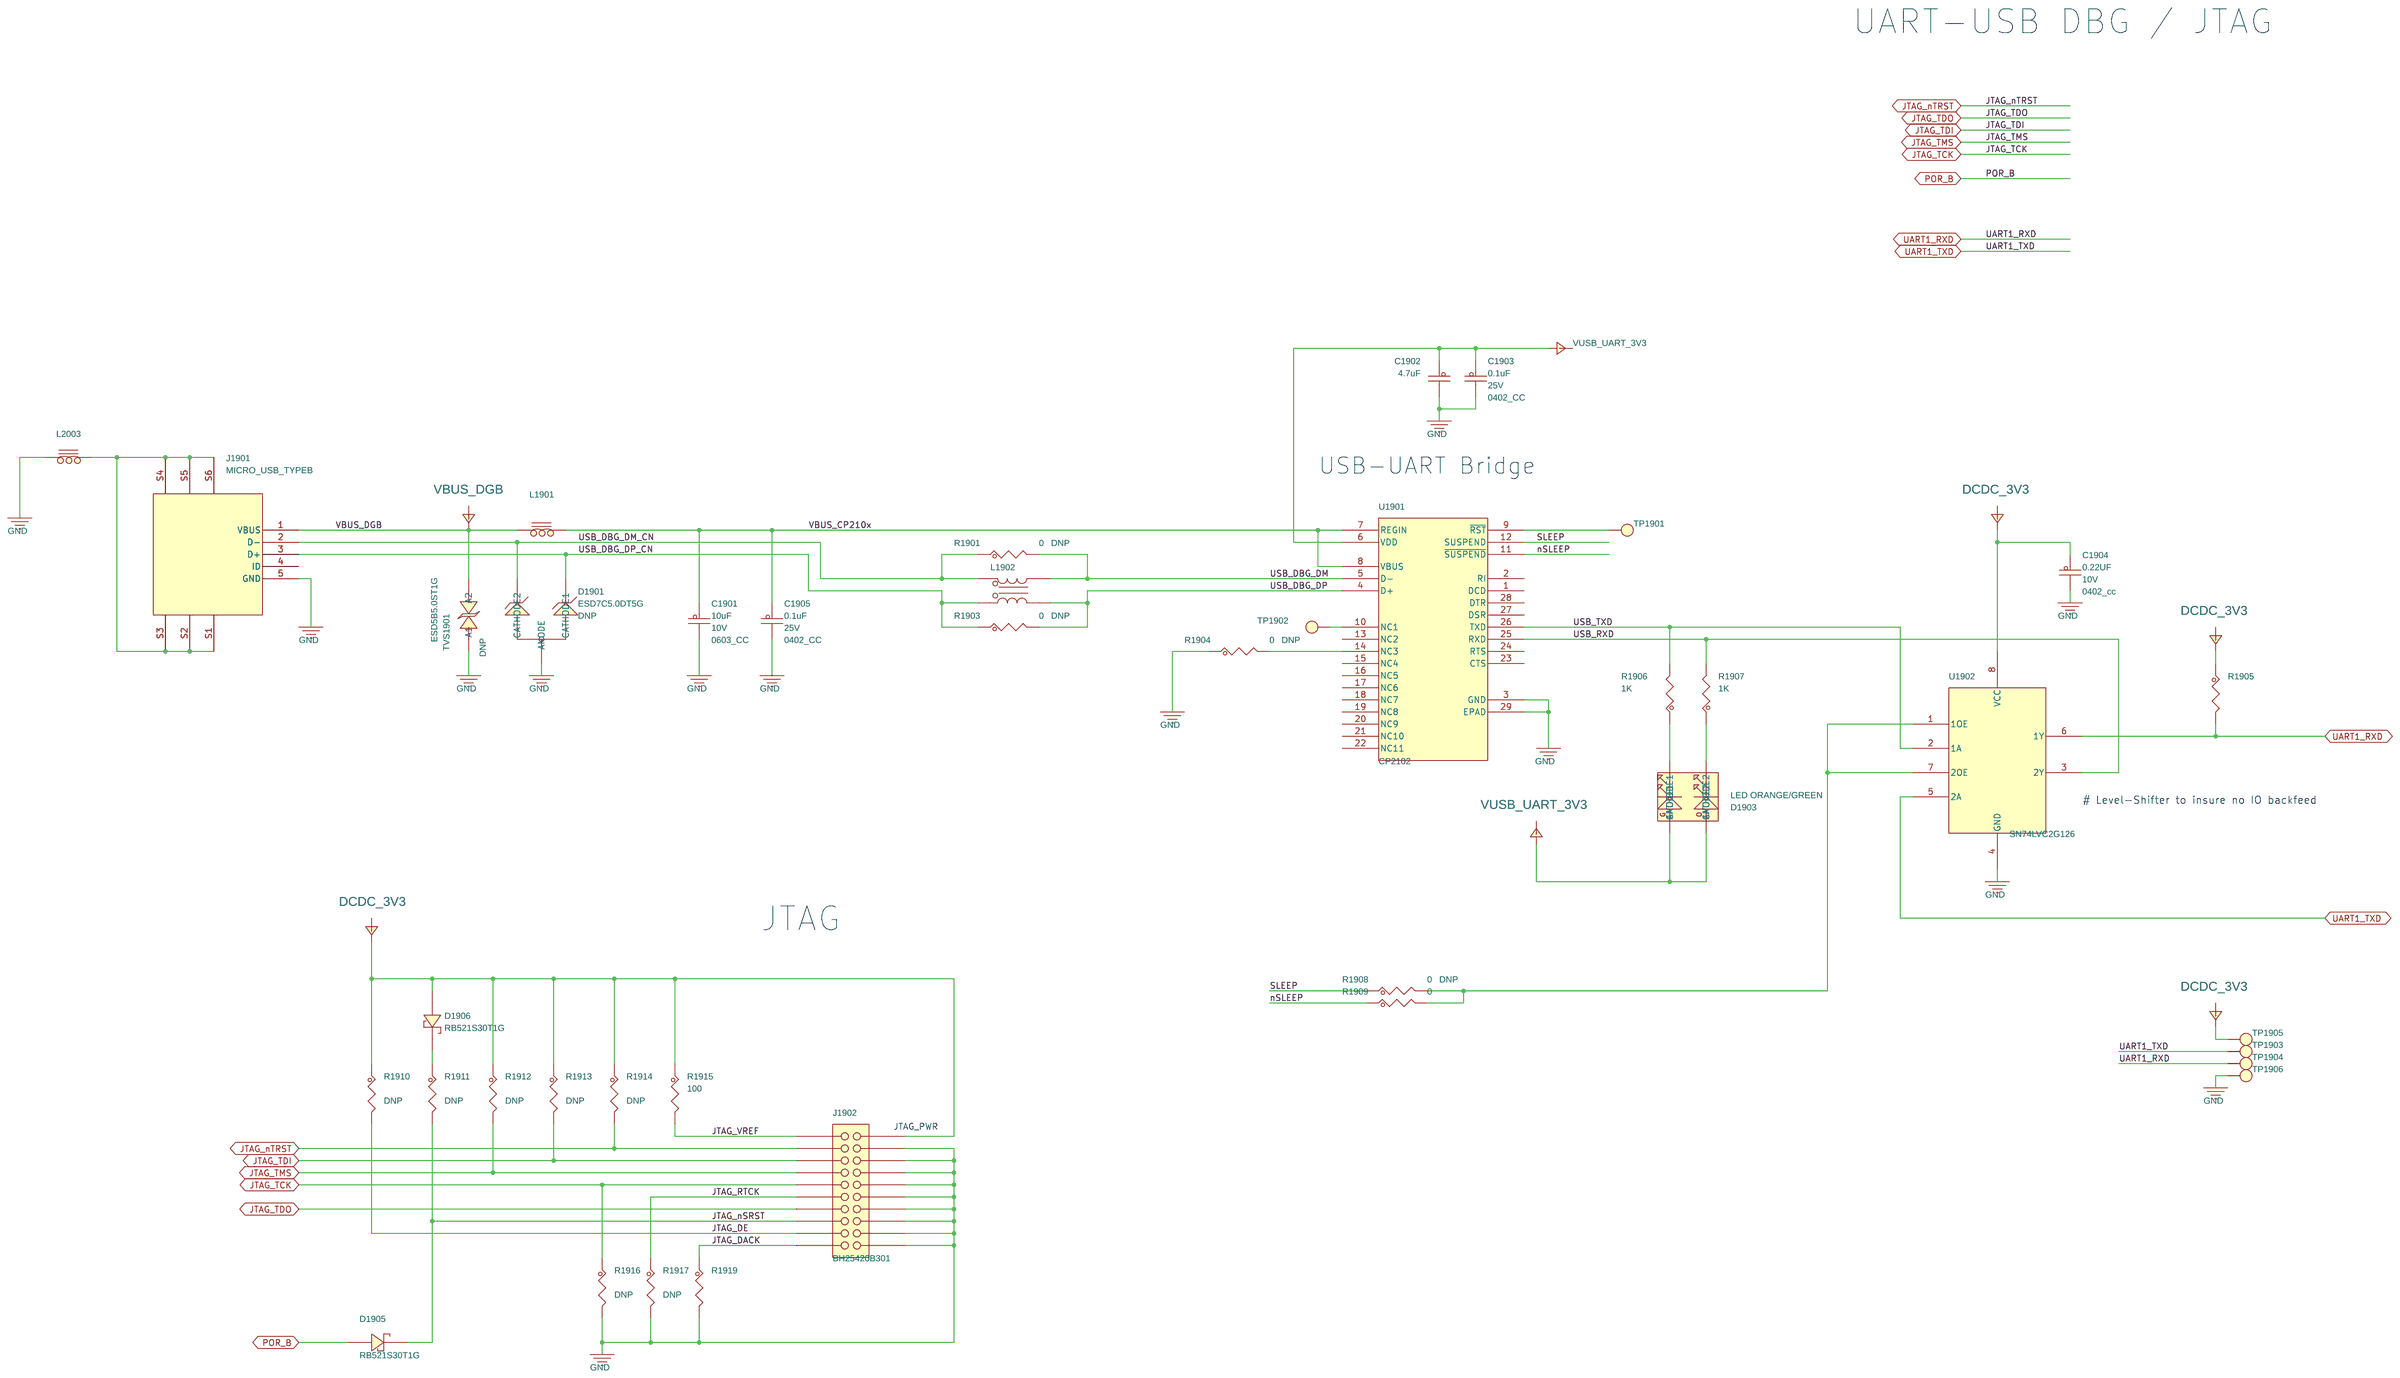
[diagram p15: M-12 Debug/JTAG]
17 M-03 USB OTG / HOST: size C

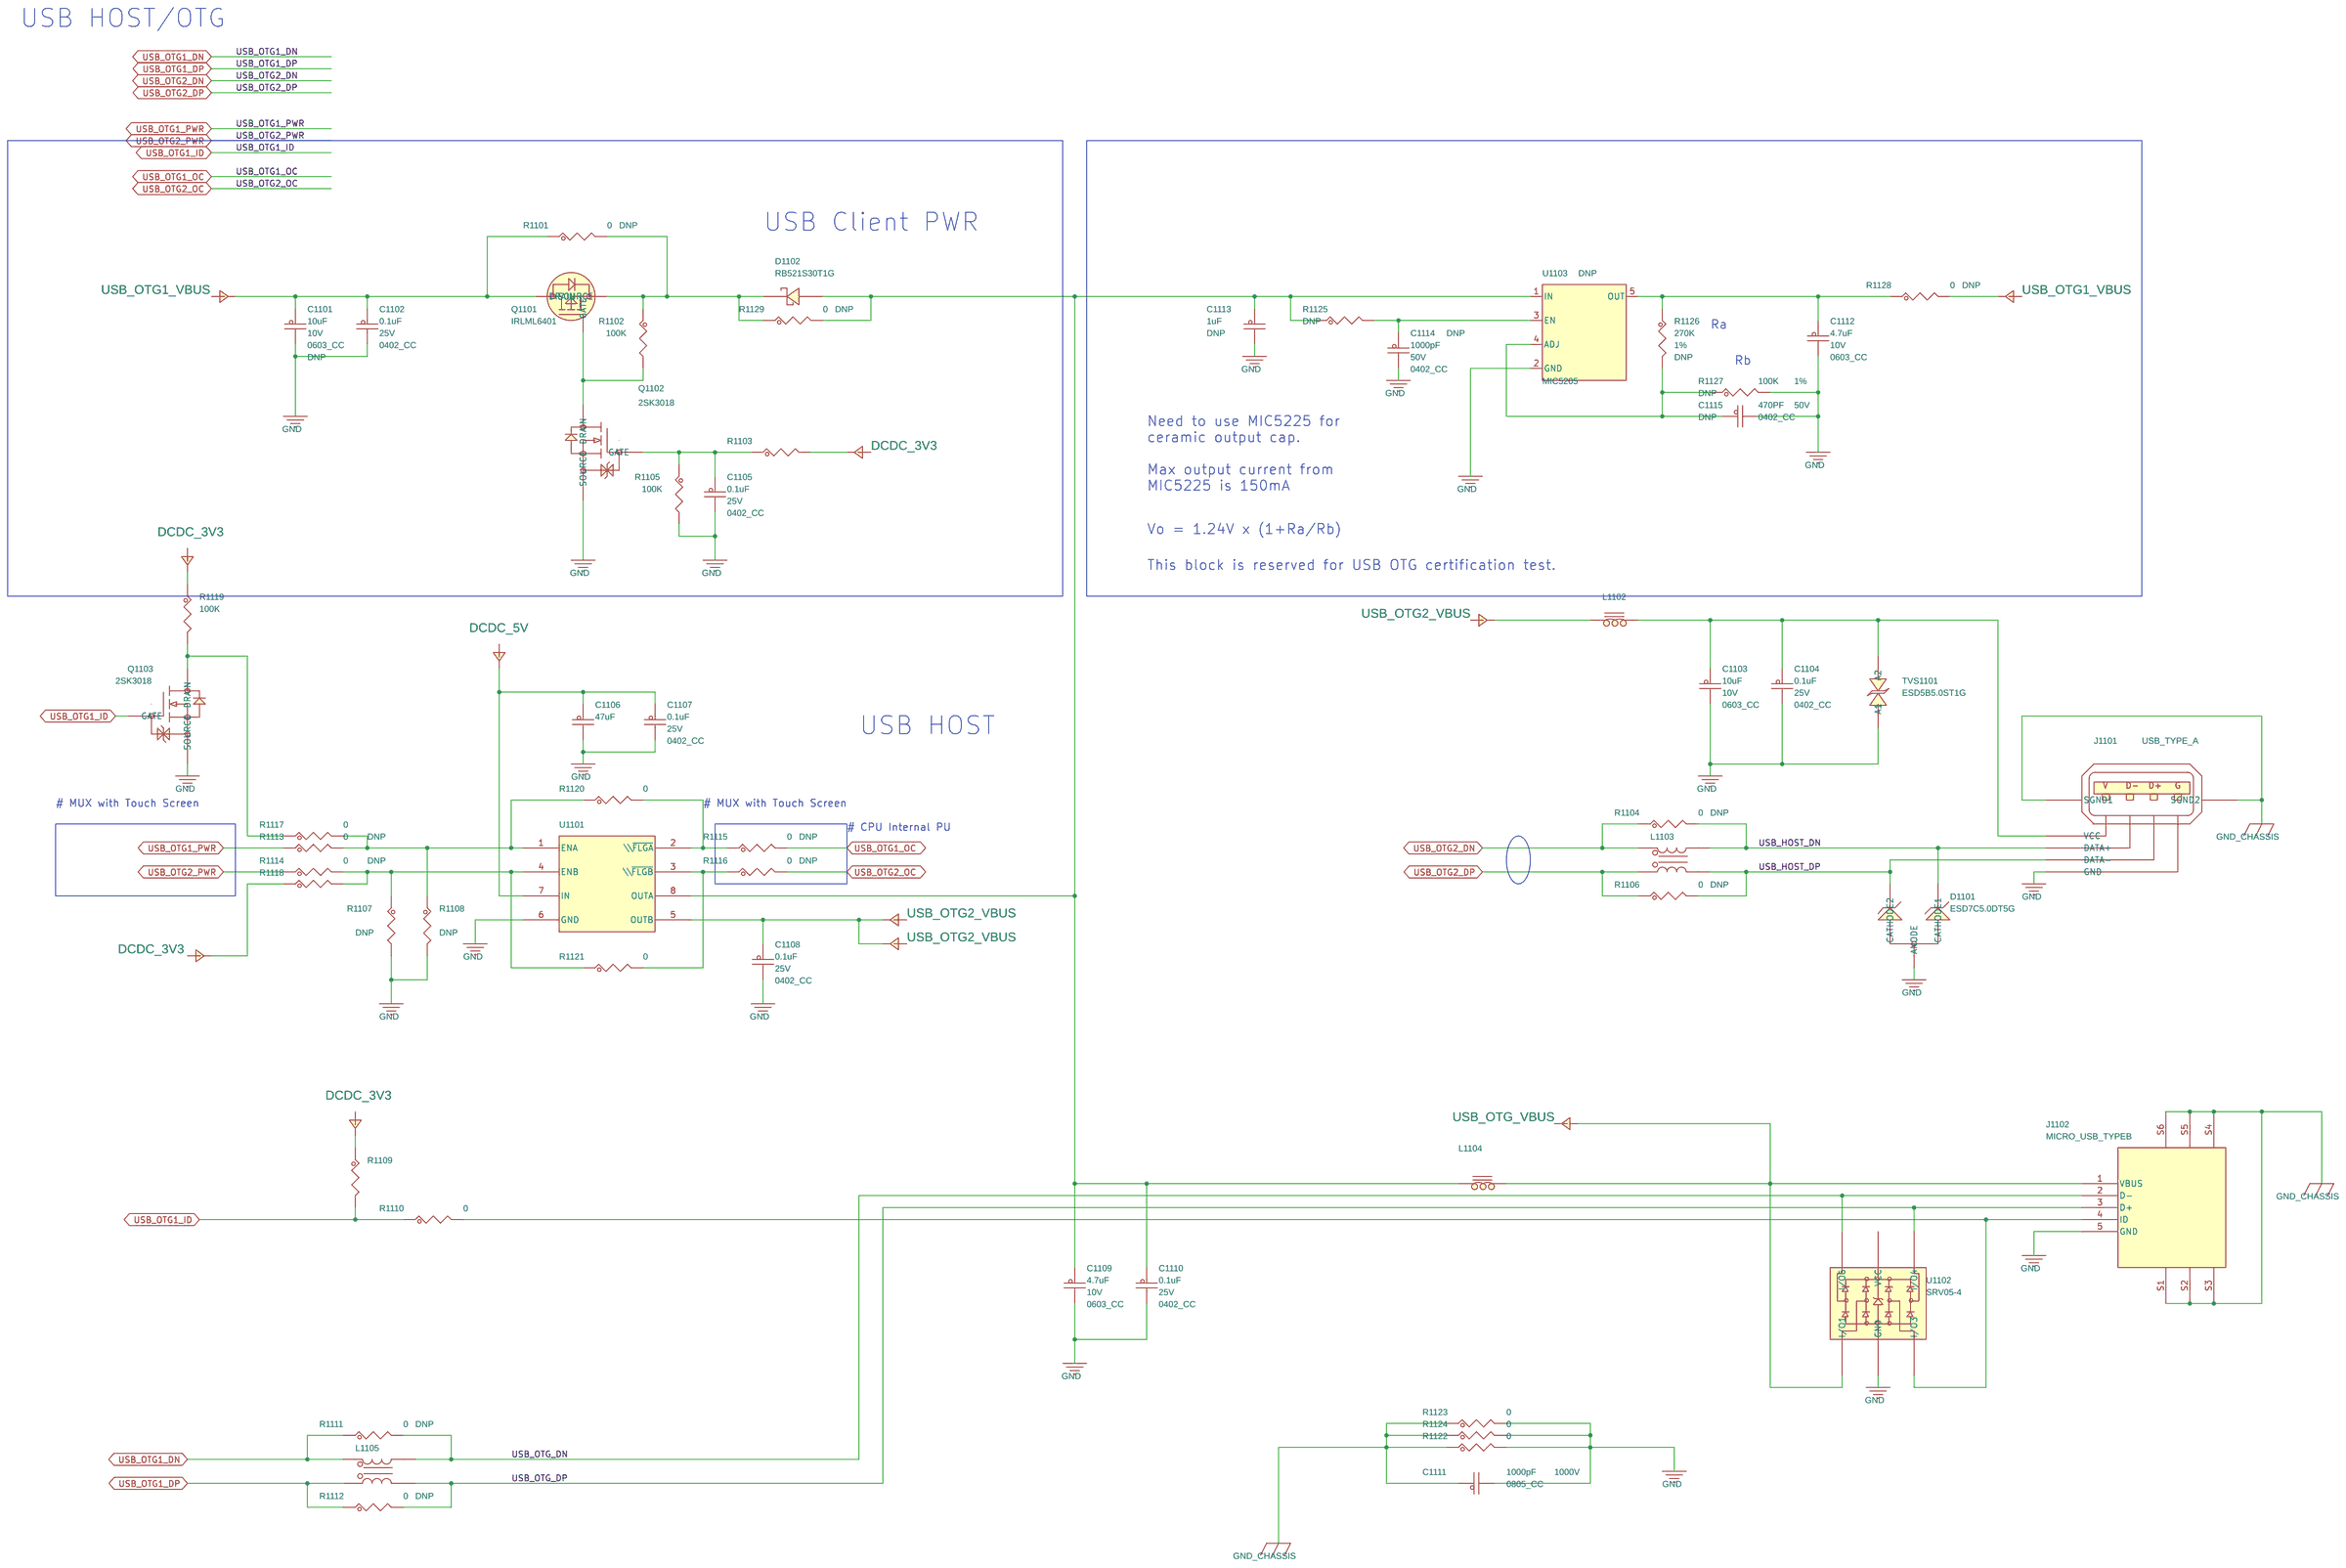
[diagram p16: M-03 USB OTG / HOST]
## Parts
sheet M-03 USB OTG / HOST
C1101  10uF  [0603_CC]
C1102  0.1uF  [0402_CC]
C1103  10uF  [0603_CC]
C1104  0.1uF  [0402_CC]
C1105  0.1uF  [0402_CC]
C1106  47uF  [0805_CC]
C1107  0.1uF  [0402_CC]
C1108  0.1uF  [0402_CC]
C1109  4.7uF  [0603_CC]
C1110  0.1uF  [0402_CC]
C1111  1000pF  [0805_CC]
C1112  4.7uF  [0603_CC]
C1113  1uF  [0402_CC]
C1114  1000pF  [0402_CC]
C1115  470PF  [0402_CC]
D1101  ESD7C5.0DT5G  [sot-723]
D1102  RB521S30T1G  [sod_523]
J1101  USB_TYPE_A  [con4_usb_a_fe_ra_th]
J1102  MICRO_USB_TYPEB  [con_usb_type_b_sm]
L1102  120OHM  [0603_CC]
L1103  90OHM  [ind4_choke_0805]
L1104  120OHM  [0603_CC]
L1105  90OHM  [ind4_choke_0805]
Q1101  IRLML6401  [sot-23]
Q1102  2SK3018  [SOT323_3]
Q1103  2SK3018  [SOT323_3]
R1101  0  [0402_CC]
R1102  100K  [0402_CC]
R1103  10K  [0402_CC]
R1104  0  [0402_CC]
R1105  100K  [0402_CC]
R1106  0  [0402_CC]
R1107  10K  [0402_CC]
R1108  10K  [0402_CC]
R1109  10K  [0402_CC]
R1110  0  [0402_CC]
R1111  0  [0402_CC]
R1112  0  [0402_CC]
R1113  0  [0402_CC]
R1114  0  [0402_CC]
R1115  0  [0402_CC]
R1116  0  [0402_CC]
R1117  0  [0402_CC]
R1118  10K  [0402_CC]
R1119  100K  [0402_CC]
R1120  0  [0402_CC]
R1121  0  [0402_CC]
R1122  0  [0805_CC]
R1123  0  [0805_CC]
R1124  0  [0805_CC]
R1125  10K  [0402_CC]
R1126  270K  [RC0402_25]
R1127  100K  [RC0402_25]
R1128  0  [0402_CC]
R1129  0  [0402_CC]
TVS1101  ESD5B5.0ST1G  [diode2_sod523]
U1101  MIC2026-1YM  [SO8]
U1102  SRV05-4  [SOT23_S6]
U1103  MIC5205  [sot23-20x60-5]
sheet M-07 Ethernet RMII x1
C1501  22UF  [0603_CC]
C1502  0.1uF  [0402_CC]
C1503  22UF  [0603_CC]
C1504  0.1uF  [0402_CC]
C1505  0.1uF  [0402_CC]
C1506  0.1uF  [0402_CC]
C1507  0.1uF  [0402_CC]
C1508  0.1uF  [0402_CC]
L1501  470 Ohm  [IND0603_CC]
R1501  1K  [0402_CC]
R1504  1K  [0402_CC]
R1505  220  [0402_CC]
R1507  220  [0402_CC]
R1508  1K  [0402_CC]
R1509  10K  [0402_CC]
R1515  6.49K  [0402_CC]
R1516  4.7K  [0402_CC]
R1517  1K  [0402_CC]
R1518  1K  [0402_CC]
R1519  1K  [0402_CC]
R1520  4.7K  [0402_CC]
R1521  4.7K  [0402_CC]
R1522  1K  [0402_CC]
R1523  1K  [0402_CC]
R1524  1K  [0402_CC]
R1525  4.7K  [0402_CC]
R1526  4.7K  [0402_CC]
R1527  4.7K  [0402_CC]
R1528  1K  [0402_CC]
R1529  4.7K  [0402_CC]
R1530  1K  [0402_CC]
R1531  1K  [0402_CC]
R1532  1K  [0402_CC]
R1533  4.7K  [0402_CC]
R1534  1K  [0402_CC]
TP1501  TP_35MIL  [testpoint_35mil]
TP1502  TPAD_015  [TPAD_015]
TP1503  TPAD_015  [TPAD_015]
U1501  KSZ8081RNB  [qfn32_0p5_ep3p3]
U1502  SRV05-4  [SOT23_S6]
sheet M-08 Ethernet RMII x2
C1601  22UF  [0603_CC]
C1602  0.1uF  [0402_CC]
C1603  22UF  [0603_CC]
C1604  0.1uF  [0402_CC]
C1605  0.1uF  [0402_CC]
C1606  0.1uF  [0402_CC]
C1607  0.1uF  [0402_CC]
C1608  0.1uF  [0402_CC]
J1501  CON_2XRJ45  [CON_1X2_RJ45_1P27_TH_RA]  (sections A,B)
L1601  470 Ohm  [IND0603_CC]
R1603  220  [0402_CC]
R1605  220  [0402_CC]
R1606  1K  [0402_CC]
R1607  10K  [0402_CC]
R1613  6.49K  [0402_CC]
R1614  4.7K  [0402_CC]
R1615  1K  [0402_CC]
R1616  1K  [0402_CC]
R1617  1K  [0402_CC]
R1618  4.7K  [0402_CC]
R1619  4.7K  [0402_CC]
R1620  1K  [0402_CC]
R1621  1K  [0402_CC]
R1622  1K  [0402_CC]
R1623  4.7K  [0402_CC]
R1624  4.7K  [0402_CC]
R1625  4.7K  [0402_CC]
R1626  1K  [0402_CC]
R1627  4.7K  [0402_CC]
R1628  1K  [0402_CC]
R1629  1K  [0402_CC]
R1630  1K  [0402_CC]
R1631  4.7K  [0402_CC]
R1632  1K  [0402_CC]
R1633  0  [0402_CC]
R1634  0  [0402_CC]
R1635  0  [0402_CC]
R1636  0  [0402_CC]
TP1601  TP_35MIL  [testpoint_35mil]
TP1602  TPAD_015  [TPAD_015]
U1601  KSZ8081RNB  [qfn32_0p5_ep3p3]
U1602  SRV05-4  [SOT23_S6]
sheet M-12 Debug/JTAG
C1901  10uF  [0603_CC]
C1902  4.7uF  [0402_CC]
C1903  0.1uF  [0402_CC]
C1904  0.22UF  [0402_cc]
C1905  0.1uF  [0402_CC]
D1901  ESD7C5.0DT5G  [sot-723]
D1903  LED ORANGE/GREEN  [led_0606]
D1905  RB521S30T1G  [sod_523]
D1906  RB521S30T1G  [sod_523]
J1901  MICRO_USB_TYPEB  [con_usb_type_b_sm]
J1902  BH25420B301  [hdr_2x10m_100_th]
L1901  120OHM  [0603_CC]
L1902  90OHM  [ind4_choke_0805]
L2003  120OHM  [0603_CC]
R1901  0  [0402_CC]
R1903  0  [0402_CC]
R1904  0  [0402_CC]
R1905  10K  [0402_CC]
R1906  1K  [0402_CC]
R1907  1K  [0402_CC]
R1908  0  [0402_CC]
R1909  0  [0402_CC]
R1910  10K  [0402_CC]
R1911  10K  [0402_CC]
R1912  10K  [0402_CC]
R1913  10K  [0402_CC]
R1914  10K  [0402_CC]
R1915  100  [0402_CC]
R1916  10K  [0402_CC]
R1917  10K  [0402_CC]
R1919  10K  [0402_CC]
TP1901  TP_35MIL  [testpoint_35mil]
TP1902  TP_35MIL  [testpoint_35mil]
TP1903  TP_35MIL  [testpoint_35mil]
TP1904  TP_35MIL  [testpoint_35mil]
TP1905  TP_35MIL  [testpoint_35mil]
TP1906  TP_35MIL  [testpoint_35mil]
TVS1901  ESD5B5.0ST1G  [diode2_sod523]
U1901  CP2102  [qfn28_5x5mm_3p3_ep]
U1902  SN74LVC2G126  [SSOP8]
sheet M-13 SYS POWER
C2001  0.1uF  [0402_CC]
C2002  0.1uF  [0402_CC]
C2003  1.0UF  [0402_CC]
C2004  47uF  [0805_CC]
C2005  0.01UF  [0402_CC]
C2006  0.1uF  [0402_CC]
C2009  10uF  [0603_CC]
C2011  0.1uF  [0402_CC]
D2001  MM5Z5V1ST1G  [sod_523_1p4]
D2002  RB521S30T1G  [sod_523]
D2003  LED_RED-GRN  [LED_DUAL_3025MM_SM]
J2001  CON_1_PWR  [con3_pwr_th]
J2002  HDR_1X2  [hdr102_100mil]
JP2001  SHORT_100mil  [100MIL_TH]
L2002  120OHM  [0603_CC]
Q2001  MMBT3906TT1G  [sc_75]
Q2002  FDMA530PZ  [MLP6_2X2MM_SLUG]
Q2003  FDMA530PZ  [MLP6_2X2MM_SLUG]
Q2004  2SK3018  [SOT323_3]
R2001  3.3K  [0603_CC]
R2002  10K  [0402_CC]
R2003  100K  [0402_CC]
R2004  1K  [0402_CC]
R2005  1K  [0402_CC]
R2006  2.2K  [0603_CC]
R2007  100K  [0402_CC]
R2008  10K  [0402_CC]
R2009  100K  [0402_CC]
R2010  1K  [0402_CC]
R2011  100K  [0402_CC]
R2012  3.3K  [0603_CC]
R2013  0  [0805_CC]
R2014  0  [0805_CC]
R2015  0  [0805_CC]
R2016  0  [0805_CC]
SW2001  EG2209A  [sw6_dpdt_11x6mm]
TP2001  TP_35MIL  [testpoint_35mil]
TP2002  TP_35MIL  [testpoint_35mil]
TP2003  TP_35MIL  [testpoint_35mil]
TVS2002  ESD5B5.0ST1G  [diode2_sod523]

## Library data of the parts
C1101 = CAP_NP: CAP CER 10UF 10V 20% X5R 0603; AGILE_PN: 150-78609; ASSY_OPT: DNP; CAD_APPROVED: Yes; FPLIST: CC0603_OV,CC0603,0603_CC; HEIGHT: 1.016MM; MFG_NAME01: TAIYO YUDEN; MFG_PN01: LMK107BJ106MALTD; ROHS: Yes; VOLTAGE: 10V
C1102 C1104 C1105 C1107 C1108 C1110 C1502 C1504-C1508 C1602 C1604-C1608 C1903 C1905 C2002 C2011 = CAP_NP: CAP CER 0.1UF 25V 10% X5R 0402; AGILE_PN: 150-78633; CAD_APPROVED: Yes; FPLIST: CC0402_25,CC0402_HD,0402_CC; HEIGHT: 0.55MM; MFG_NAME01: YAGEO AMERICA; MFG_PN01: CC0402KRX5R8BB104; ROHS: Yes; Tolerance: 10%; VOLTAGE: 25V
C1103 C1901 C2009 = CAP_NP: CAP CER 10UF 10V 20% X5R 0603; AGILE_PN: 150-78609; CAD_APPROVED: Yes; FPLIST: CC0603_OV,CC0603,0603_CC; HEIGHT: 1.016MM; MFG_NAME01: TAIYO YUDEN; MFG_PN01: LMK107BJ106MALTD; ROHS: Yes; VOLTAGE: 10V
C1106 C2004 = CAP_NP: CAP CER 47uF 10V 20% X5R 0805; AGILE_PN: 150-78979; CAD_APPROVED: Yes; FPLIST: CC0805_OV,CC0805,0805_CC; HEIGHT: 1.45 MM; MFG_NAME01: TDK; MFG_PN01: C2012X5R1A476M125AC; ROHS: Yes; Tolerance: 20%; VOLTAGE: 10V
C1109 C1112 = CAP_NP: CAP CER 4.7UF 10V 10% X5R 0603; AGILE_PN: 150-77975; CAD_APPROVED: Yes; FPLIST: CC0603_OV,CC0603,0603_CC; HEIGHT: 0.9MM; MFG_NAME01: TAIYO YUDEN; MFG_PN01: LMK107BJ475KA-T; ROHS: Yes; Tolerance: 10%; VOLTAGE: 10V
C1111 = CAP_NP: CAP CER 1000pF 1000V 10% X7R 0805; AGILE_PN: 150-78841; CAD_APPROVED: Yes; FPLIST: CC0805_OV,CC0805,0805_CC; HEIGHT: 1.4MM; MFG_NAME01: Kemet; MFG_PN01: C0805C102KDRACTU; ROHS: Yes; Tolerance: 10%; VOLTAGE: 1000V
C1113 = CAP_NP: CAP CER 1uF 16V 10% X5R 0402; AGILE_PN: 150-78973; ASSY_OPT: DNP; CAD_APPROVED: Yes; FPLIST: CC0402_25,CC0402_HD,0402_CC; HEIGHT: 0.55 MM; MFG_NAME01: WALSIN TECHNOLOGY CORP.; MFG_PN01: 0402X105K160CT; ROHS: Yes; Tolerance: 10%; VOLTAGE: 16V
C1114 = CAP_NP: CAP CER 1000PF 50V X7R 5% 0402; AGILE_PN: 150-75774; ASSY_OPT: DNP; CAD_APPROVED: Yes; FPLIST: CC0402_25,CC0402_HD,0402_CC; HEIGHT: 0.6MM; MFG_NAME01: CAPAX TECHNOLOGIES INC.; MFG_PN01: 0402X102J500SNT; ROHS: Yes; Tolerance: 5%; VOLTAGE: 50V
C1115 = CAP_NP: CAP CER 470PF 50V 10% X7R 0402; AGILE_PN: 150-75452; ASSY_OPT: DNP; CAD_APPROVED: Yes; FPLIST: CC0402_25,CC0402_HD,0402_CC; HEIGHT: 0.55MM; MFG_NAME01: MURATA; MFG_PN01: GRM155R71H471KA01D; PRIORITY_PN: 021-00340; ROHS: Yes; ROOM: RGMII_PHY; SIGNAL_MODEL: DEFAULT_CAPACITOR_470pF_2_1; Tolerance: 10%; VOLTAGE: 50V
D1101 = DZ_DUAL_CK_C1C2A: DIODE TVS 1A 5.0V AEC-Q101 SOT-723; AGILE_PN: 480-78836; CAD_APPROVED: Yes; HEIGHT: 0.55MM; MFG_NAME01: On Semiconductor; ROHS: Yes
D1102 D1905 D1906 D2002 = DIODE_SCHTKY: DIODE SCH 200MA 30V AEC-Q101 SOD-523; AGILE_PN: 480-78501; CAD_APPROVED: Yes; HEIGHT: 0.7MM; MFG_NAME01: On Semiconductor; ROHS: Yes
J1101 = USB_A: CON 1X4 RA SHLD TH USB_TYPE_A_FEMALE -- 321H AU 118L; AGILE_PN: 210-80779; CAD_APPROVED: Yes; HEIGHT: 8.15MM; MFG_NAME01: SHENZHEN ATOM TECHNOLOGY CO.,LTD; MFG_PN01: USB304FA-A1005302; ROHS: Yes
J1102 J1901 = MICRO_USB_CONN_11PIN: CON 1X5 MICROUSB_TYPE_B_FEMALE RA SHLD SMT 0.65MM SP 110H AU; AGILE_PN: 211-79712; CAD_APPROVED: Yes; HEIGHT: 2.795MM; MFG_NAME01: SHENZHEN ATOM TECHNOLOGY CO.,LTD; MFG_PN01: USB205FB-C1013203; ROHS: Yes
L1102 L1104 L1901 L2002 L2003 = BEAD_0: IND FER BEAD 120OHM@100MHZ 2A 25% 0603; AGILE_PN: 180-30008; CAD_APPROVED: Yes; FPLIST: IND_0603,0603_CC; HEIGHT: 0.95MM; MFG_NAME01: MURATA; MFG_PN01: BLM18PG121SH1; PART_TYPE: FERRITE; ROHS: Yes; Tolerance: 25%
L1103 L1105 L1902 = DLW43: IND CHK 90 OHM@100MHZ 330MA 25% 0805; AGILE_PN: 180-76336; CAD_APPROVED: Yes; HEIGHT: 1MM; MFG_NAME01: MURATA; MFG_PN01: DLW21HN900SQ2L; PART_TYPE: CHOKE; ROHS: Yes; Tolerance: 25%
Q1101 = MOSFET_P: TRAN PMOS PWR 12V 4.3A SOT23; AGILE_PN: 480-77718; CAD_APPROVED: Yes; HEIGHT: 1.12MM; MFG_NAME01: INTERNATIONAL RECTIFIER; MFG_PN01: IRLML6401TRPBF; ROHS: Yes
Q1102 Q1103 Q2004 = 2SK3018: TRANS MOSFET N-CH 30V .1A SOT-323; AGILE_PN: 480-75317; CAD_APPROVED: Yes; HEIGHT: 0.9MM; MFG_NAME01: ROHM; MFG_PN01: 2SK3018T106; ROHS: Yes
R1101 R1104 R1106 R1111-R1116 R1128 R1129 R1901 R1903 R1904 R1908 = RES: RES MF ZERO OHM 1/16W 5% 0402; AGILE_PN: 470-75394; ASSY_OPT: DNP; CAD_APPROVED: Yes; FPLIST: RC0402_25,RC0402_HD,RC0402_X2,0402_CC; HEIGHT: 0.45 MM; MFG_NAME01: ROHM; MFG_PN01: MCR01MZPJ000; ROHS: Yes; Tolerance: 5%
R1102 R1105 R1119 R2003 = RES: RES MF 100K 1/16W 5% 0402; AGILE_PN: 470-75597; CAD_APPROVED: Yes; FPLIST: RC0402_25,RC0402_HD,0402_CC; HEIGHT: 0.40 MM; MFG_NAME01: KOA SPEER; MFG_PN01: RK73B1ETTP104J; ROHS: Yes; Tolerance: 5%
R1103 R1109 R1118 R1509 R1607 R1905 R1919 R2008 = RES: RES MF 10K 1/16W 5% 0402; AGILE_PN: 470-75557; CAD_APPROVED: Yes; FPLIST: RC0402_25,RC0402_HD,0402_CC; HEIGHT: 0.4 MM; MFG_NAME01: VISHAY INTERTECHNOLOGY; MFG_PN01: CRCW040210K0JNED; ROHS: Yes; Tolerance: 5%
R1107 R1108 R1910-R1914 R1916 R1917 = RES: RES MF 10K 1/16W 5% 0402; AGILE_PN: 470-75557; ASSY_OPT: DNP; CAD_APPROVED: Yes; FPLIST: RC0402_25,RC0402_HD,0402_CC; HEIGHT: 0.4 MM; MFG_NAME01: VISHAY INTERTECHNOLOGY; MFG_PN01: CRCW040210K0JNED; ROHS: Yes; Tolerance: 5%
R1110 R1117 R1120 R1121 R1633-R1636 R1909 = RES: RES MF ZERO OHM 1/16W 5% 0402; AGILE_PN: 470-75394; CAD_APPROVED: Yes; FPLIST: RC0402_25,RC0402_HD,RC0402_X2,0402_CC; HEIGHT: 0.45 MM; MFG_NAME01: ROHM; MFG_PN01: MCR01MZPJ000; ROHS: Yes; Tolerance: 5%
R1122-R1124 R2013 R2014 = RES: RES MF ZERO OHM 1/8W -- 0805; AGILE_PN: 470-75442; CAD_APPROVED: Yes; FPLIST: RC0805_OV,RC0805,RC0805_OV_3P,0805_CC; HEIGHT: 0.7 MM; MFG_NAME01: YAGEO AMERICA; MFG_PN01: RC0805JR-070RL; ROHS: Yes; Tolerance: 5%
R1125 = RES: RES MF 10K 1/16W 5% 0402; AGILE_PN: 470-75557; ASSY_OPT: DNP; CAD_APPROVED: Yes; FPLIST: RC0402_25,RC0402_HD,0402_CC; HEIGHT: 0.4 MM; MFG_NAME01: VISHAY INTERTECHNOLOGY; MFG_PN01: CRCW040210K0JNED; ROHS: Yes; TOL: 5%; Tolerance: 5%
R1126 = RES: RES MF 270K  1/16W 1% 0402; AGILE_PN: 470-31107; ASSY_OPT: DNP; CAD_APPROVED: Yes; FPLIST: RC0402_25,RC0402_HD,0402_CC; HEIGHT: 0.40 MM; MFG_NAME01: KOA SPEER; MFG_PN01: RK73H1ETTP2703F; ROHS: Yes; Tolerance: 1%
R1127 = RES: RES MF 100K 1/16W 1% 0402; AGILE_PN: 470-76240; ASSY_OPT: DNP; CAD_APPROVED: Yes; FPLIST: RC0402_25,RC0402_HD,0402_CC; HEIGHT: 0.4MM; MFG_NAME01: YAGEO AMERICA; MFG_PN01: RC0402FR-07100KL; ROHS: Yes; Tolerance: 1%
TVS1101 TVS2002 = DIODE_TVS_BIDIR: DIODE SUPPRESSOR 16A@30NS 5V@1UA SOD-523; AGILE_PN: 480-76937; CAD_APPROVED: Yes; HEIGHT: 0.7MM; MFG_NAME01: on semiconductor; ROHS: Yes
U1101 = MIC2526_8P: IC LIN SW PWR ACTIVE HIGH DUAL 2.7V-5.5V 0.5A SOIC8; AGILE_PN: 312-75936; CAD_APPROVED: Yes; HEIGHT: 1.73mm; MFG_NAME01: MICREL; ROHS: Yes
U1102 = SRV05-4: DIODE TVS ARRAY 12A 5V 300W SOT23_S6; AGILE_PN: 480-75205; CAD_APPROVED: Yes; HEIGHT: 1.45mm; MFG_NAME01: SEMTECH CORP; MFG_PN01: SRV05-4.TCT; ROHS: Yes
U1103 = MIC5205YM5_5P: IC LIN VREG LDO  1.5-15V 150MA 2.5-16V SOT23-5; AGILE_PN: 315-75304; ASSY_OPT: DNP; CAD_APPROVED: Yes; HEIGHT: 1.30MM; MFG_NAME01: MICREL; MFG_PN01: MIC5205YM5; ROHS: Yes
C1501 C1503 C1601 C1603 = CAP_NP: CAP CER 22UF 6.3V 20% X5R 0603; AGILE_PN: 150-78467; CAD_APPROVED: Yes; FPLIST: CC0603_OV,CC0603,0603_CC; HEIGHT: 1MM; MFG_NAME01: Samsung; MFG_PN01: CL10A226MQ8NRNE; ROHS: Yes; Tolerance: 20%; VOLTAGE: 6.3V; voltage rating: 6.3V
L1501 L1601 = INDUCTOR_FERRITE: IND FER BEAD 470 OHM@100MHZ 1A 25% 0603; AGILE_PN: 180-77776; CAD_APPROVED: Yes; FPLIST: IND_0603,IND0603_CC; HEIGHT: 0.95MM; MFG_NAME01: murata; MFG_PN01: BLM18PG471SN1D; PART_TYPE: FERRITE\BEAD; ROHS: Yes; Tolerance: 25%
R1501 R1504 R1508 R1518 R1519 R1523 R1524 R1530-R1532 R1534 R1606 R1615 R1616 R1621 R1622 R1626 R1628-R1630 R1632 R1906 R1907 R2004 R2005 = RES: RES MF 1.0K 1/16W 5% 0402; AGILE_PN: 470-75555; CAD_APPROVED: Yes; FPLIST: RC0402_25,RC0402_HD,RC0402_X2,0402_CC; HEIGHT: 0.41mm; MFG_NAME01: VISHAY INTERTECHNOLOGY; MFG_PN01: CRCW04021K00JNED; ROHS: Yes; Tolerance: 5%
R1505 R1507 R1603 R1605 = RES: RES MF 220 OHM 1/16W 5% 0402; AGILE_PN: 470-75607; CAD_APPROVED: Yes; FPLIST: RC0402_25,RC0402_HD,0402_CC; HEIGHT: 0.45mm; MFG_NAME01: KOA SPEER; MFG_PN01: RK73B1ETTP221J; ROHS: Yes; Tolerance: 5%
R1515 R1613 = RES: RES MF 6.49K  1/16W 1% 0402; AGILE_PN: 470-30927; CAD_APPROVED: Yes; FPLIST: RC0402_25,RC0402_HD,0402_CC; HEIGHT: 0.40 MM; MFG_NAME01: KOA SPEER; MFG_PN01: RK73H1ETTP6491F; ROHS: Yes; Tolerance: 1%
R1516 R1521 R1526 R1527 R1533 R1618 R1619 R1624 R1625 R1627 R1631 = RES: RES MF 4.7K 1/16W 5% 0402; AGILE_PN: 470-75626; ASSY_OPT: DNP; CAD_APPROVED: Yes; FPLIST: RC0402_25,RC0402_HD,0402_CC; HEIGHT: 0.41mm; MFG_NAME01: KOA SPEER; MFG_PN01: RK73B1ETTP472J; ROHS: Yes; Tolerance: 5%
R1517 R1522 R1528 R1617 R1620 R2010 = RES: RES MF 1.0K 1/16W 5% 0402; AGILE_PN: 470-75555; ASSY_OPT: DNP; CAD_APPROVED: Yes; FPLIST: RC0402_25,RC0402_HD,RC0402_X2,0402_CC; HEIGHT: 0.41mm; MFG_NAME01: VISHAY INTERTECHNOLOGY; MFG_PN01: CRCW04021K00JNED; ROHS: Yes; Tolerance: 5%
R1520 R1525 R1529 R1614 R1623 = RES: RES MF 4.7K 1/16W 5% 0402; AGILE_PN: 470-75626; CAD_APPROVED: Yes; FPLIST: RC0402_25,RC0402_HD,0402_CC; HEIGHT: 0.41mm; MFG_NAME01: KOA SPEER; MFG_PN01: RK73B1ETTP472J; ROHS: Yes; Tolerance: 5%
TP1501 TP1601 TP1901-TP1906 TP2001-TP2003 = T_POINT_R: TEST POINT PAD .035 SMT, no part to order; AGILE_PN: 510-75618; CAD_APPROVED: Yes; HEIGHT: 0.1MM; ROHS: Yes
TP1502 TP1503 TP1602 = TESTLOOP: TEST POINT PAD 15MIL DIA SMT, NO PART TO ORDER; AGILE_PN: 211-76645; CAD_APPROVED: Yes; HEIGHT: 0.1MM; MFG_NAME01: NOTACOMPONENT; MFG_PN01: NOTACOMPONENT; ROHS: Yes
U1501 U1601 = KSZ8081RNB_32P: IC XCVR 10/100M EPHY 3.3V QFN32; AGILE_PN: 312-81089; CAD_APPROVED: Yes; HEIGHT: 0.9MM; MFG_NAME01: Micrel; MFG_PN01: KSZ8081RNBIA; ROHS: Yes
U1502 U1602 = SRV05-4: DIODE TVS ARRAY 12A 5V 300W SOT23_S6; AGILE_PN: 480-75205; ASSY_OPT: DNP; CAD_APPROVED: Yes; HEIGHT: 1.45mm; MFG_NAME01: SEMTECH CORP; MFG_PN01: SRV05-4.TCT; ROHS: Yes
J1501 = RJ45_MAG_LED_24P: CON RJ45 DUAL SHLD RA TH 50MIL SP 609H AU 120L; AGILE_PN: 210-80770; CAD_APPROVED: Yes; HEIGHT: 15.46 MM; MFG_NAME01: HanRun Electronics Co., Ltd; MFG_PN01: HY911205C; ROHS: Yes
C1902 = CAP_NP: CAP CER 4.7UF 6.3V 20% X5R 0402; AGILE_PN: 150-78463; CAD_APPROVED: Yes; FPLIST: CC0402_25,CC0402_HD,0402_CC; HEIGHT: 0.65MM; MFG_NAME01: TDK; MFG_PN01: C1005X5R0J475M050BC; ROHS: Yes; Tolerance: 20%; VOLTAGE: 6.3V; voltage rating: 6.3V
C1904 = CAP_NP: CAP CER 0.22UF 10V 10% X5R 0402; AGILE_PN: 150-77358; CAD_APPROVED: Yes; FPLIST: CC0402_25,CC0402_HD,0402_CC; HEIGHT: 0.55MM; MFG_NAME01: MURATA; MFG_PN01: GRM155R61A224KE19B; ROHS: Yes; Tolerance: 10%; VOLTAGE: 10V
D1901 = DZ_DUAL_CK_C1C2A: DIODE TVS 1A 5.0V AEC-Q101 SOT-723; AGILE_PN: 480-78836; ASSY_OPT: DNP; CAD_APPROVED: Yes; HEIGHT: 0.55MM; MFG_NAME01: On Semiconductor; ROHS: Yes
D1903 = LED4_DUAL_OG: LED BI-COLOR ORANGE/GRN 20MA SMD 0606; AGILE_PN: 370-76616; CAD_APPROVED: Yes; HEIGHT: 0.7MM; MFG_NAME01: DIALIGHT; MFG_PN01: 598-8430-207CF; ROHS: Yes
J1902 = CONN_HDR_10X2: CON 2X10 PLUG SHRD TH 100MIL CTR 366H AU 118L; AGILE_PN: 210-80775; CAD_APPROVED: Yes; HEIGHT: 9.3MM; MFG_NAME01: SHENZHEN ATOM TECHNOLOGY CO.,LTD; ROHS: Yes
R1915 = RES: RES MF 100 OHM 1/16W 5% 0402; AGILE_PN: 470-75591; CAD_APPROVED: Yes; FPLIST: RC0402_25,RC0402_HD,RC0402_X2,0402_CC; HEIGHT: 0.45mm; MFG_NAME01: VENKEL COMPANY; MFG_PN01: CR040216W101JT; ROHS: Yes; Tolerance: 5%
TVS1901 = DIODE_TVS_BIDIR: DIODE SUPPRESSOR 16A@30NS 5V@1UA SOD-523; AGILE_PN: 480-76937; ASSY_OPT: DNP; CAD_APPROVED: Yes; HEIGHT: 0.7MM; MFG_NAME01: on semiconductor; ROHS: Yes
U1901 = CP2102: IC USB-TO-UART BRIDGE 3.3V QFN28; AGILE_PN: 312-75932; CAD_APPROVED: Yes; HEIGHT: 1MM; MFG_NAME01: SILICON LABORATORIES; MFG_PN01: CP2102-GM; ROHS: Yes
U1902 = SN74LVC2G126DCTR: IC BUF DUAL TS 1.65-5.5V SSOP8; AGILE_PN: 312-80905; CAD_APPROVED: Yes; HEIGHT: 1.30 MM; MFG_NAME01: TEXAS INSTRUMENTS; ROHS: Yes
C2001 C2006 = CAP_NP: CAP CER 0.1UF 25V 10% X5R 0402; AGILE_PN: 150-78633; CAD_APPROVED: Yes; FPLIST: CC0402_25,CC0402_HD,0402_CC; HEIGHT: 0.55MM; MFG_NAME01: YAGEO AMERICA; MFG_PN01: CC0402KRX5R8BB104; ROHS: Yes; TOL: 10%; Tolerance: 10%; VOLTAGE: 25V
C2003 = CAP_NP: CAP CER 1.0UF 10V 10% X5R 0402; AGILE_PN: 150-75772; CAD_APPROVED: Yes; FPLIST: CC0402_25,CC0402_HD,0402_CC; HEIGHT: 0.6MM; MFG_NAME01: YAGEO AMERICA; MFG_PN01: CC0402KRX5R6BB105; ROHS: Yes; VOLTAGE: 10V
C2005 = CAP_NP: CAP CER 0.01UF 50V 10% X7R 0402; AGILE_PN: 150-30114; CAD_APPROVED: Yes; FPLIST: CC0402_25,CC0402_HD,0402_CC; HEIGHT: 0.74 MM; MFG_NAME01: WALSIN TECHNOLOGY CORP.; MFG_PN01: 0402B103K500CT; ROHS: Yes; Tolerance: 10%; VOLTAGE: 50V
D2001 = ZDIODE: DIODE ZNR -- 0.2W 5.1V AEC-Q101 SOD523; AGILE_PN: 480-77217; CAD_APPROVED: Yes; HEIGHT: 0.7MM; MFG_NAME01: ON SEMICONDUCTOR; ROHS: Yes
D2003 = LED_DUAL_SEP_RG: LED RED GRN DUAL 30/25MA SMT; AGILE_PN: 370-75097; CAD_APPROVED: Yes; HEIGHT: 1.1MM; MFG_NAME01: KINGBRIGHT; MFG_PN01: APB3025ESGC-F01; ROHS: Yes
J2001 = PHONEJACK-3: CON 1 PWR PLUG RA TH 2.5A 20V -- 441H SN/NI; AGILE_PN: 210-80780; CAD_APPROVED: Yes; HEIGHT: 11.2MM; MFG_NAME01: SHENZHEN ATOM TECHNOLOGY CO.,LTD; MFG_PN01: DC060024202; ROHS: Yes
J2002 = HDR_1X2_TH: HDR 1X2 TH 100MIL SP 461H SN; AGILE_PN: 210-76455; ASSY_OPT: DNP; CAD_APPROVED: Yes; HEIGHT: 11.7MM; MFG_NAME01: MOLEX; MFG_PN01: 22-27-2021; ROHS: Yes
JP2001 = JUMPER1x2: CON 2 JUMPER MALE 2.54MM SP 157H AU; AGILE_PN: 210-30004; ASSY_OPT: DNP; CAD_APPROVED: Yes; HEIGHT: 4MM; MFG_NAME01: PRECI-DIP CONNECTION TECHNOLOGY; MFG_PN01: 999-11-110-10; ROHS: Yes
Q2001 = PNP: TRAN PNP GEN AMP 200MA 40V AEC-Q101 SC75; AGILE_PN: 480-78465; CAD_APPROVED: Yes; HEIGHT: 0.9 MM; MFG_NAME01: ON SEMICONDUCTOR; ROHS: Yes
Q2002 Q2003 = FDMA530PZ: TRAN PMOS PWR 30V 6.8A; AGILE_PN: 480-77039; CAD_APPROVED: Yes; HEIGHT: 0.8MM; MFG_NAME01: FAIRCHILD; ROHS: Yes
R2001 R2012 = RES: RES MF 3.3K 1/10W 5% 0603; AGILE_PN: 470-75402; CAD_APPROVED: Yes; FPLIST: RC0603_OV,RC0603,0603_CC; HEIGHT: 0.6MM; MFG_NAME01: KOA SPEER; MFG_PN01: RK73B1JTTD332J; ROHS: Yes; Tolerance: 5%
R2002 = RES: RES MF 10K 1/16W 5% 0402; AGILE_PN: 470-75557; CAD_APPROVED: Yes; FPLIST: RC0402_25,RC0402_HD,0402_CC; HEIGHT: 0.4 MM; MFG_NAME01: VISHAY INTERTECHNOLOGY; MFG_PN01: CRCW040210K0JNED; ROHS: Yes; TOL: 5%; Tolerance: 5%
R2006 = RES: RES MF 2.2K 1/10W 5% 0603; AGILE_PN: 470-75399; CAD_APPROVED: Yes; FPLIST: RC0603_OV,RC0603,0603_CC; HEIGHT: 0.55MM; MFG_NAME01: VENKEL COMPANY; MFG_PN01: CR0603-10W-222JT; ROHS: Yes; Tolerance: 5%
R2007 R2011 = RES: RES MF 100K 1/16W 5% 0402; AGILE_PN: 470-75597; ASSY_OPT: DNP; CAD_APPROVED: Yes; FPLIST: RC0402_25,RC0402_HD,0402_CC; HEIGHT: 0.40 MM; MFG_NAME01: KOA SPEER; MFG_PN01: RK73B1ETTP104J; ROHS: Yes; Tolerance: 5%
R2009 = RES: RES MF 100K 1/16W 5% 0402; AGILE_PN: 470-75597; CAD_APPROVED: Yes; FPLIST: RC0402_25,RC0402_HD,0402_CC; HEIGHT: 0.40 MM; MFG_NAME01: KOA SPEER; MFG_PN01: RK73B1ETTP104J; ROHS: Yes; TOL: 5%; Tolerance: 5%
R2015 R2016 = RES: RES MF ZERO OHM 1/8W -- 0805; AGILE_PN: 470-75442; ASSY_OPT: DNP; CAD_APPROVED: Yes; FPLIST: RC0805_OV,RC0805,RC0805_OV_3P,0805_CC; HEIGHT: 0.7 MM; MFG_NAME01: YAGEO AMERICA; MFG_PN01: RC0805JR-070RL; ROHS: Yes; Tolerance: 5%
SW2001 = SW_DPDT_3: SW DPDT SLD 0.1A 12V L=4 TH; AGILE_PN: 510-77598; CAD_APPROVED: Yes; HEIGHT: 9.5MM; MFG_NAME01: E SWITCH; ROHS: Yes

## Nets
GND: C1101.2 C1102.2 C1103.2 C1104.2 C1105.2 C1106.2 C1107.2 C1108.2 C1109.2 C1110.2 C1111.2 C1112.2 C1113.2 C1114.2 C1115.2 C1501.2 C1502.2 C1503.2 C1504.2 C1505.2 C1506.2 C1507.2 C1508.2 C1601.2 C1602.2 C1603.2 C1604.2 C1605.2 C1606.2 C1607.2 C1608.2 C1901.2 C1902.2 C1903.2 C1904.2 C1905.2 C2001.2 C2002.2 C2003.2 C2004.2 C2006.2 C2009.2 C2011.2 D1101.3(ANODE) D1901.3(ANODE) D2001.A(ANODE) D2003.4(CATHODE2) J1101.A4(GND) J1102.5(GND) J1901.5(GND) J1902.4 J1902.6 J1902.8 J1902.10 J1902.12 J1902.14 J1902.16 J1902.18 J1902.20 J2001.2 J2001.3 J2002.2 L2003.1 Q1102.1(SOURCE) Q1103.1(SOURCE) Q2003.3(G) Q2004.1(SOURCE) R1105.2 R1107.2 R1108.2 R1122.2 R1123.2 R1124.2 R1127.2 R1515.2 R1517.2 R1518.2 R1519.2 R1522.2 R1523.2 R1524.2 R1528.2 R1530.2 R1531.2 R1532.2 R1534.2 R1613.2 R1615.2 R1616.2 R1617.2 R1620.2 R1621.2 R1622.2 R1626.2 R1628.2 R1629.2 R1630.2 R1632.2 R1904.1 R1916.2 R1917.2 R1919.2 R2009.2 R2011.2 SW2001.3(NO1) SW2001.6(NO2) TP1906.1(TP) TP2003.1(TP) TVS1101.1(A1) TVS1901.1(A1) TVS2002.1(A1) U1101.6(GND) U1102.2(GND) U1103.2(GND) U1501.1(GND) U1501.33(PADDLE) U1502.2(GND) U1601.1(GND) U1601.33(PADDLE) U1602.2(GND) U1901.3(GND) U1901.29(EPAD) U1902.4(GND) ; also on sheet 3 4 5 6 7 8 12 18
GND_CHASSIS: C1111.1 J1101.S1(SGND1) J1101.S2(SGND2) J1102.S1 J1102.S2 J1102.S3 J1102.S4 J1102.S5 J1102.S6 J1501.P8A(GND_A) J1501.P8B(GND_B) J1501.SH1 J1501.SH2 J1501.SH3 R1122.1 R1123.1 R1124.1
VBUS_CP210x: C1901.1 C1905.1 L1901.2 U1901.7(REGIN) U1901.8(VBUS)
VBUS_DGB: J1901.1(VBUS) L1901.1 R2015.1 R2016.1 TVS1901.2(A2)
VDDCO_1_1V8: C1503.1 C1504.1 U1501.2(VDD_1.2)
VDDCO_2_1V8: C1603.1 C1604.1 U1601.2(VDD_1.2)
DC_5V_IN: C2001.1 J2001.1 J2002.1 Q2003.1(D1) Q2003.2(D2) Q2003.5(D5) Q2003.6(D6) Q2003.7(D7) R2004.1 R2013.1 R2014.1 R2015.2 R2016.2 TP2001.1(TP)
DCDC_3V3: C1904.1 D1906.A J1902.2 R1103.2 R1109.1 R1118.1 R1119.1 R1905.1 R1910.1 R1912.1 R1913.1 R1914.1 R1915.1 TP1905.1(TP) U1902.8(VCC) ; also on sheet 3 4 8 12 18
DCDC_5V: C1106.1 C1107.1 C2009.1 C2011.1 L2002.2 U1101.7(IN) ; also on sheet 7 12 18
ECSPI4_MISO: R1636.1 ; also on sheet 3 8 18
ECSPI4_MOSI: R1635.1 ; also on sheet 3 8 18
ECSPI4_SCLK: R1634.1 ; also on sheet 3 8 18
ECSPI4_SS0: R1633.1 ; also on sheet 3 8 18
ENET1_B-CAST-OFF: R1533.1 TP1501.1(TP) U1501.19(REF_CLK/B-CAST_OFF)
ENET1_CONFIG0: R1522.1 R1525.1 U1501.28(CONFIG0)
ENET1_CONFIG1: R1523.1 R1526.1 U1501.29(CONFIG1)
ENET1_CRS_DV: R1524.1 R1527.1 U1501.18(CRS_DV/CONFIG2) ; also on sheet 3
ENET1_LED0/NWAYEN: R1505.1 R1530.1 U1501.30(LED0/NWAYEN)
ENET1_LED1/SPEED: R1507.1 R1531.1 U1501.31(LED1/SPEED)
ENET1_nINT: R1508.2 R1534.1 U1501.21(INTRP/~{NAND_TREE}) ; also on sheet 3
ENET1_nRST: C1508.1 C1608.1 R1509.2 R1607.2 U1501.32(~{RST}) U1601.32(~{RST}) ; also on sheet 3
ENET1_PHYAD0: R1516.1 R1519.1 U1501.13(PHYAD0)
ENET1_PHYAD1: R1517.1 R1520.1 U1501.14(PHYAD1)
ENET1_RXD0: R1532.1 U1501.16(RXD0/DUPLEX) ; also on sheet 3
ENET1_RXD1: R1518.1 R1521.1 U1501.15(RXD1/PHYAD2) ; also on sheet 3
ENET1_RXER: R1528.1 R1529.1 U1501.20(RXER/ISO) ; also on sheet 3
ENET1_TX_CLK: TP1502.1(Pin1) U1501.9(XI) ; also on sheet 3
ENET1_TXD0: TP1503.1(Pin1) U1501.24(TXD0) ; also on sheet 3
ENET1_TXD1: U1501.25(TXD1) ; also on sheet 3
ENET1_TXEN: U1501.23(TXEN) ; also on sheet 3
ENET2_B-CAST-OFF: R1631.1 TP1601.1(TP) U1601.19(REF_CLK/B-CAST_OFF)
ENET2_CONFIG0: R1620.1 R1623.1 U1601.28(CONFIG0)
ENET2_CONFIG1: R1621.1 R1624.1 U1601.29(CONFIG1)
ENET2_CRS_DV: R1622.1 R1625.1 U1601.18(CRS_DV/CONFIG2) ; also on sheet 3
ENET2_ISO: R1626.1 R1627.1 R1633.2 U1601.20(RXER/ISO)
ENET2_LED0/NWAYEN: R1603.1 R1628.1 U1601.30(LED0/NWAYEN)
ENET2_LED1/SPEED: R1605.1 R1629.1 U1601.31(LED1/SPEED)
ENET2_nINT: R1606.2 R1632.1 U1601.21(INTRP/~{NAND_TREE}) ; also on sheet 3
ENET2_PHYAD0: R1614.1 R1617.1 U1601.13(PHYAD0)
ENET2_PHYAD1: R1615.1 R1618.1 U1601.14(PHYAD1)
ENET2_RXD0: R1630.1 U1601.16(RXD0/DUPLEX) ; also on sheet 3
ENET2_RXD1: R1616.1 R1619.1 U1601.15(RXD1/PHYAD2) ; also on sheet 3
ENET2_TXD0: TP1602.1(Pin1) U1601.24(TXD0) ; also on sheet 3
ENET_MDC: R1504.2 U1501.12(MDC) U1601.12(MDC) ; also on sheet 3
ENET_MDIO: R1501.2 U1501.11(MDIO) U1601.11(MDIO) ; also on sheet 3
ETH1_RXM: J1501.P6A U1501.4(RXM) U1502.3(I/O3)
ETH1_RXP: J1501.P3A U1501.5(RXP) U1502.1(I/O1)
ETH1_TXM: J1501.P2A U1501.6(TXM) U1502.4(I/O4)
ETH1_TXP: J1501.P1A U1501.7(TXP) U1502.6(I/O6)
ETH2_RXM: J1501.P6B U1601.4(RXM) U1602.3(I/O3)
ETH2_RXP: J1501.P3B U1601.5(RXP) U1602.1(I/O1)
ETH2_TXM: J1501.P2B U1601.6(TXM) U1602.4(I/O4)
ETH2_TXP: J1501.P1B U1601.7(TXP) U1602.6(I/O6)
JTAG_DACK: J1902.19 R1919.1
JTAG_DE: J1902.17 R1910.2
JTAG_nSRST: D1905.C J1902.15 R1911.2
JTAG_nTRST: J1902.3 R1914.2 ; also on sheet 3 5
JTAG_RTCK: J1902.11 R1917.1
JTAG_TCK: J1902.9 R1916.1 ; also on sheet 3 5
JTAG_TDI: J1902.5 R1913.2 ; also on sheet 3 5
JTAG_TDO: J1902.13 ; also on sheet 3 5
JTAG_TMS: J1902.7 R1912.2 ; also on sheet 3 5
JTAG_VREF: J1902.1 R1915.2
nSLEEP: R1909.1 U1901.11(~{SUSPEND})
POR_B: D1905.A ; also on sheet 3 18
SLEEP: R1908.1 U1901.12(SUSPEND)
UART1_RXD: R1905.2 TP1904.1(TP) U1902.6(1Y) ; also on sheet 3
UART1_TXD: TP1903.1(TP) U1902.5(2A) ; also on sheet 3
USB_DBG_DM: L1902.2 R1901.2 U1901.5(D-)
USB_DBG_DM_CN: D1901.2(CATHODE2) J1901.2(D-) L1902.1 R1901.1
USB_DBG_DP: L1902.3 R1903.2 U1901.4(D+)
USB_DBG_DP_CN: D1901.1(CATHODE1) J1901.3(D+) L1902.4 R1903.1
USB_HOST_DN: D1101.1(CATHODE1) J1101.A2(DATA+) L1103.2 R1104.2
USB_HOST_DP: D1101.2(CATHODE2) J1101.A3(DATA-) L1103.3 R1106.2
USB_HOST_VBUS: C1108.1 L1102.1 U1101.5(OUTB) ; also on sheet 3
USB_OTG1_DN: L1105.1 R1111.1 ; also on sheet 3
USB_OTG1_DP: L1105.4 R1112.1 ; also on sheet 3
USB_OTG1_ID: Q1103.2(GATE) R1109.2 R1110.1 ; also on sheet 3 18
USB_OTG1_OC: R1115.2 ; also on sheet 3 8 18
USB_OTG1_PWR: C2006.1 R1113.1 R2010.2 ; also on sheet 3 8 18
USB_OTG1_VBUS: C1101.1 C1102.1 Q1101.3(DRAIN) R1101.1 R1128.2 ; also on sheet 3
USB_OTG2_DN: L1103.1 R1104.1 ; also on sheet 3
USB_OTG2_DP: L1103.4 R1106.1 ; also on sheet 3
USB_OTG2_OC: R1116.2 ; also on sheet 3 8 18
USB_OTG2_PWR: R1114.1 ; also on sheet 3 8 18
USB_OTG_DN: J1102.2(D-) L1105.2 R1111.2 U1102.6(I/O6)
USB_OTG_DP: J1102.3(D+) L1105.3 R1112.2 U1102.4(I/O4)
USB_OTG_VBUS: J1102.1(VBUS) L1104.2 U1102.1(I/O1)
USB_RXD: R1907.2 U1901.25(RXD) U1902.3(2Y)
USB_TXD: R1906.2 U1901.26(TXD) U1902.2(1A)
VENET_3V3: C1505.1 C1605.1 J1501.9A(D1A) J1501.9B(D1B) J1501.11A(D3A) J1501.11B(D3B) L1501.1 L1601.1 R1501.1 R1504.1 R1508.1 R1509.1 R1516.2 R1520.2 R1521.2 R1525.2 R1526.2 R1527.2 R1529.2 R1533.2 R1606.1 R1607.1 R1614.2 R1618.2 R1619.2 R1623.2 R1624.2 R1625.2 R1627.2 R1631.2 U1501.17(VDDIO) U1601.17(VDDIO) ; also on sheet 3 4 5 6 7 18
VSYS: C2002.1 C2003.1 C2004.1 JP2001.2 L2002.1 Q2002.1(D1) Q2002.2(D2) Q2002.5(D5) Q2002.6(D6) Q2002.7(D7) R2005.1 R2007.1 TP2002.1(TP) TVS2002.2(A2) ; also on sheet 3 4 5 8
VUSB_UART_3V3: C1902.1 C1903.1 D1903.1(ANODE1) D1903.3(ANODE2) U1901.6(VDD)
WALL_OV_BASE: Q2001.1(B) R2002.2
WALL_OV_CTL: D2001.C(CATHODE) R2001.2 R2002.1
WALL_OVP_LED: D2002.A Q2001.3(C) R2008.1
N95315917: C1501.1 C1502.1 L1501.2 U1501.3(VDDA_3.3)
N95316217: R1515.1 U1501.10(REXT)
N95316788: C1506.1 J1501.P5A
N95316794: C1507.1 J1501.P4A
N97050984: Q1101.1(GATE) Q1102.3(DRAIN) R1102.2
N97051024: C1105.1 Q1102.2(GATE) R1103.1 R1105.1
N97051721: J1102.4(ID) R1110.2 U1102.3(I/O3)
N97051725: C1109.1 C1110.1 C1113.1 D1102.A L1104.1 R1125.1 R1129.2 U1101.8(OUTA) U1103.1(IN)
N97051938: D1102.C Q1101.2(SOURCE) R1101.2 R1102.1 R1129.1
N97085045: R1115.1 R1120.2 U1101.2(\\~{FLGA})
N97085099: R1107.1 R1114.2 R1118.2 R1121.1 U1101.4(ENB)
N97085121: R1108.1 R1113.2 R1117.2 R1120.1 U1101.1(ENA)
N97085690: C1103.1 C1104.1 J1101.A1(VCC) L1102.2 TVS1101.2(A2)
N97190616: C2005.2 D2002.C Q2002.3(G) R2003.2 R2006.1
N97190709: C2005.1 JP2001.1 Q2001.2(E) Q2002.4(S1) Q2002.8(S2) Q2003.4(S1) Q2003.8(S2) R2001.1 R2003.1 R2013.2 R2014.2
N97193542: D2003.3(ANODE2) R2005.2
N97194205: D2003.2(CATHODE1) Q2004.3(DRAIN)
N97195087: D2003.1(ANODE1) R2004.2
N97195984: Q2004.2(GATE) R2008.2 R2009.1
N97197821: R2007.2 R2010.1 R2011.1
N97206924: C1601.1 C1602.1 L1601.2 U1601.3(VDDA_3.3)
N97207164: R1613.1 U1601.10(REXT)
N97207545: R1636.2 U1601.9(XI)
N97327737: TP1901.1(TP) U1901.9(~{RST})
N97332896: R1908.2 R1909.2 U1902.1(1OE) U1902.7(2OE)
N97333780: R1904.2 U1901.14(NC3)
N97334203: TP1902.1(TP) U1901.10(NC1)
N97721105: J1901.S1 J1901.S2 J1901.S3 J1901.S4 J1901.S5 J1901.S6 L2003.2
N97797261: R1116.1 R1121.2 U1101.3(\\~{FLGB})
N98059204: D1906.C R1911.1
N98377066: R2012.2 SW2001.5(COMMON2)
N98377098: R2006.2 R2012.1
N98583961: Q1103.3(DRAIN) R1117.1 R1119.2
N98661532: R1634.2 U1601.25(TXD1)
N98661566: R1635.2 U1601.23(TXEN)
N98803637: D1903.4(CATHODE2) R1907.1
N98803640: D1903.2(CATHODE1) R1906.1
N98827737: J1501.12A(D4A) R1507.2
N98827800: J1501.10A(D2A) R1505.2
N98829436: J1501.12B(D4B) R1605.2
N98829451: J1501.10B(D2B) R1603.2
N98829499: C1607.1 J1501.P4B
N98829505: C1606.1 J1501.P5B
N99086135: C1114.1 R1125.2 U1103.3(EN)
N99086182: C1115.1 R1126.2 R1127.1 U1103.4(ADJ)
N99086321: C1112.1 R1126.1 R1128.1 U1103.5(OUT)

Not connected (* = marked no-connect by the designer): J1501 P7A(NC_A) P7B(NC_B); J1901 4(ID); SW2001 1(NC1)* 2(COMMON1)* 4(NC2)*; U1102 5(VCC); U1501 8(XO) 22(NC1) 26(NC2) 27(NC3); U1502 5(VCC); U1601 8(XO) 22(NC1) 26(NC2) 27(NC3); U1602 5(VCC); U1901 1(DCD) 2(RI) 13(NC2) 15(NC4) 16(NC5) 17(NC6) 18(NC7) 19(NC8) 20(NC9) 21(NC10) 22(NC11) 23(CTS) 24(RTS) 27(DSR) 28(DTR)

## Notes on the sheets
sheet 13
- 100M ETHERNET RMII PHY x1
- PHY PWR
- Software power-down mode:
  VDDA_3.3:  1.36mA
  VDDIO:     0.45mA
- # VDDIO: 3.3V/2.5V/1.8V
- Ipu/O
- Ipd/O
- Ipd/O
- Ipu/O
- Ipd/O
- Ipd/O
- Ipd/O
- I
- I
- I
- Ipu/O
- Ipu/O
- Ipu/Opu
- Ipd/O
- Ipd/O
- Ipd/O
- RMII CFG
- # CFG
- Description
- # CFG
- Description
- PHYAD[2:0]
- PHY ADDR
- DUPLEX mode
- Ipu/O
- 00-XXX (00001 DEFAULT)
- DUPLEX
- Pull-up  (defaule) = Half Duplex
  Pull-down = Full Duplex
- Ipd/O
- Ipd/O
- IF MODE
- CONFIG[2:0]
- 001 RMII
  101 RMII Back-to-Back
  xxx Reserved-not used
- Nway Auto-Negotiation
- NWAYEN
- Pull-up  (defaule) = Enable
  Pull-down = Disable
- ESD PROTECTION
- Ipd/O
- Ipd/O
- Ipd/O
- ISOLATE mode
- Broadcast Off - for PHY Address 0
- # 2rd LEVEL ESD
- Ipd/O
- ISO
- Pull-up =  Enable
  Pull-down (defaule) = Disable
- B_CAST_OFF
- Pull-up = PHY Address 0 set as unique PHY addr
  Pull-down (default) = PHY Address 0 set as broadcast PHY addr
- Ipu/O
- Ipu/O
- Ipu/O
- Ipd/O
- SPEED mode
- NAND Tree Mode
- Ipu/Opu
- SPEED
- Pull-up  (defaule) =  100Mbps
  Pull-down = 10Mbps
- NAND_TREE#
- Pull-up  (defaule) = Disable
  Pull-down =  Enable
sheet 14
- 100M ETHERNET RMII PHY x2
- # VDDIO: 3.3V/2.5V/1.8V
- Ipu/O
- Ipd/O
- Ipd/O
- Ipu/O
- Ipd/O
- Ipd/O
- Ipd/O
- I
- I
- I
- Ipu/O
- Ipu/O
- Ipu/Opu
- Ipd/O
- Ipd/O
- Ipd/O
- MUX with LCD SPI IF
- RMII CFG
- # CFG
- Description
- # CFG
- Description
- PHYAD[2:0]
- PHY ADDR
- DUPLEX mode
- Ipu/O
- 00-XXX (00001 DEFAULT)
- DUPLEX
- Pull-up  (defaule) = Half Duplex
  Pull-down = Full Duplex
- Ipd/O
- Ipd/O
- IF MODE
- CONFIG[2:0]
- 001 RMII
  101 RMII Back-to-Back
  xxx Reserved-not used
- Nway Auto-Negotiation
- ESD PROTECTION
- NWAYEN
- Pull-up  (defaule) = Enable
  Pull-down = Disable
- Ipd/O
- Ipd/O
- # 2rd LEVEL ESD
- Ipd/O
- ISOLATE mode
- Broadcast Off - for PHY Address 0
- Ipd/O
- ISO
- Pull-up =  Enable
  Pull-down (defaule) = Disable
- B_CAST_OFF
- Pull-up = PHY Address 0 set as unique PHY addr
  Pull-down (default) = PHY Address 0 set as broadcast PHY addr
- Ipu/O
- Ipu/O
- Ipu/O
- Ipd/O
- SPEED mode
- NAND Tree Mode
- Ipu/Opu
- SPEED
- Pull-up  (defaule) =  100Mbps
  Pull-down = 10Mbps
- NAND_TREE#
- Pull-up  (defaule) = Disable
  Pull-down =  Enable
sheet 15
- SYS PWR
- SYS_3V7 POK LED(GRN)
- Over-Voltage LED(RED)
- # RSV for ADC TEST
sheet 16
- UART-USB DBG / JTAG
- USB-UART Bridge
- # Level-Shifter to insure no IO backfeed
- JTAG
- JTAG_PWR
sheet 17
- USB HOST/OTG
- USB Client PWR
- Ra
- Rb
- Need to use MIC5225 for
  ceramic output cap.
  Max output current from
  MIC5225 is 150mA
- Vo = 1.24V x (1+Ra/Rb)
- This block is reserved for USB OTG certification test.
- USB HOST
- # MUX with Touch Screen
- # MUX with Touch Screen
- # CPU Internal PU
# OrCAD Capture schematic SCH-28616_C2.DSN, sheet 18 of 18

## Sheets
18 M-09 SD/BT/ARDUINO: size C

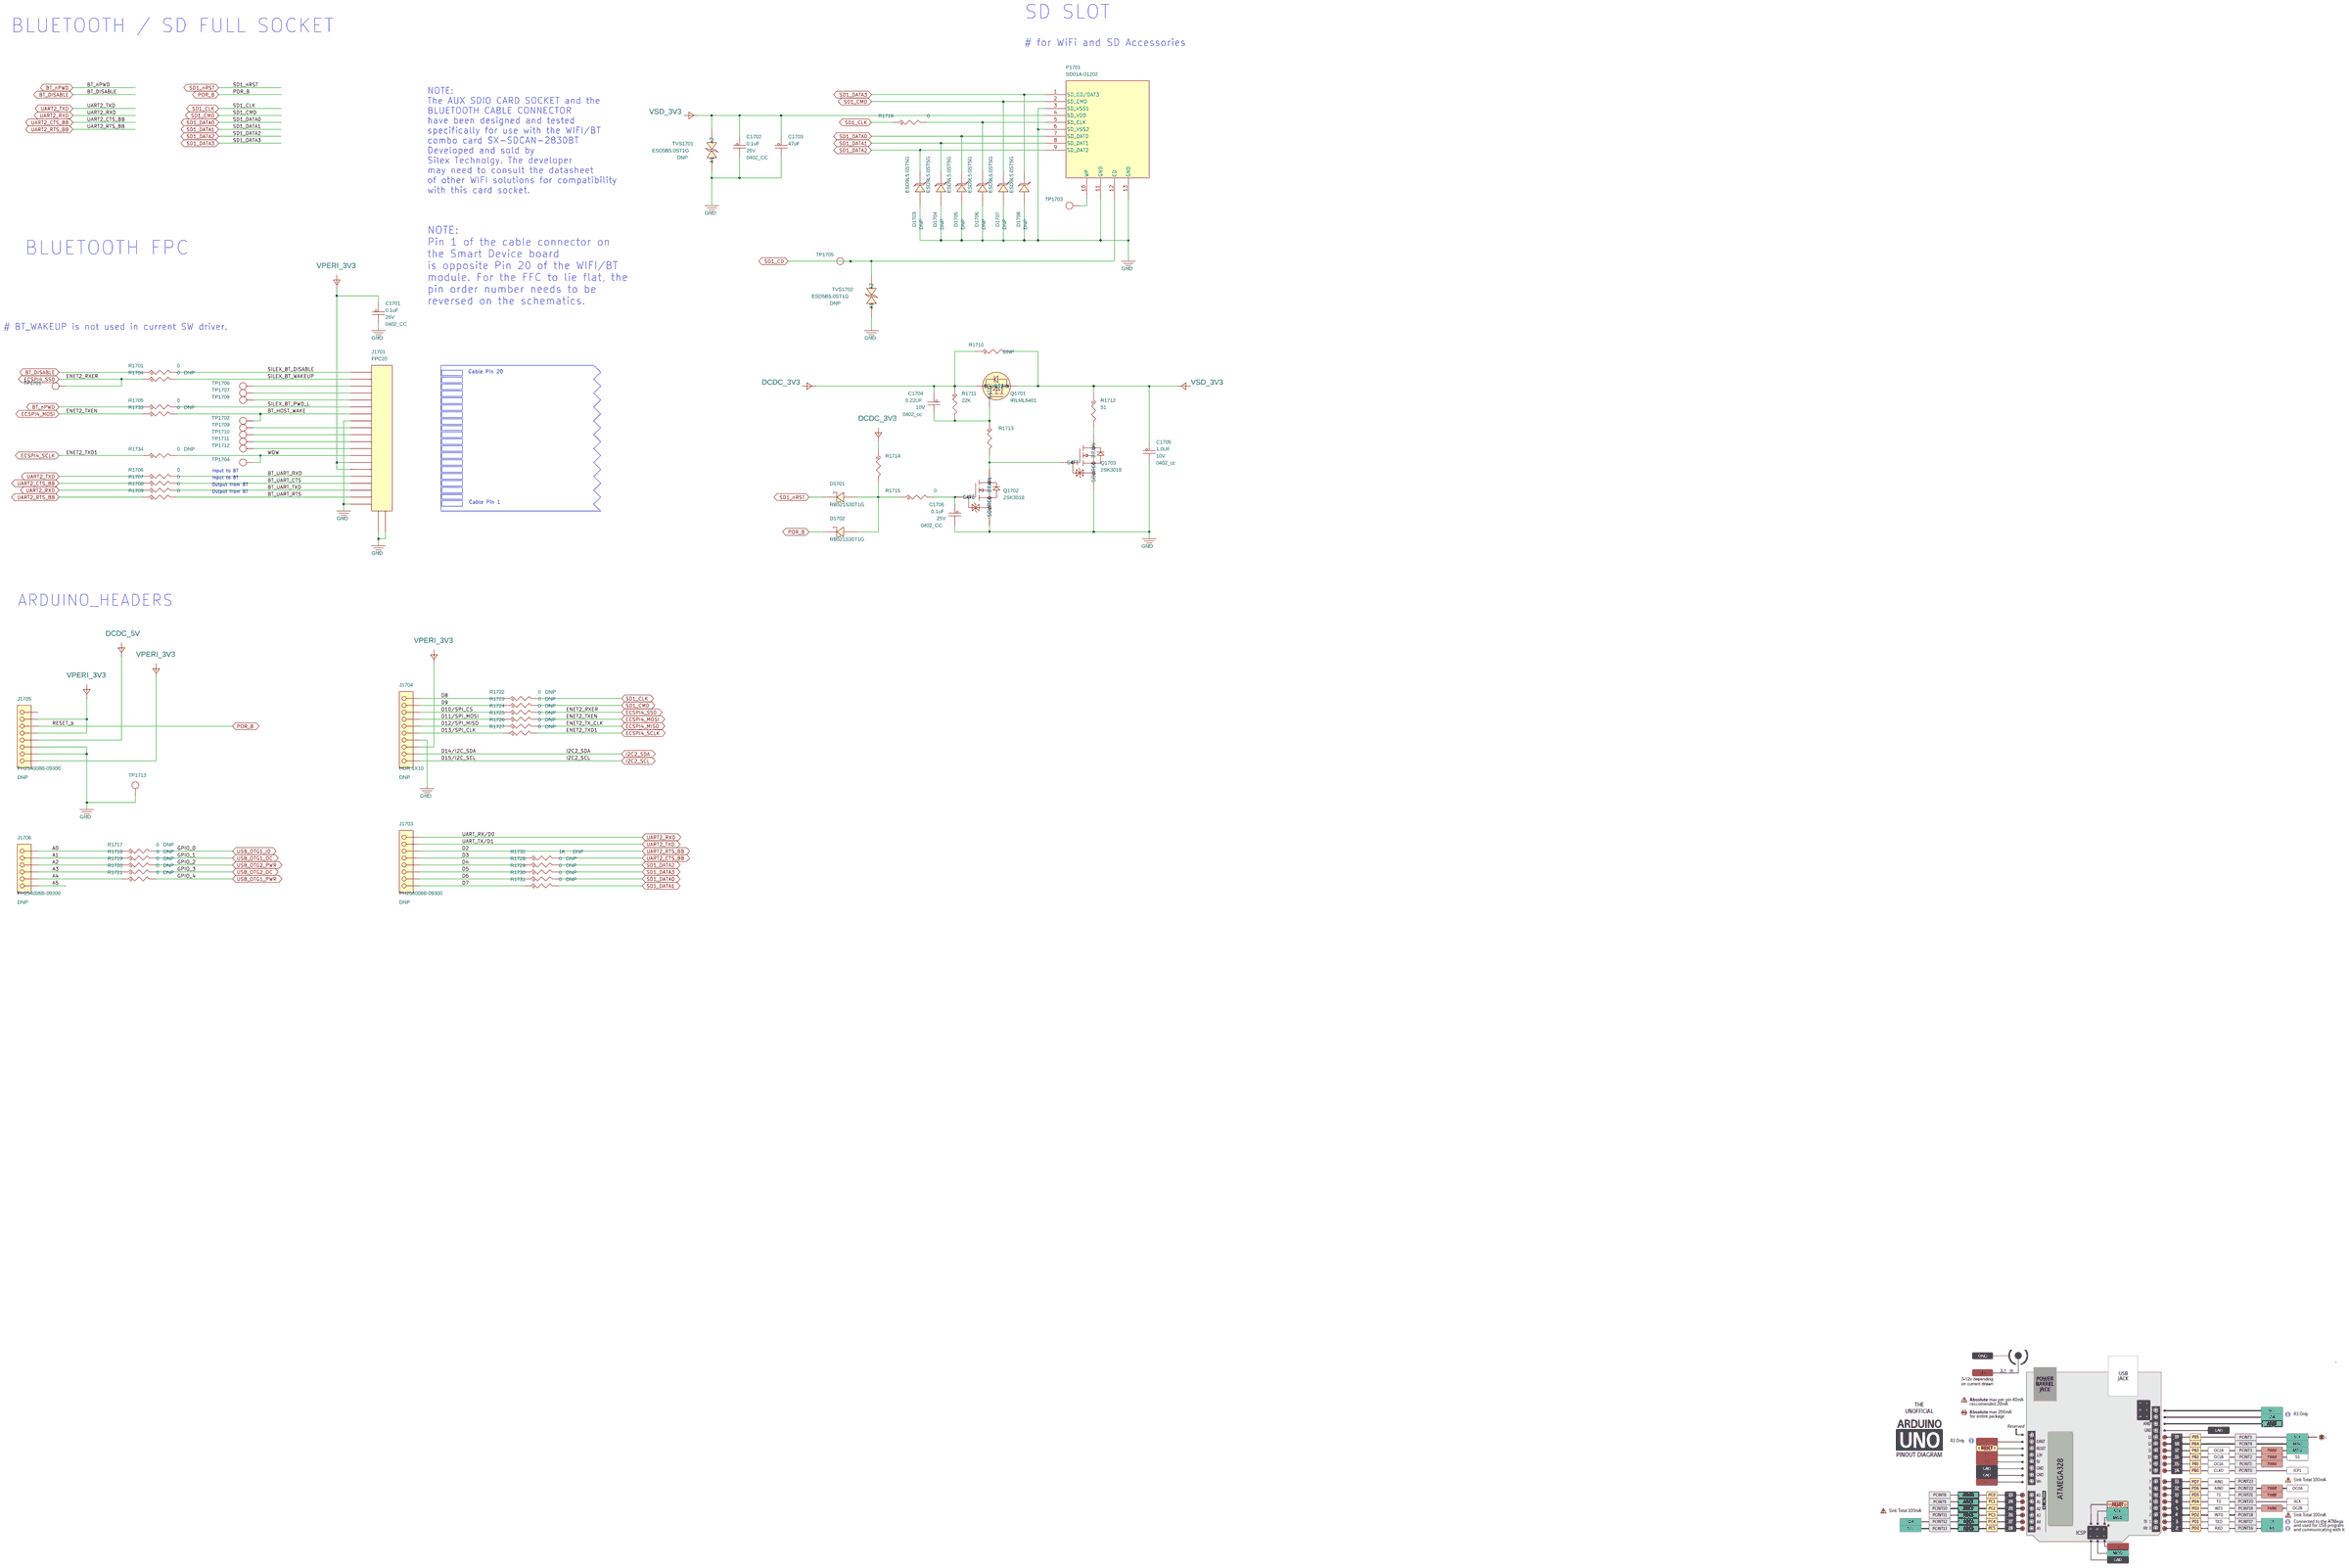
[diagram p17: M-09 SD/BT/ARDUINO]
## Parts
C1701  0.1uF  [0402_CC]
C1702  0.1uF  [0402_CC]
C1703  47uF  [0805_CC]
C1704  0.22UF  [0402_cc]
C1705  1.0UF  [0402_cc]
C1706  0.1uF  [0402_CC]
D1701  RB521S30T1G  [sod_523]
D1702  RB521S30T1G  [sod_523]
D1703  ESD9L5.0ST5G  [sod-923]
D1704  ESD9L5.0ST5G  [sod-923]
D1705  ESD9L5.0ST5G  [sod-923]
D1706  ESD9L5.0ST5G  [sod-923]
D1707  ESD9L5.0ST5G  [sod-923]
D1708  ESD9L5.0ST5G  [sod-923]
J1701  FPC20  [con_fpc_20_0p5_ra_f050_2sh]
J1703  PH254008B-09300  [JUMP1X8-6040]
J1704  HDR 1X10  [hdr110]
J1705  PH254008B-09300  [JUMP1X8-6040]
J1706  PH254006B-09300  [hdr106_b]
P1701  SD01A-01202  [con9_sdcard_28x29mm_smt]
Q1701  IRLML6401  [sot-23]
Q1702  2SK3018  [SOT323_3]
Q1703  2SK3018  [SOT323_3]
R1701  0  [0402_CC]
R1704  0  [0402_CC]
R1705  0  [0402_CC]
R1706  0  [0402_CC]
R1707  0  [0402_CC]
R1708  0  [0402_CC]
R1709  0  [0402_CC]
R1710  0  [0603_CC]
R1711  22K  [0402_CC]
R1712  51  [0402_CC]
R1713  10K  [0402_CC]
R1714  10K  [0402_CC]
R1715  0  [0402_CC]
R1716  0  [0402_CC]
R1717  0  [0402_CC]
R1718  0  [0402_CC]
R1719  0  [0402_CC]
R1720  0  [0402_CC]
R1721  0  [0402_CC]
R1722  0  [0402_CC]
R1723  0  [0402_CC]
R1724  0  [0402_CC]
R1725  0  [0402_CC]
R1726  0  [0402_CC]
R1727  0  [0402_CC]
R1728  0  [0402_CC]
R1729  0  [0402_CC]
R1730  0  [0402_CC]
R1731  0  [0402_CC]
R1732  1K  [0402_CC]
R1733  0  [0402_CC]
R1734  0  [0402_CC]
TP1701  TPAD_020  [tpad_020]
TP1702  TPAD_020  [tpad_020]
TP1703  TPAD_020  [tpad_020]
TP1704  TPAD_020  [tpad_020]
TP1705  TPAD_020  [tpad_020]
TP1706  TPAD_020  [tpad_020]
TP1707  TPAD_020  [tpad_020]
TP1708  TPAD_020  [tpad_020]
TP1709  TPAD_020  [tpad_020]
TP1710  TPAD_020  [tpad_020]
TP1711  TPAD_020  [tpad_020]
TP1712  TPAD_020  [tpad_020]
TP1713  TEST POINT WHITE  [TEST_LOOP]
TVS1701  ESD5B5.0ST1G  [diode2_sod523]
TVS1702  ESD5B5.0ST1G  [diode2_sod523]

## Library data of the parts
C1701 C1702 C1706 = CAP_NP: CAP CER 0.1UF 25V 10% X5R 0402; AGILE_PN: 150-78633; CAD_APPROVED: Yes; FPLIST: CC0402_25,CC0402_HD,0402_CC; HEIGHT: 0.55MM; MFG_NAME01: YAGEO AMERICA; MFG_PN01: CC0402KRX5R8BB104; ROHS: Yes; Tolerance: 10%; VOLTAGE: 25V
C1703 = CAP_NP: CAP CER 47uF 10V 20% X5R 0805; AGILE_PN: 150-78979; CAD_APPROVED: Yes; FPLIST: CC0805_OV,CC0805,0805_CC; HEIGHT: 1.45 MM; MFG_NAME01: TDK; MFG_PN01: C2012X5R1A476M125AC; ROHS: Yes; Tolerance: 20%; VOLTAGE: 10V
C1704 = CAP_NP: CAP CER 0.22UF 10V 10% X5R 0402; AGILE_PN: 150-77358; CAD_APPROVED: Yes; FPLIST: CC0402_25,CC0402_HD,0402_CC; HEIGHT: 0.55MM; MFG_NAME01: MURATA; MFG_PN01: GRM155R61A224KE19B; ROHS: Yes; Tolerance: 10%; VOLTAGE: 10V
C1705 = CAP_NP: CAP CER 1.0UF 10V 10% X5R 0402; AGILE_PN: 150-75772; CAD_APPROVED: Yes; FPLIST: CC0402_25,CC0402_HD,0402_CC; HEIGHT: 0.6MM; MFG_NAME01: YAGEO AMERICA; MFG_PN01: CC0402KRX5R6BB105; ROHS: Yes; VOLTAGE: 10V
D1701 D1702 = DIODE_SCHTKY: DIODE SCH 200MA 30V AEC-Q101 SOD-523; AGILE_PN: 480-78501; CAD_APPROVED: Yes; HEIGHT: 0.7MM; MFG_NAME01: On Semiconductor; ROHS: Yes
D1703-D1708 = DIODE_TVS: DIODE TVS ESD PROT ULT LOW CAP 5-5.4V SOD-923; AGILE_PN: 480-77934; ASSY_OPT: DNP; CAD_APPROVED: Yes; HEIGHT: 0.40MM; MFG_NAME01: ON SEMICONDUCTOR; ROHS: Yes
J1701 = CON20_2SH: CON 1X20 FPC/FFC RA SKT SMT 0.5MM SP 87H SN; AGILE_PN: 211-79307; CAD_APPROVED: Yes; FPLIST: con_fpc_20_0p5_ra_f050,con_fpc_20_0p5_ra_f050_2sh; HEIGHT: 2.2 MM; MFG_NAME01: SHENZHEN ATOM TECHNOLOGY CO.,LTD; MFG_PN01: F05020-S030105A08200; ROHS: Yes
J1703 J1705 = CONN_HDR_8X1: HDR 1X8 TH 100MIL SP 347H AU 118L; AGILE_PN: 210-80829; ASSY_OPT: DNP; CAD_APPROVED: Yes; HEIGHT: 8.8MM; MFG_NAME01: SHENZHEN ATOM TECHNOLOGY CO.,LTD; ROHS: Yes
J1704 = CONN_HDR_10X1: HDR 1X10 TH 100MIL SP 346H AU 118L; AGILE_PN: 210-80776; ASSY_OPT: DNP; CAD_APPROVED: Yes; HEIGHT: 8.8MM; MFG_NAME01: SHENZHEN ATOM TECHNOLOGY CO.,LTD; MFG_PN01: PH254010B-09300; ROHS: Yes
J1706 = CONN_HDR_6X1: HDR 1X6 TH 100MIL SP 347H AU 118L; AGILE_PN: 210-80828; ASSY_OPT: DNP; CAD_APPROVED: Yes; HEIGHT: 8.8MM; MFG_NAME01: SHENZHEN ATOM TECHNOLOGY CO.,LTD; ROHS: Yes
P1701 = SD_SOCKET_SMT: CON 9 SD CARD SKT SMT 2.5MM -- 114H AU; AGILE_PN: TMP-WF-24049; CAD_APPROVED: Yes; HEIGHT: 2.9MM; MFG_NAME01: SHENZHEN ATOM TECHNOLOGY CO.,LTD; PRE_APN: 211-79703; ROHS: Yes
Q1701 = MOSFET_P: TRAN PMOS PWR 12V 4.3A SOT23; AGILE_PN: 480-77718; CAD_APPROVED: Yes; HEIGHT: 1.12MM; MFG_NAME01: INTERNATIONAL RECTIFIER; MFG_PN01: IRLML6401TRPBF; ROHS: Yes
Q1702 Q1703 = 2SK3018: TRANS MOSFET N-CH 30V .1A SOT-323; AGILE_PN: 480-75317; CAD_APPROVED: Yes; HEIGHT: 0.9MM; MFG_NAME01: ROHM; MFG_PN01: 2SK3018T106; ROHS: Yes
R1701 R1705-R1709 R1715 R1716 = RES: RES MF ZERO OHM 1/16W 5% 0402; AGILE_PN: 470-75394; CAD_APPROVED: Yes; FPLIST: RC0402_25,RC0402_HD,RC0402_X2,0402_CC; HEIGHT: 0.45 MM; MFG_NAME01: ROHM; MFG_PN01: MCR01MZPJ000; ROHS: Yes; Tolerance: 5%
R1704 R1717-R1731 R1733 R1734 = RES: RES MF ZERO OHM 1/16W 5% 0402; AGILE_PN: 470-75394; ASSY_OPT: DNP; CAD_APPROVED: Yes; FPLIST: RC0402_25,RC0402_HD,RC0402_X2,0402_CC; HEIGHT: 0.45 MM; MFG_NAME01: ROHM; MFG_PN01: MCR01MZPJ000; ROHS: Yes; Tolerance: 5%
R1710 = RES: RES MF ZERO OHM 1/10W -- AEC-Q200 0603; AGILE_PN: 470-75407; ASSY_OPT: DNP; CAD_APPROVED: Yes; FPLIST: RC0603_OV,RC0603,R603-X2,0603_CC; HEIGHT: 0.6MM; MFG_NAME01: KOA SPEER; MFG_PN01: RK73Z1JTTD; ROHS: Yes; Tolerance: 1%
R1711 = RES: RES MF 22K 1/16W 5% 0402; AGILE_PN: 470-75609; CAD_APPROVED: Yes; FPLIST: RC0402_25,RC0402_HD,0402_CC; HEIGHT: 0.41mm; MFG_NAME01: SMEC; MFG_PN01: RC73L2Z223JTF; ROHS: Yes; Tolerance: 5%
R1712 = RES: RES MF 51 OHM 1/16W 5% 0402; AGILE_PN: 470-76089; CAD_APPROVED: Yes; FPLIST: RC0402_25,RC0402_HD,0402_CC; HEIGHT: 0.40 MM; MFG_NAME01: YAGEO AMERICA; MFG_PN01: RC0402JR-0751RL; ROHS: Yes; Tolerance: 5%
R1713 R1714 = RES: RES MF 10K 1/16W 5% 0402; AGILE_PN: 470-75557; CAD_APPROVED: Yes; FPLIST: RC0402_25,RC0402_HD,0402_CC; HEIGHT: 0.4 MM; MFG_NAME01: VISHAY INTERTECHNOLOGY; MFG_PN01: CRCW040210K0JNED; ROHS: Yes; TOL: 5%; Tolerance: 5%
R1732 = RES: RES MF 1.0K 1/16W 5% 0402; AGILE_PN: 470-75555; ASSY_OPT: DNP; CAD_APPROVED: Yes; FPLIST: RC0402_25,RC0402_HD,RC0402_X2,0402_CC; HEIGHT: 0.41mm; MFG_NAME01: VISHAY INTERTECHNOLOGY; MFG_PN01: CRCW04021K00JNED; ROHS: Yes; Tolerance: 5%
TP1701 TP1702 TP1704 TP1706-TP1712 = TESTLOOP: TEST POINT PAD 0.5MM DIA SMT, NO PART TO ORDER; AGILE_PN: 211-77484; ASSY_OPT: DNP; CAD_APPROVED: Yes; HEIGHT: 0.1MM; ROHS: Yes
TP1703 TP1705 = TESTLOOP: TEST POINT PAD 0.5MM DIA SMT, NO PART TO ORDER; AGILE_PN: 211-77484; CAD_APPROVED: Yes; HEIGHT: 0.1MM; ROHS: Yes
TP1713 = TestLoop: TEST POINT WHITE 40 MIL DRILL 180 MIL TH 109L; AGILE_PN: 210-75685; CAD_APPROVED: Yes; HEIGHT: 4.8 MM; MFG_NAME01: KEYSTONE ELECTRONICS; MFG_PN01: 5002; ROHS: Yes
TVS1701 TVS1702 = DIODE_TVS_BIDIR: DIODE SUPPRESSOR 16A@30NS 5V@1UA SOD-523; AGILE_PN: 480-76937; ASSY_OPT: DNP; CAD_APPROVED: Yes; HEIGHT: 0.7MM; MFG_NAME01: on semiconductor; ROHS: Yes

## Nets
GND: C1701.2 C1702.2 C1703.2 C1705.2 C1706.2 D1703.A D1704.A D1705.A D1706.A D1707.A D1708.A J1701.8 J1701.20 J1701.S1 J1701.S2 J1704.7 J1705.6 J1705.7 P1701.3(SD_VSS1) P1701.6(SD_VSS2) P1701.11(GND) P1701.13(GND) Q1702.1(SOURCE) Q1703.1(SOURCE) TP1713.1(Pin1) TVS1701.1(A1) TVS1702.1(A1) ; also on sheet 3 4 5 6 7 8 12 13 14 15 16 17
A0: J1706.1 R1717.1
A1: J1706.2 R1718.1
A2: J1706.3 R1719.1
A3: J1706.4 R1720.1
A4: J1706.5 R1721.1
A5: J1706.6
BT_DISABLE: R1701.1 ; also on sheet 3
BT_HOST_WAKE: J1701.7 R1733.2 TP1702.1(Pin1)
BT_nPWD: R1705.1 ; also on sheet 3
BT_UART_CTS: J1701.17 R1707.2
BT_UART_RTS: J1701.19 R1709.2
BT_UART_RXD: J1701.16 R1706.2
BT_UART_TXD: J1701.18 R1708.2
D3: J1703.4 R1732.1
D4: J1703.5 R1728.1
D5: J1703.6 R1729.1
D6: J1703.7 R1730.1
D7: J1703.8 R1731.1
D8: J1704.1 R1722.1
D9: J1704.2 R1723.1
D10/SPI_CS: J1704.3 R1724.1
D11/SPI_MOSI: J1704.4 R1725.1
D12/SPI_MISO: J1704.5 R1726.1
D13/SPI_CLK: J1704.6 R1727.1
DCDC_3V3: C1704.1 Q1701.2(SOURCE) R1710.1 R1711.1 R1714.1 ; also on sheet 3 4 8 12 16 17
DCDC_5V: J1705.5 ; also on sheet 7 12 15 17
ECSPI4_MISO: R1726.2 ; also on sheet 3 8 14
ECSPI4_MOSI: R1725.2 R1733.1 ; also on sheet 3 8 14
ECSPI4_SCLK: R1727.2 R1734.1 ; also on sheet 3 8 14
ECSPI4_SS0: R1704.1 R1724.2 TP1701.1(Pin1) ; also on sheet 3 8 14
I2C2_SCL: J1704.10 ; also on sheet 3 4 5 8 12
I2C2_SDA: J1704.9 ; also on sheet 3 4 5 8 12
POR_B: D1702.C J1705.3 ; also on sheet 3 16
SD1_CD: P1701.12(CD) TP1705.1(Pin1) TVS1702.2(A2) ; also on sheet 3
SD1_CLK: R1716.1 R1722.2 ; also on sheet 3
SD1_CMD: D1707.C P1701.2(SD_CMD) R1723.2 ; also on sheet 3
SD1_DATA0: D1705.C P1701.7(SD_DAT0) R1730.2 ; also on sheet 3
SD1_DATA1: D1704.C P1701.8(SD_DAT1) R1731.2 ; also on sheet 3
SD1_DATA2: D1703.C P1701.9(SD_DAT2) R1728.2 ; also on sheet 3
SD1_DATA3: D1708.C P1701.1(SD_CD/DAT3) R1729.2 ; also on sheet 3
SD1_nRST: D1701.C ; also on sheet 3
SILEX_BT_DISABLE: J1701.1 R1701.2
SILEX_BT_PWD_L: J1701.6 R1705.2
SILEX_BT_WAKEUP: J1701.2 R1704.2
UART2_CTS_BB: R1707.1 R1732.2 ; also on sheet 3
UART2_RTS_BB: J1703.3 R1709.1 ; also on sheet 3
UART2_RXD: J1703.1 R1708.1 ; also on sheet 3
UART2_TXD: J1703.2 R1706.1 ; also on sheet 3
USB_OTG1_ID: R1717.2 ; also on sheet 3 17
USB_OTG1_OC: R1718.2 ; also on sheet 3 8 17
USB_OTG1_PWR: R1721.2 ; also on sheet 3 8 15 17
USB_OTG2_OC: R1720.2 ; also on sheet 3 8 17
USB_OTG2_PWR: R1719.2 ; also on sheet 3 8 17
VENET_3V3: C1701.1 J1701.14 J1701.15 J1704.8 J1705.2 J1705.4 J1705.8 ; also on sheet 3 4 5 6 7 13 14
VSD_3V3: C1702.1 C1703.1 C1705.1 P1701.4(SD_VDD) Q1701.3(DRAIN) R1710.2 R1712.1 TVS1701.2(A2)
WOW: J1701.13 R1734.2 TP1704.1(Pin1)
N97081112: Q1703.3(DRAIN) R1712.2
N97081468: D1701.A D1702.A R1714.2 R1715.1
N97081502: C1704.2 Q1701.1(GATE) R1711.2 R1713.1
N97185823: P1701.10(WP) TP1703.1(Pin1)
N97565569: C1706.1 Q1702.2(GATE) R1715.2
N97565776: Q1702.3(DRAIN) Q1703.2(GATE) R1713.2
N98831920: D1706.C P1701.5(SD_CLK) R1716.2
N99305307: J1701.3 TP1706.1(Pin1)
N99305310: J1701.4 TP1707.1(Pin1)
N99305313: J1701.5 TP1708.1(Pin1)
N99305316: J1701.9 TP1709.1(Pin1)
N99305319: J1701.10 TP1710.1(Pin1)
N99305322: J1701.11 TP1711.1(Pin1)
N99305325: J1701.12 TP1712.1(Pin1)

Not connected (* = marked no-connect by the designer): J1705 1

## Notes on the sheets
sheet 18
- SD SLOT
- BLUETOOTH / SD FULL SOCKET
- # for WiFi and SD Accessories
- NOTE:
  The AUX SDIO CARD SOCKET and the
  BLUETOOTH CABLE CONNECTOR
  have been designed and tested
  specifically for use with the WIFI/BT
  combo card SX-SDCAN-2830BT
  Developed and sold by
  Silex Technolgy. The developer
  may need to consult the datasheet
  of other WIFI solutions for compatibility
  with this card socket.
- NOTE:
  Pin 1 of the cable connector on
  the Smart Device board
  is opposite Pin 20 of the WIFI/BT
  module. For the FFC to lie flat, the
  pin order number needs to be
  reversed on the schematics.
- BLUETOOTH FPC
- # BT_WAKEUP is not used in current SW driver.
- Cable Pin 20
- Input to BT
- Input to BT
- Output from BT
- Output from BT
- Cable Pin 1
- ARDUINO_HEADERS
